VERSION 5.8 ;
BUSBITCHARS "[]" ;
DIVIDERCHAR "/" ;
UNITS
    DATABASE MICRONS 1000 ;
END UNITS

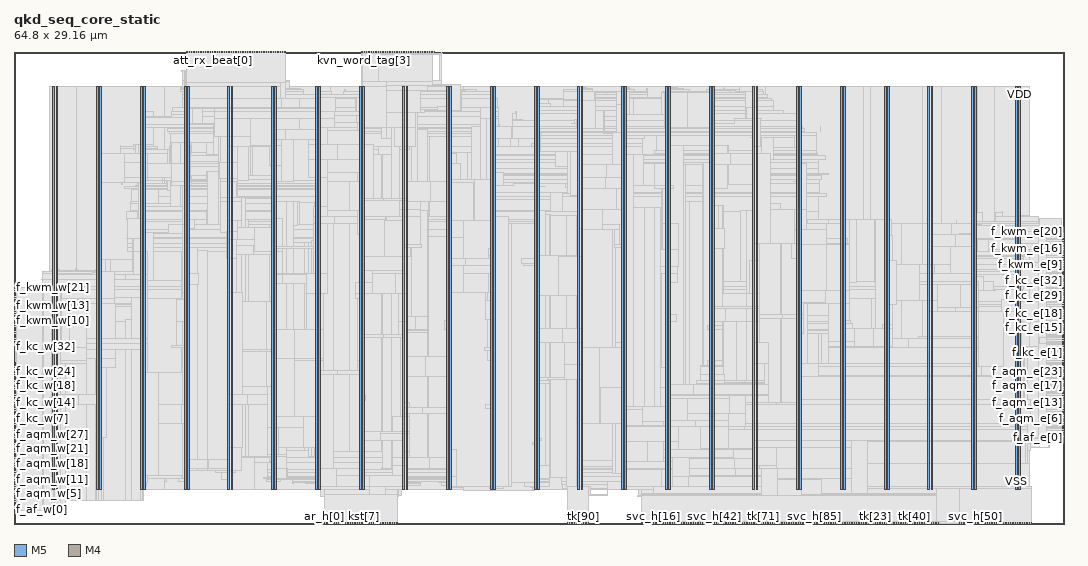
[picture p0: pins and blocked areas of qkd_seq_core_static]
MACRO qkd_seq_core_static
  FOREIGN qkd_seq_core_static 0 0 ;
  CLASS BLOCK ;
  SIZE 64.8 BY 29.16 ;
  PIN ar_h[0]
    DIRECTION INPUT ;
    USE SIGNAL ;
    PORT
      LAYER M5 ;
        RECT  19.152 0 19.176 0.084 ;
    END
  END ar_h[0]
  PIN ar_h[1]
    DIRECTION INPUT ;
    USE SIGNAL ;
    PORT
      LAYER M5 ;
        RECT  19.296 0 19.32 0.084 ;
    END
  END ar_h[1]
  PIN ar_h[2]
    DIRECTION INPUT ;
    USE SIGNAL ;
    PORT
      LAYER M5 ;
        RECT  19.44 0 19.464 0.084 ;
    END
  END ar_h[2]
  PIN ar_h[3]
    DIRECTION INPUT ;
    USE SIGNAL ;
    PORT
      LAYER M5 ;
        RECT  19.584 0 19.608 0.084 ;
    END
  END ar_h[3]
  PIN ar_h[4]
    DIRECTION INPUT ;
    USE SIGNAL ;
    PORT
      LAYER M5 ;
        RECT  19.728 0 19.752 0.084 ;
    END
  END ar_h[4]
  PIN ar_h[5]
    DIRECTION INPUT ;
    USE SIGNAL ;
    PORT
      LAYER M5 ;
        RECT  19.872 0 19.896 0.084 ;
    END
  END ar_h[5]
  PIN ar_h[6]
    DIRECTION INPUT ;
    USE SIGNAL ;
    PORT
      LAYER M5 ;
        RECT  20.016 0 20.04 0.084 ;
    END
  END ar_h[6]
  PIN ar_h[7]
    DIRECTION INPUT ;
    USE SIGNAL ;
    PORT
      LAYER M5 ;
        RECT  20.16 0 20.184 0.084 ;
    END
  END ar_h[7]
  PIN att_rx_beat[0]
    DIRECTION INPUT ;
    USE SIGNAL ;
    PORT
      LAYER M5 ;
        RECT  12.24 29.076 12.264 29.16 ;
    END
  END att_rx_beat[0]
  PIN att_rx_beat[1]
    DIRECTION INPUT ;
    USE SIGNAL ;
    PORT
      LAYER M5 ;
        RECT  12.384 29.076 12.408 29.16 ;
    END
  END att_rx_beat[1]
  PIN att_rx_beat[2]
    DIRECTION INPUT ;
    USE SIGNAL ;
    PORT
      LAYER M5 ;
        RECT  12.528 29.076 12.552 29.16 ;
    END
  END att_rx_beat[2]
  PIN att_rx_beat[3]
    DIRECTION INPUT ;
    USE SIGNAL ;
    PORT
      LAYER M5 ;
        RECT  12.672 29.076 12.696 29.16 ;
    END
  END att_rx_beat[3]
  PIN att_rx_beat[4]
    DIRECTION INPUT ;
    USE SIGNAL ;
    PORT
      LAYER M5 ;
        RECT  12.816 29.076 12.84 29.16 ;
    END
  END att_rx_beat[4]
  PIN att_rx_kind[0]
    DIRECTION INPUT ;
    USE SIGNAL ;
    PORT
      LAYER M5 ;
        RECT  12.96 29.076 12.984 29.16 ;
    END
  END att_rx_kind[0]
  PIN att_rx_kind[1]
    DIRECTION INPUT ;
    USE SIGNAL ;
    PORT
      LAYER M5 ;
        RECT  13.104 29.076 13.128 29.16 ;
    END
  END att_rx_kind[1]
  PIN att_rx_kind[2]
    DIRECTION INPUT ;
    USE SIGNAL ;
    PORT
      LAYER M5 ;
        RECT  13.248 29.076 13.272 29.16 ;
    END
  END att_rx_kind[2]
  PIN att_rx_kind[3]
    DIRECTION INPUT ;
    USE SIGNAL ;
    PORT
      LAYER M5 ;
        RECT  13.392 29.076 13.416 29.16 ;
    END
  END att_rx_kind[3]
  PIN att_rx_v
    DIRECTION INPUT ;
    USE SIGNAL ;
    PORT
      LAYER M5 ;
        RECT  13.536 29.076 13.56 29.16 ;
    END
  END att_rx_v
  PIN ck
    DIRECTION INPUT ;
    USE SIGNAL ;
    PORT
      LAYER M5 ;
        RECT  13.68 29.076 13.704 29.16 ;
    END
  END ck
  PIN cmd_d[0]
    DIRECTION INPUT ;
    USE SIGNAL ;
    PORT
      LAYER M5 ;
        RECT  13.824 29.076 13.848 29.16 ;
    END
  END cmd_d[0]
  PIN cmd_d[10]
    DIRECTION INPUT ;
    USE SIGNAL ;
    PORT
      LAYER M5 ;
        RECT  15.264 29.076 15.288 29.16 ;
    END
  END cmd_d[10]
  PIN cmd_d[11]
    DIRECTION INPUT ;
    USE SIGNAL ;
    PORT
      LAYER M5 ;
        RECT  15.408 29.076 15.432 29.16 ;
    END
  END cmd_d[11]
  PIN cmd_d[12]
    DIRECTION INPUT ;
    USE SIGNAL ;
    PORT
      LAYER M5 ;
        RECT  15.552 29.076 15.576 29.16 ;
    END
  END cmd_d[12]
  PIN cmd_d[13]
    DIRECTION INPUT ;
    USE SIGNAL ;
    PORT
      LAYER M5 ;
        RECT  15.696 29.076 15.72 29.16 ;
    END
  END cmd_d[13]
  PIN cmd_d[14]
    DIRECTION INPUT ;
    USE SIGNAL ;
    PORT
      LAYER M5 ;
        RECT  15.84 29.076 15.864 29.16 ;
    END
  END cmd_d[14]
  PIN cmd_d[15]
    DIRECTION INPUT ;
    USE SIGNAL ;
    PORT
      LAYER M5 ;
        RECT  15.984 29.076 16.008 29.16 ;
    END
  END cmd_d[15]
  PIN cmd_d[16]
    DIRECTION INPUT ;
    USE SIGNAL ;
    PORT
      LAYER M5 ;
        RECT  16.128 29.076 16.152 29.16 ;
    END
  END cmd_d[16]
  PIN cmd_d[17]
    DIRECTION INPUT ;
    USE SIGNAL ;
    PORT
      LAYER M5 ;
        RECT  16.272 29.076 16.296 29.16 ;
    END
  END cmd_d[17]
  PIN cmd_d[18]
    DIRECTION INPUT ;
    USE SIGNAL ;
    PORT
      LAYER M5 ;
        RECT  16.416 29.076 16.44 29.16 ;
    END
  END cmd_d[18]
  PIN cmd_d[1]
    DIRECTION INPUT ;
    USE SIGNAL ;
    PORT
      LAYER M5 ;
        RECT  13.968 29.076 13.992 29.16 ;
    END
  END cmd_d[1]
  PIN cmd_d[2]
    DIRECTION INPUT ;
    USE SIGNAL ;
    PORT
      LAYER M5 ;
        RECT  14.112 29.076 14.136 29.16 ;
    END
  END cmd_d[2]
  PIN cmd_d[3]
    DIRECTION INPUT ;
    USE SIGNAL ;
    PORT
      LAYER M5 ;
        RECT  14.256 29.076 14.28 29.16 ;
    END
  END cmd_d[3]
  PIN cmd_d[4]
    DIRECTION INPUT ;
    USE SIGNAL ;
    PORT
      LAYER M5 ;
        RECT  14.4 29.076 14.424 29.16 ;
    END
  END cmd_d[4]
  PIN cmd_d[5]
    DIRECTION INPUT ;
    USE SIGNAL ;
    PORT
      LAYER M5 ;
        RECT  14.544 29.076 14.568 29.16 ;
    END
  END cmd_d[5]
  PIN cmd_d[6]
    DIRECTION INPUT ;
    USE SIGNAL ;
    PORT
      LAYER M5 ;
        RECT  14.688 29.076 14.712 29.16 ;
    END
  END cmd_d[6]
  PIN cmd_d[7]
    DIRECTION INPUT ;
    USE SIGNAL ;
    PORT
      LAYER M5 ;
        RECT  14.832 29.076 14.856 29.16 ;
    END
  END cmd_d[7]
  PIN cmd_d[8]
    DIRECTION INPUT ;
    USE SIGNAL ;
    PORT
      LAYER M5 ;
        RECT  14.976 29.076 15 29.16 ;
    END
  END cmd_d[8]
  PIN cmd_d[9]
    DIRECTION INPUT ;
    USE SIGNAL ;
    PORT
      LAYER M5 ;
        RECT  15.12 29.076 15.144 29.16 ;
    END
  END cmd_d[9]
  PIN f_af_e[0]
    DIRECTION INPUT ;
    USE SIGNAL ;
    PORT
      LAYER M4 ;
        RECT  64.716 5.328 64.8 5.352 ;
    END
  END f_af_e[0]
  PIN f_af_e[1]
    DIRECTION INPUT ;
    USE SIGNAL ;
    PORT
      LAYER M4 ;
        RECT  64.716 5.472 64.8 5.496 ;
    END
  END f_af_e[1]
  PIN f_af_w[0]
    DIRECTION INPUT ;
    USE SIGNAL ;
    PORT
      LAYER M4 ;
        RECT  0 0.864 0.084 0.888 ;
    END
  END f_af_w[0]
  PIN f_af_w[1]
    DIRECTION INPUT ;
    USE SIGNAL ;
    PORT
      LAYER M4 ;
        RECT  0 1.008 0.084 1.032 ;
    END
  END f_af_w[1]
  PIN f_aqm_e[0]
    DIRECTION OUTPUT ;
    USE SIGNAL ;
    PORT
      LAYER M4 ;
        RECT  64.716 5.616 64.8 5.64 ;
    END
  END f_aqm_e[0]
  PIN f_aqm_e[10]
    DIRECTION OUTPUT ;
    USE SIGNAL ;
    PORT
      LAYER M4 ;
        RECT  64.716 7.056 64.8 7.08 ;
    END
  END f_aqm_e[10]
  PIN f_aqm_e[11]
    DIRECTION OUTPUT ;
    USE SIGNAL ;
    PORT
      LAYER M4 ;
        RECT  64.716 7.2 64.8 7.224 ;
    END
  END f_aqm_e[11]
  PIN f_aqm_e[12]
    DIRECTION OUTPUT ;
    USE SIGNAL ;
    PORT
      LAYER M4 ;
        RECT  64.716 7.344 64.8 7.368 ;
    END
  END f_aqm_e[12]
  PIN f_aqm_e[13]
    DIRECTION OUTPUT ;
    USE SIGNAL ;
    PORT
      LAYER M4 ;
        RECT  64.716 7.488 64.8 7.512 ;
    END
  END f_aqm_e[13]
  PIN f_aqm_e[14]
    DIRECTION OUTPUT ;
    USE SIGNAL ;
    PORT
      LAYER M4 ;
        RECT  64.716 7.632 64.8 7.656 ;
    END
  END f_aqm_e[14]
  PIN f_aqm_e[15]
    DIRECTION OUTPUT ;
    USE SIGNAL ;
    PORT
      LAYER M4 ;
        RECT  64.716 7.776 64.8 7.8 ;
    END
  END f_aqm_e[15]
  PIN f_aqm_e[16]
    DIRECTION OUTPUT ;
    USE SIGNAL ;
    PORT
      LAYER M4 ;
        RECT  64.716 7.92 64.8 7.944 ;
    END
  END f_aqm_e[16]
  PIN f_aqm_e[17]
    DIRECTION OUTPUT ;
    USE SIGNAL ;
    PORT
      LAYER M4 ;
        RECT  64.716 8.064 64.8 8.088 ;
    END
  END f_aqm_e[17]
  PIN f_aqm_e[18]
    DIRECTION OUTPUT ;
    USE SIGNAL ;
    PORT
      LAYER M4 ;
        RECT  64.716 8.208 64.8 8.232 ;
    END
  END f_aqm_e[18]
  PIN f_aqm_e[19]
    DIRECTION OUTPUT ;
    USE SIGNAL ;
    PORT
      LAYER M4 ;
        RECT  64.716 8.352 64.8 8.376 ;
    END
  END f_aqm_e[19]
  PIN f_aqm_e[1]
    DIRECTION OUTPUT ;
    USE SIGNAL ;
    PORT
      LAYER M4 ;
        RECT  64.716 5.76 64.8 5.784 ;
    END
  END f_aqm_e[1]
  PIN f_aqm_e[20]
    DIRECTION OUTPUT ;
    USE SIGNAL ;
    PORT
      LAYER M4 ;
        RECT  64.716 8.496 64.8 8.52 ;
    END
  END f_aqm_e[20]
  PIN f_aqm_e[21]
    DIRECTION OUTPUT ;
    USE SIGNAL ;
    PORT
      LAYER M4 ;
        RECT  64.716 8.64 64.8 8.664 ;
    END
  END f_aqm_e[21]
  PIN f_aqm_e[22]
    DIRECTION OUTPUT ;
    USE SIGNAL ;
    PORT
      LAYER M4 ;
        RECT  64.716 8.784 64.8 8.808 ;
    END
  END f_aqm_e[22]
  PIN f_aqm_e[23]
    DIRECTION OUTPUT ;
    USE SIGNAL ;
    PORT
      LAYER M4 ;
        RECT  64.716 8.928 64.8 8.952 ;
    END
  END f_aqm_e[23]
  PIN f_aqm_e[24]
    DIRECTION OUTPUT ;
    USE SIGNAL ;
    PORT
      LAYER M4 ;
        RECT  64.716 9.072 64.8 9.096 ;
    END
  END f_aqm_e[24]
  PIN f_aqm_e[25]
    DIRECTION OUTPUT ;
    USE SIGNAL ;
    PORT
      LAYER M4 ;
        RECT  64.716 9.216 64.8 9.24 ;
    END
  END f_aqm_e[25]
  PIN f_aqm_e[26]
    DIRECTION OUTPUT ;
    USE SIGNAL ;
    PORT
      LAYER M4 ;
        RECT  64.716 9.36 64.8 9.384 ;
    END
  END f_aqm_e[26]
  PIN f_aqm_e[27]
    DIRECTION OUTPUT ;
    USE SIGNAL ;
    PORT
      LAYER M4 ;
        RECT  64.716 9.504 64.8 9.528 ;
    END
  END f_aqm_e[27]
  PIN f_aqm_e[2]
    DIRECTION OUTPUT ;
    USE SIGNAL ;
    PORT
      LAYER M4 ;
        RECT  64.716 5.904 64.8 5.928 ;
    END
  END f_aqm_e[2]
  PIN f_aqm_e[3]
    DIRECTION OUTPUT ;
    USE SIGNAL ;
    PORT
      LAYER M4 ;
        RECT  64.716 6.048 64.8 6.072 ;
    END
  END f_aqm_e[3]
  PIN f_aqm_e[4]
    DIRECTION OUTPUT ;
    USE SIGNAL ;
    PORT
      LAYER M4 ;
        RECT  64.716 6.192 64.8 6.216 ;
    END
  END f_aqm_e[4]
  PIN f_aqm_e[5]
    DIRECTION OUTPUT ;
    USE SIGNAL ;
    PORT
      LAYER M4 ;
        RECT  64.716 6.336 64.8 6.36 ;
    END
  END f_aqm_e[5]
  PIN f_aqm_e[6]
    DIRECTION OUTPUT ;
    USE SIGNAL ;
    PORT
      LAYER M4 ;
        RECT  64.716 6.48 64.8 6.504 ;
    END
  END f_aqm_e[6]
  PIN f_aqm_e[7]
    DIRECTION OUTPUT ;
    USE SIGNAL ;
    PORT
      LAYER M4 ;
        RECT  64.716 6.624 64.8 6.648 ;
    END
  END f_aqm_e[7]
  PIN f_aqm_e[8]
    DIRECTION OUTPUT ;
    USE SIGNAL ;
    PORT
      LAYER M4 ;
        RECT  64.716 6.768 64.8 6.792 ;
    END
  END f_aqm_e[8]
  PIN f_aqm_e[9]
    DIRECTION OUTPUT ;
    USE SIGNAL ;
    PORT
      LAYER M4 ;
        RECT  64.716 6.912 64.8 6.936 ;
    END
  END f_aqm_e[9]
  PIN f_aqm_w[0]
    DIRECTION OUTPUT ;
    USE SIGNAL ;
    PORT
      LAYER M4 ;
        RECT  0 1.152 0.084 1.176 ;
    END
  END f_aqm_w[0]
  PIN f_aqm_w[10]
    DIRECTION OUTPUT ;
    USE SIGNAL ;
    PORT
      LAYER M4 ;
        RECT  0 2.592 0.084 2.616 ;
    END
  END f_aqm_w[10]
  PIN f_aqm_w[11]
    DIRECTION OUTPUT ;
    USE SIGNAL ;
    PORT
      LAYER M4 ;
        RECT  0 2.736 0.084 2.76 ;
    END
  END f_aqm_w[11]
  PIN f_aqm_w[12]
    DIRECTION OUTPUT ;
    USE SIGNAL ;
    PORT
      LAYER M4 ;
        RECT  0 2.88 0.084 2.904 ;
    END
  END f_aqm_w[12]
  PIN f_aqm_w[13]
    DIRECTION OUTPUT ;
    USE SIGNAL ;
    PORT
      LAYER M4 ;
        RECT  0 3.024 0.084 3.048 ;
    END
  END f_aqm_w[13]
  PIN f_aqm_w[14]
    DIRECTION OUTPUT ;
    USE SIGNAL ;
    PORT
      LAYER M4 ;
        RECT  0 3.168 0.084 3.192 ;
    END
  END f_aqm_w[14]
  PIN f_aqm_w[15]
    DIRECTION OUTPUT ;
    USE SIGNAL ;
    PORT
      LAYER M4 ;
        RECT  0 3.312 0.084 3.336 ;
    END
  END f_aqm_w[15]
  PIN f_aqm_w[16]
    DIRECTION OUTPUT ;
    USE SIGNAL ;
    PORT
      LAYER M4 ;
        RECT  0 3.456 0.084 3.48 ;
    END
  END f_aqm_w[16]
  PIN f_aqm_w[17]
    DIRECTION OUTPUT ;
    USE SIGNAL ;
    PORT
      LAYER M4 ;
        RECT  0 3.6 0.084 3.624 ;
    END
  END f_aqm_w[17]
  PIN f_aqm_w[18]
    DIRECTION OUTPUT ;
    USE SIGNAL ;
    PORT
      LAYER M4 ;
        RECT  0 3.744 0.084 3.768 ;
    END
  END f_aqm_w[18]
  PIN f_aqm_w[19]
    DIRECTION OUTPUT ;
    USE SIGNAL ;
    PORT
      LAYER M4 ;
        RECT  0 3.888 0.084 3.912 ;
    END
  END f_aqm_w[19]
  PIN f_aqm_w[1]
    DIRECTION OUTPUT ;
    USE SIGNAL ;
    PORT
      LAYER M4 ;
        RECT  0 1.296 0.084 1.32 ;
    END
  END f_aqm_w[1]
  PIN f_aqm_w[20]
    DIRECTION OUTPUT ;
    USE SIGNAL ;
    PORT
      LAYER M4 ;
        RECT  0 4.032 0.084 4.056 ;
    END
  END f_aqm_w[20]
  PIN f_aqm_w[21]
    DIRECTION OUTPUT ;
    USE SIGNAL ;
    PORT
      LAYER M4 ;
        RECT  0 4.176 0.084 4.2 ;
    END
  END f_aqm_w[21]
  PIN f_aqm_w[22]
    DIRECTION OUTPUT ;
    USE SIGNAL ;
    PORT
      LAYER M4 ;
        RECT  0 4.32 0.084 4.344 ;
    END
  END f_aqm_w[22]
  PIN f_aqm_w[23]
    DIRECTION OUTPUT ;
    USE SIGNAL ;
    PORT
      LAYER M4 ;
        RECT  0 4.464 0.084 4.488 ;
    END
  END f_aqm_w[23]
  PIN f_aqm_w[24]
    DIRECTION OUTPUT ;
    USE SIGNAL ;
    PORT
      LAYER M4 ;
        RECT  0 4.608 0.084 4.632 ;
    END
  END f_aqm_w[24]
  PIN f_aqm_w[25]
    DIRECTION OUTPUT ;
    USE SIGNAL ;
    PORT
      LAYER M4 ;
        RECT  0 4.752 0.084 4.776 ;
    END
  END f_aqm_w[25]
  PIN f_aqm_w[26]
    DIRECTION OUTPUT ;
    USE SIGNAL ;
    PORT
      LAYER M4 ;
        RECT  0 4.896 0.084 4.92 ;
    END
  END f_aqm_w[26]
  PIN f_aqm_w[27]
    DIRECTION OUTPUT ;
    USE SIGNAL ;
    PORT
      LAYER M4 ;
        RECT  0 5.04 0.084 5.064 ;
    END
  END f_aqm_w[27]
  PIN f_aqm_w[2]
    DIRECTION OUTPUT ;
    USE SIGNAL ;
    PORT
      LAYER M4 ;
        RECT  0 1.44 0.084 1.464 ;
    END
  END f_aqm_w[2]
  PIN f_aqm_w[3]
    DIRECTION OUTPUT ;
    USE SIGNAL ;
    PORT
      LAYER M4 ;
        RECT  0 1.584 0.084 1.608 ;
    END
  END f_aqm_w[3]
  PIN f_aqm_w[4]
    DIRECTION OUTPUT ;
    USE SIGNAL ;
    PORT
      LAYER M4 ;
        RECT  0 1.728 0.084 1.752 ;
    END
  END f_aqm_w[4]
  PIN f_aqm_w[5]
    DIRECTION OUTPUT ;
    USE SIGNAL ;
    PORT
      LAYER M4 ;
        RECT  0 1.872 0.084 1.896 ;
    END
  END f_aqm_w[5]
  PIN f_aqm_w[6]
    DIRECTION OUTPUT ;
    USE SIGNAL ;
    PORT
      LAYER M4 ;
        RECT  0 2.016 0.084 2.04 ;
    END
  END f_aqm_w[6]
  PIN f_aqm_w[7]
    DIRECTION OUTPUT ;
    USE SIGNAL ;
    PORT
      LAYER M4 ;
        RECT  0 2.16 0.084 2.184 ;
    END
  END f_aqm_w[7]
  PIN f_aqm_w[8]
    DIRECTION OUTPUT ;
    USE SIGNAL ;
    PORT
      LAYER M4 ;
        RECT  0 2.304 0.084 2.328 ;
    END
  END f_aqm_w[8]
  PIN f_aqm_w[9]
    DIRECTION OUTPUT ;
    USE SIGNAL ;
    PORT
      LAYER M4 ;
        RECT  0 2.448 0.084 2.472 ;
    END
  END f_aqm_w[9]
  PIN f_cr_e[0]
    DIRECTION INPUT ;
    USE SIGNAL ;
    PORT
      LAYER M4 ;
        RECT  64.716 9.648 64.8 9.672 ;
    END
  END f_cr_e[0]
  PIN f_cr_e[1]
    DIRECTION INPUT ;
    USE SIGNAL ;
    PORT
      LAYER M4 ;
        RECT  64.716 9.792 64.8 9.816 ;
    END
  END f_cr_e[1]
  PIN f_cr_w[0]
    DIRECTION INPUT ;
    USE SIGNAL ;
    PORT
      LAYER M4 ;
        RECT  0 5.184 0.084 5.208 ;
    END
  END f_cr_w[0]
  PIN f_cr_w[1]
    DIRECTION INPUT ;
    USE SIGNAL ;
    PORT
      LAYER M4 ;
        RECT  0 5.328 0.084 5.352 ;
    END
  END f_cr_w[1]
  PIN f_kc_e[0]
    DIRECTION OUTPUT ;
    USE SIGNAL ;
    PORT
      LAYER M4 ;
        RECT  64.716 9.936 64.8 9.96 ;
    END
  END f_kc_e[0]
  PIN f_kc_e[10]
    DIRECTION OUTPUT ;
    USE SIGNAL ;
    PORT
      LAYER M4 ;
        RECT  64.716 11.376 64.8 11.4 ;
    END
  END f_kc_e[10]
  PIN f_kc_e[11]
    DIRECTION OUTPUT ;
    USE SIGNAL ;
    PORT
      LAYER M4 ;
        RECT  64.716 11.52 64.8 11.544 ;
    END
  END f_kc_e[11]
  PIN f_kc_e[12]
    DIRECTION OUTPUT ;
    USE SIGNAL ;
    PORT
      LAYER M4 ;
        RECT  64.716 11.664 64.8 11.688 ;
    END
  END f_kc_e[12]
  PIN f_kc_e[13]
    DIRECTION OUTPUT ;
    USE SIGNAL ;
    PORT
      LAYER M4 ;
        RECT  64.716 11.808 64.8 11.832 ;
    END
  END f_kc_e[13]
  PIN f_kc_e[14]
    DIRECTION OUTPUT ;
    USE SIGNAL ;
    PORT
      LAYER M4 ;
        RECT  64.716 11.952 64.8 11.976 ;
    END
  END f_kc_e[14]
  PIN f_kc_e[15]
    DIRECTION OUTPUT ;
    USE SIGNAL ;
    PORT
      LAYER M4 ;
        RECT  64.716 12.096 64.8 12.12 ;
    END
  END f_kc_e[15]
  PIN f_kc_e[16]
    DIRECTION OUTPUT ;
    USE SIGNAL ;
    PORT
      LAYER M4 ;
        RECT  64.716 12.24 64.8 12.264 ;
    END
  END f_kc_e[16]
  PIN f_kc_e[17]
    DIRECTION OUTPUT ;
    USE SIGNAL ;
    PORT
      LAYER M4 ;
        RECT  64.716 12.384 64.8 12.408 ;
    END
  END f_kc_e[17]
  PIN f_kc_e[18]
    DIRECTION OUTPUT ;
    USE SIGNAL ;
    PORT
      LAYER M4 ;
        RECT  64.716 12.528 64.8 12.552 ;
    END
  END f_kc_e[18]
  PIN f_kc_e[19]
    DIRECTION OUTPUT ;
    USE SIGNAL ;
    PORT
      LAYER M4 ;
        RECT  64.716 12.672 64.8 12.696 ;
    END
  END f_kc_e[19]
  PIN f_kc_e[1]
    DIRECTION OUTPUT ;
    USE SIGNAL ;
    PORT
      LAYER M4 ;
        RECT  64.716 10.08 64.8 10.104 ;
    END
  END f_kc_e[1]
  PIN f_kc_e[20]
    DIRECTION OUTPUT ;
    USE SIGNAL ;
    PORT
      LAYER M4 ;
        RECT  64.716 12.816 64.8 12.84 ;
    END
  END f_kc_e[20]
  PIN f_kc_e[21]
    DIRECTION OUTPUT ;
    USE SIGNAL ;
    PORT
      LAYER M4 ;
        RECT  64.716 12.96 64.8 12.984 ;
    END
  END f_kc_e[21]
  PIN f_kc_e[22]
    DIRECTION OUTPUT ;
    USE SIGNAL ;
    PORT
      LAYER M4 ;
        RECT  64.716 13.104 64.8 13.128 ;
    END
  END f_kc_e[22]
  PIN f_kc_e[23]
    DIRECTION OUTPUT ;
    USE SIGNAL ;
    PORT
      LAYER M4 ;
        RECT  64.716 13.248 64.8 13.272 ;
    END
  END f_kc_e[23]
  PIN f_kc_e[24]
    DIRECTION OUTPUT ;
    USE SIGNAL ;
    PORT
      LAYER M4 ;
        RECT  64.716 13.392 64.8 13.416 ;
    END
  END f_kc_e[24]
  PIN f_kc_e[25]
    DIRECTION OUTPUT ;
    USE SIGNAL ;
    PORT
      LAYER M4 ;
        RECT  64.716 13.536 64.8 13.56 ;
    END
  END f_kc_e[25]
  PIN f_kc_e[26]
    DIRECTION OUTPUT ;
    USE SIGNAL ;
    PORT
      LAYER M4 ;
        RECT  64.716 13.68 64.8 13.704 ;
    END
  END f_kc_e[26]
  PIN f_kc_e[27]
    DIRECTION OUTPUT ;
    USE SIGNAL ;
    PORT
      LAYER M4 ;
        RECT  64.716 13.824 64.8 13.848 ;
    END
  END f_kc_e[27]
  PIN f_kc_e[28]
    DIRECTION OUTPUT ;
    USE SIGNAL ;
    PORT
      LAYER M4 ;
        RECT  64.716 13.968 64.8 13.992 ;
    END
  END f_kc_e[28]
  PIN f_kc_e[29]
    DIRECTION OUTPUT ;
    USE SIGNAL ;
    PORT
      LAYER M4 ;
        RECT  64.716 14.112 64.8 14.136 ;
    END
  END f_kc_e[29]
  PIN f_kc_e[2]
    DIRECTION OUTPUT ;
    USE SIGNAL ;
    PORT
      LAYER M4 ;
        RECT  64.716 10.224 64.8 10.248 ;
    END
  END f_kc_e[2]
  PIN f_kc_e[30]
    DIRECTION OUTPUT ;
    USE SIGNAL ;
    PORT
      LAYER M4 ;
        RECT  64.716 14.256 64.8 14.28 ;
    END
  END f_kc_e[30]
  PIN f_kc_e[31]
    DIRECTION OUTPUT ;
    USE SIGNAL ;
    PORT
      LAYER M4 ;
        RECT  64.716 14.4 64.8 14.424 ;
    END
  END f_kc_e[31]
  PIN f_kc_e[32]
    DIRECTION OUTPUT ;
    USE SIGNAL ;
    PORT
      LAYER M4 ;
        RECT  64.716 14.544 64.8 14.568 ;
    END
  END f_kc_e[32]
  PIN f_kc_e[3]
    DIRECTION OUTPUT ;
    USE SIGNAL ;
    PORT
      LAYER M4 ;
        RECT  64.716 10.368 64.8 10.392 ;
    END
  END f_kc_e[3]
  PIN f_kc_e[4]
    DIRECTION OUTPUT ;
    USE SIGNAL ;
    PORT
      LAYER M4 ;
        RECT  64.716 10.512 64.8 10.536 ;
    END
  END f_kc_e[4]
  PIN f_kc_e[5]
    DIRECTION OUTPUT ;
    USE SIGNAL ;
    PORT
      LAYER M4 ;
        RECT  64.716 10.656 64.8 10.68 ;
    END
  END f_kc_e[5]
  PIN f_kc_e[6]
    DIRECTION OUTPUT ;
    USE SIGNAL ;
    PORT
      LAYER M4 ;
        RECT  64.716 10.8 64.8 10.824 ;
    END
  END f_kc_e[6]
  PIN f_kc_e[7]
    DIRECTION OUTPUT ;
    USE SIGNAL ;
    PORT
      LAYER M4 ;
        RECT  64.716 10.944 64.8 10.968 ;
    END
  END f_kc_e[7]
  PIN f_kc_e[8]
    DIRECTION OUTPUT ;
    USE SIGNAL ;
    PORT
      LAYER M4 ;
        RECT  64.716 11.088 64.8 11.112 ;
    END
  END f_kc_e[8]
  PIN f_kc_e[9]
    DIRECTION OUTPUT ;
    USE SIGNAL ;
    PORT
      LAYER M4 ;
        RECT  64.716 11.232 64.8 11.256 ;
    END
  END f_kc_e[9]
  PIN f_kc_w[0]
    DIRECTION OUTPUT ;
    USE SIGNAL ;
    PORT
      LAYER M4 ;
        RECT  0 5.472 0.084 5.496 ;
    END
  END f_kc_w[0]
  PIN f_kc_w[10]
    DIRECTION OUTPUT ;
    USE SIGNAL ;
    PORT
      LAYER M4 ;
        RECT  0 6.912 0.084 6.936 ;
    END
  END f_kc_w[10]
  PIN f_kc_w[11]
    DIRECTION OUTPUT ;
    USE SIGNAL ;
    PORT
      LAYER M4 ;
        RECT  0 7.056 0.084 7.08 ;
    END
  END f_kc_w[11]
  PIN f_kc_w[12]
    DIRECTION OUTPUT ;
    USE SIGNAL ;
    PORT
      LAYER M4 ;
        RECT  0 7.2 0.084 7.224 ;
    END
  END f_kc_w[12]
  PIN f_kc_w[13]
    DIRECTION OUTPUT ;
    USE SIGNAL ;
    PORT
      LAYER M4 ;
        RECT  0 7.344 0.084 7.368 ;
    END
  END f_kc_w[13]
  PIN f_kc_w[14]
    DIRECTION OUTPUT ;
    USE SIGNAL ;
    PORT
      LAYER M4 ;
        RECT  0 7.488 0.084 7.512 ;
    END
  END f_kc_w[14]
  PIN f_kc_w[15]
    DIRECTION OUTPUT ;
    USE SIGNAL ;
    PORT
      LAYER M4 ;
        RECT  0 7.632 0.084 7.656 ;
    END
  END f_kc_w[15]
  PIN f_kc_w[16]
    DIRECTION OUTPUT ;
    USE SIGNAL ;
    PORT
      LAYER M4 ;
        RECT  0 7.776 0.084 7.8 ;
    END
  END f_kc_w[16]
  PIN f_kc_w[17]
    DIRECTION OUTPUT ;
    USE SIGNAL ;
    PORT
      LAYER M4 ;
        RECT  0 7.92 0.084 7.944 ;
    END
  END f_kc_w[17]
  PIN f_kc_w[18]
    DIRECTION OUTPUT ;
    USE SIGNAL ;
    PORT
      LAYER M4 ;
        RECT  0 8.064 0.084 8.088 ;
    END
  END f_kc_w[18]
  PIN f_kc_w[19]
    DIRECTION OUTPUT ;
    USE SIGNAL ;
    PORT
      LAYER M4 ;
        RECT  0 8.208 0.084 8.232 ;
    END
  END f_kc_w[19]
  PIN f_kc_w[1]
    DIRECTION OUTPUT ;
    USE SIGNAL ;
    PORT
      LAYER M4 ;
        RECT  0 5.616 0.084 5.64 ;
    END
  END f_kc_w[1]
  PIN f_kc_w[20]
    DIRECTION OUTPUT ;
    USE SIGNAL ;
    PORT
      LAYER M4 ;
        RECT  0 8.352 0.084 8.376 ;
    END
  END f_kc_w[20]
  PIN f_kc_w[21]
    DIRECTION OUTPUT ;
    USE SIGNAL ;
    PORT
      LAYER M4 ;
        RECT  0 8.496 0.084 8.52 ;
    END
  END f_kc_w[21]
  PIN f_kc_w[22]
    DIRECTION OUTPUT ;
    USE SIGNAL ;
    PORT
      LAYER M4 ;
        RECT  0 8.64 0.084 8.664 ;
    END
  END f_kc_w[22]
  PIN f_kc_w[23]
    DIRECTION OUTPUT ;
    USE SIGNAL ;
    PORT
      LAYER M4 ;
        RECT  0 8.784 0.084 8.808 ;
    END
  END f_kc_w[23]
  PIN f_kc_w[24]
    DIRECTION OUTPUT ;
    USE SIGNAL ;
    PORT
      LAYER M4 ;
        RECT  0 8.928 0.084 8.952 ;
    END
  END f_kc_w[24]
  PIN f_kc_w[25]
    DIRECTION OUTPUT ;
    USE SIGNAL ;
    PORT
      LAYER M4 ;
        RECT  0 9.072 0.084 9.096 ;
    END
  END f_kc_w[25]
  PIN f_kc_w[26]
    DIRECTION OUTPUT ;
    USE SIGNAL ;
    PORT
      LAYER M4 ;
        RECT  0 9.216 0.084 9.24 ;
    END
  END f_kc_w[26]
  PIN f_kc_w[27]
    DIRECTION OUTPUT ;
    USE SIGNAL ;
    PORT
      LAYER M4 ;
        RECT  0 9.36 0.084 9.384 ;
    END
  END f_kc_w[27]
  PIN f_kc_w[28]
    DIRECTION OUTPUT ;
    USE SIGNAL ;
    PORT
      LAYER M4 ;
        RECT  0 9.504 0.084 9.528 ;
    END
  END f_kc_w[28]
  PIN f_kc_w[29]
    DIRECTION OUTPUT ;
    USE SIGNAL ;
    PORT
      LAYER M4 ;
        RECT  0 9.648 0.084 9.672 ;
    END
  END f_kc_w[29]
  PIN f_kc_w[2]
    DIRECTION OUTPUT ;
    USE SIGNAL ;
    PORT
      LAYER M4 ;
        RECT  0 5.76 0.084 5.784 ;
    END
  END f_kc_w[2]
  PIN f_kc_w[30]
    DIRECTION OUTPUT ;
    USE SIGNAL ;
    PORT
      LAYER M4 ;
        RECT  0 9.792 0.084 9.816 ;
    END
  END f_kc_w[30]
  PIN f_kc_w[31]
    DIRECTION OUTPUT ;
    USE SIGNAL ;
    PORT
      LAYER M4 ;
        RECT  0 9.936 0.084 9.96 ;
    END
  END f_kc_w[31]
  PIN f_kc_w[32]
    DIRECTION OUTPUT ;
    USE SIGNAL ;
    PORT
      LAYER M4 ;
        RECT  0 10.944 0.084 10.968 ;
    END
  END f_kc_w[32]
  PIN f_kc_w[3]
    DIRECTION OUTPUT ;
    USE SIGNAL ;
    PORT
      LAYER M4 ;
        RECT  0 5.904 0.084 5.928 ;
    END
  END f_kc_w[3]
  PIN f_kc_w[4]
    DIRECTION OUTPUT ;
    USE SIGNAL ;
    PORT
      LAYER M4 ;
        RECT  0 6.048 0.084 6.072 ;
    END
  END f_kc_w[4]
  PIN f_kc_w[5]
    DIRECTION OUTPUT ;
    USE SIGNAL ;
    PORT
      LAYER M4 ;
        RECT  0 6.192 0.084 6.216 ;
    END
  END f_kc_w[5]
  PIN f_kc_w[6]
    DIRECTION OUTPUT ;
    USE SIGNAL ;
    PORT
      LAYER M4 ;
        RECT  0 6.336 0.084 6.36 ;
    END
  END f_kc_w[6]
  PIN f_kc_w[7]
    DIRECTION OUTPUT ;
    USE SIGNAL ;
    PORT
      LAYER M4 ;
        RECT  0 6.48 0.084 6.504 ;
    END
  END f_kc_w[7]
  PIN f_kc_w[8]
    DIRECTION OUTPUT ;
    USE SIGNAL ;
    PORT
      LAYER M4 ;
        RECT  0 6.624 0.084 6.648 ;
    END
  END f_kc_w[8]
  PIN f_kc_w[9]
    DIRECTION OUTPUT ;
    USE SIGNAL ;
    PORT
      LAYER M4 ;
        RECT  0 6.768 0.084 6.792 ;
    END
  END f_kc_w[9]
  PIN f_kwm_e[0]
    DIRECTION OUTPUT ;
    USE SIGNAL ;
    PORT
      LAYER M4 ;
        RECT  64.716 14.688 64.8 14.712 ;
    END
  END f_kwm_e[0]
  PIN f_kwm_e[10]
    DIRECTION OUTPUT ;
    USE SIGNAL ;
    PORT
      LAYER M4 ;
        RECT  64.716 16.128 64.8 16.152 ;
    END
  END f_kwm_e[10]
  PIN f_kwm_e[11]
    DIRECTION OUTPUT ;
    USE SIGNAL ;
    PORT
      LAYER M4 ;
        RECT  64.716 16.272 64.8 16.296 ;
    END
  END f_kwm_e[11]
  PIN f_kwm_e[12]
    DIRECTION OUTPUT ;
    USE SIGNAL ;
    PORT
      LAYER M4 ;
        RECT  64.716 16.416 64.8 16.44 ;
    END
  END f_kwm_e[12]
  PIN f_kwm_e[13]
    DIRECTION OUTPUT ;
    USE SIGNAL ;
    PORT
      LAYER M4 ;
        RECT  64.716 16.56 64.8 16.584 ;
    END
  END f_kwm_e[13]
  PIN f_kwm_e[14]
    DIRECTION OUTPUT ;
    USE SIGNAL ;
    PORT
      LAYER M4 ;
        RECT  64.716 16.704 64.8 16.728 ;
    END
  END f_kwm_e[14]
  PIN f_kwm_e[15]
    DIRECTION OUTPUT ;
    USE SIGNAL ;
    PORT
      LAYER M4 ;
        RECT  64.716 16.848 64.8 16.872 ;
    END
  END f_kwm_e[15]
  PIN f_kwm_e[16]
    DIRECTION OUTPUT ;
    USE SIGNAL ;
    PORT
      LAYER M4 ;
        RECT  64.716 16.992 64.8 17.016 ;
    END
  END f_kwm_e[16]
  PIN f_kwm_e[17]
    DIRECTION OUTPUT ;
    USE SIGNAL ;
    PORT
      LAYER M4 ;
        RECT  64.716 17.136 64.8 17.16 ;
    END
  END f_kwm_e[17]
  PIN f_kwm_e[18]
    DIRECTION OUTPUT ;
    USE SIGNAL ;
    PORT
      LAYER M4 ;
        RECT  64.716 17.28 64.8 17.304 ;
    END
  END f_kwm_e[18]
  PIN f_kwm_e[19]
    DIRECTION OUTPUT ;
    USE SIGNAL ;
    PORT
      LAYER M4 ;
        RECT  64.716 17.424 64.8 17.448 ;
    END
  END f_kwm_e[19]
  PIN f_kwm_e[1]
    DIRECTION OUTPUT ;
    USE SIGNAL ;
    PORT
      LAYER M4 ;
        RECT  64.716 14.832 64.8 14.856 ;
    END
  END f_kwm_e[1]
  PIN f_kwm_e[20]
    DIRECTION OUTPUT ;
    USE SIGNAL ;
    PORT
      LAYER M4 ;
        RECT  64.716 17.568 64.8 17.592 ;
    END
  END f_kwm_e[20]
  PIN f_kwm_e[21]
    DIRECTION OUTPUT ;
    USE SIGNAL ;
    PORT
      LAYER M4 ;
        RECT  64.716 17.712 64.8 17.736 ;
    END
  END f_kwm_e[21]
  PIN f_kwm_e[22]
    DIRECTION OUTPUT ;
    USE SIGNAL ;
    PORT
      LAYER M4 ;
        RECT  64.716 17.856 64.8 17.88 ;
    END
  END f_kwm_e[22]
  PIN f_kwm_e[2]
    DIRECTION OUTPUT ;
    USE SIGNAL ;
    PORT
      LAYER M4 ;
        RECT  64.716 14.976 64.8 15 ;
    END
  END f_kwm_e[2]
  PIN f_kwm_e[3]
    DIRECTION OUTPUT ;
    USE SIGNAL ;
    PORT
      LAYER M4 ;
        RECT  64.716 15.12 64.8 15.144 ;
    END
  END f_kwm_e[3]
  PIN f_kwm_e[4]
    DIRECTION OUTPUT ;
    USE SIGNAL ;
    PORT
      LAYER M4 ;
        RECT  64.716 15.264 64.8 15.288 ;
    END
  END f_kwm_e[4]
  PIN f_kwm_e[5]
    DIRECTION OUTPUT ;
    USE SIGNAL ;
    PORT
      LAYER M4 ;
        RECT  64.716 15.408 64.8 15.432 ;
    END
  END f_kwm_e[5]
  PIN f_kwm_e[6]
    DIRECTION OUTPUT ;
    USE SIGNAL ;
    PORT
      LAYER M4 ;
        RECT  64.716 15.552 64.8 15.576 ;
    END
  END f_kwm_e[6]
  PIN f_kwm_e[7]
    DIRECTION OUTPUT ;
    USE SIGNAL ;
    PORT
      LAYER M4 ;
        RECT  64.716 15.696 64.8 15.72 ;
    END
  END f_kwm_e[7]
  PIN f_kwm_e[8]
    DIRECTION OUTPUT ;
    USE SIGNAL ;
    PORT
      LAYER M4 ;
        RECT  64.716 15.84 64.8 15.864 ;
    END
  END f_kwm_e[8]
  PIN f_kwm_e[9]
    DIRECTION OUTPUT ;
    USE SIGNAL ;
    PORT
      LAYER M4 ;
        RECT  64.716 15.984 64.8 16.008 ;
    END
  END f_kwm_e[9]
  PIN f_kwm_w[0]
    DIRECTION OUTPUT ;
    USE SIGNAL ;
    PORT
      LAYER M4 ;
        RECT  0 11.088 0.084 11.112 ;
    END
  END f_kwm_w[0]
  PIN f_kwm_w[10]
    DIRECTION OUTPUT ;
    USE SIGNAL ;
    PORT
      LAYER M4 ;
        RECT  0 12.528 0.084 12.552 ;
    END
  END f_kwm_w[10]
  PIN f_kwm_w[11]
    DIRECTION OUTPUT ;
    USE SIGNAL ;
    PORT
      LAYER M4 ;
        RECT  0 12.672 0.084 12.696 ;
    END
  END f_kwm_w[11]
  PIN f_kwm_w[12]
    DIRECTION OUTPUT ;
    USE SIGNAL ;
    PORT
      LAYER M4 ;
        RECT  0 12.816 0.084 12.84 ;
    END
  END f_kwm_w[12]
  PIN f_kwm_w[13]
    DIRECTION OUTPUT ;
    USE SIGNAL ;
    PORT
      LAYER M4 ;
        RECT  0 12.96 0.084 12.984 ;
    END
  END f_kwm_w[13]
  PIN f_kwm_w[14]
    DIRECTION OUTPUT ;
    USE SIGNAL ;
    PORT
      LAYER M4 ;
        RECT  0 13.104 0.084 13.128 ;
    END
  END f_kwm_w[14]
  PIN f_kwm_w[15]
    DIRECTION OUTPUT ;
    USE SIGNAL ;
    PORT
      LAYER M4 ;
        RECT  0 13.248 0.084 13.272 ;
    END
  END f_kwm_w[15]
  PIN f_kwm_w[16]
    DIRECTION OUTPUT ;
    USE SIGNAL ;
    PORT
      LAYER M4 ;
        RECT  0 13.392 0.084 13.416 ;
    END
  END f_kwm_w[16]
  PIN f_kwm_w[17]
    DIRECTION OUTPUT ;
    USE SIGNAL ;
    PORT
      LAYER M4 ;
        RECT  0 13.536 0.084 13.56 ;
    END
  END f_kwm_w[17]
  PIN f_kwm_w[18]
    DIRECTION OUTPUT ;
    USE SIGNAL ;
    PORT
      LAYER M4 ;
        RECT  0 13.68 0.084 13.704 ;
    END
  END f_kwm_w[18]
  PIN f_kwm_w[19]
    DIRECTION OUTPUT ;
    USE SIGNAL ;
    PORT
      LAYER M4 ;
        RECT  0 13.824 0.084 13.848 ;
    END
  END f_kwm_w[19]
  PIN f_kwm_w[1]
    DIRECTION OUTPUT ;
    USE SIGNAL ;
    PORT
      LAYER M4 ;
        RECT  0 11.232 0.084 11.256 ;
    END
  END f_kwm_w[1]
  PIN f_kwm_w[20]
    DIRECTION OUTPUT ;
    USE SIGNAL ;
    PORT
      LAYER M4 ;
        RECT  0 13.968 0.084 13.992 ;
    END
  END f_kwm_w[20]
  PIN f_kwm_w[21]
    DIRECTION OUTPUT ;
    USE SIGNAL ;
    PORT
      LAYER M4 ;
        RECT  0 14.112 0.084 14.136 ;
    END
  END f_kwm_w[21]
  PIN f_kwm_w[22]
    DIRECTION OUTPUT ;
    USE SIGNAL ;
    PORT
      LAYER M4 ;
        RECT  0 14.256 0.084 14.28 ;
    END
  END f_kwm_w[22]
  PIN f_kwm_w[2]
    DIRECTION OUTPUT ;
    USE SIGNAL ;
    PORT
      LAYER M4 ;
        RECT  0 11.376 0.084 11.4 ;
    END
  END f_kwm_w[2]
  PIN f_kwm_w[3]
    DIRECTION OUTPUT ;
    USE SIGNAL ;
    PORT
      LAYER M4 ;
        RECT  0 11.52 0.084 11.544 ;
    END
  END f_kwm_w[3]
  PIN f_kwm_w[4]
    DIRECTION OUTPUT ;
    USE SIGNAL ;
    PORT
      LAYER M4 ;
        RECT  0 11.664 0.084 11.688 ;
    END
  END f_kwm_w[4]
  PIN f_kwm_w[5]
    DIRECTION OUTPUT ;
    USE SIGNAL ;
    PORT
      LAYER M4 ;
        RECT  0 11.808 0.084 11.832 ;
    END
  END f_kwm_w[5]
  PIN f_kwm_w[6]
    DIRECTION OUTPUT ;
    USE SIGNAL ;
    PORT
      LAYER M4 ;
        RECT  0 11.952 0.084 11.976 ;
    END
  END f_kwm_w[6]
  PIN f_kwm_w[7]
    DIRECTION OUTPUT ;
    USE SIGNAL ;
    PORT
      LAYER M4 ;
        RECT  0 12.096 0.084 12.12 ;
    END
  END f_kwm_w[7]
  PIN f_kwm_w[8]
    DIRECTION OUTPUT ;
    USE SIGNAL ;
    PORT
      LAYER M4 ;
        RECT  0 12.24 0.084 12.264 ;
    END
  END f_kwm_w[8]
  PIN f_kwm_w[9]
    DIRECTION OUTPUT ;
    USE SIGNAL ;
    PORT
      LAYER M4 ;
        RECT  0 12.384 0.084 12.408 ;
    END
  END f_kwm_w[9]
  PIN f_mf_e[0]
    DIRECTION INPUT ;
    USE SIGNAL ;
    PORT
      LAYER M4 ;
        RECT  64.716 18 64.8 18.024 ;
    END
  END f_mf_e[0]
  PIN f_mf_e[1]
    DIRECTION INPUT ;
    USE SIGNAL ;
    PORT
      LAYER M4 ;
        RECT  64.716 18.144 64.8 18.168 ;
    END
  END f_mf_e[1]
  PIN f_mf_w[0]
    DIRECTION INPUT ;
    USE SIGNAL ;
    PORT
      LAYER M4 ;
        RECT  0 14.4 0.084 14.424 ;
    END
  END f_mf_w[0]
  PIN f_mf_w[1]
    DIRECTION INPUT ;
    USE SIGNAL ;
    PORT
      LAYER M4 ;
        RECT  0 14.544 0.084 14.568 ;
    END
  END f_mf_w[1]
  PIN hf
    DIRECTION INPUT ;
    USE SIGNAL ;
    PORT
      LAYER M5 ;
        RECT  20.304 0 20.328 0.084 ;
    END
  END hf
  PIN hs
    DIRECTION OUTPUT ;
    USE SIGNAL ;
    PORT
      LAYER M5 ;
        RECT  20.448 0 20.472 0.084 ;
    END
  END hs
  PIN kst[0]
    DIRECTION OUTPUT ;
    USE SIGNAL ;
    PORT
      LAYER M5 ;
        RECT  20.592 0 20.616 0.084 ;
    END
  END kst[0]
  PIN kst[1]
    DIRECTION OUTPUT ;
    USE SIGNAL ;
    PORT
      LAYER M5 ;
        RECT  20.736 0 20.76 0.084 ;
    END
  END kst[1]
  PIN kst[2]
    DIRECTION OUTPUT ;
    USE SIGNAL ;
    PORT
      LAYER M5 ;
        RECT  20.88 0 20.904 0.084 ;
    END
  END kst[2]
  PIN kst[3]
    DIRECTION OUTPUT ;
    USE SIGNAL ;
    PORT
      LAYER M5 ;
        RECT  21.024 0 21.048 0.084 ;
    END
  END kst[3]
  PIN kst[4]
    DIRECTION OUTPUT ;
    USE SIGNAL ;
    PORT
      LAYER M5 ;
        RECT  21.168 0 21.192 0.084 ;
    END
  END kst[4]
  PIN kst[5]
    DIRECTION OUTPUT ;
    USE SIGNAL ;
    PORT
      LAYER M5 ;
        RECT  21.312 0 21.336 0.084 ;
    END
  END kst[5]
  PIN kst[6]
    DIRECTION OUTPUT ;
    USE SIGNAL ;
    PORT
      LAYER M5 ;
        RECT  21.456 0 21.48 0.084 ;
    END
  END kst[6]
  PIN kst[7]
    DIRECTION OUTPUT ;
    USE SIGNAL ;
    PORT
      LAYER M5 ;
        RECT  21.6 0 21.624 0.084 ;
    END
  END kst[7]
  PIN kst[8]
    DIRECTION OUTPUT ;
    USE SIGNAL ;
    PORT
      LAYER M5 ;
        RECT  21.744 0 21.768 0.084 ;
    END
  END kst[8]
  PIN kst[9]
    DIRECTION OUTPUT ;
    USE SIGNAL ;
    PORT
      LAYER M5 ;
        RECT  21.888 0 21.912 0.084 ;
    END
  END kst[9]
  PIN kvn_word_tag[0]
    DIRECTION INPUT ;
    USE SIGNAL ;
    PORT
      LAYER M5 ;
        RECT  16.56 29.076 16.584 29.16 ;
    END
  END kvn_word_tag[0]
  PIN kvn_word_tag[10]
    DIRECTION INPUT ;
    USE SIGNAL ;
    PORT
      LAYER M5 ;
        RECT  22.608 29.076 22.632 29.16 ;
    END
  END kvn_word_tag[10]
  PIN kvn_word_tag[1]
    DIRECTION INPUT ;
    USE SIGNAL ;
    PORT
      LAYER M5 ;
        RECT  16.704 29.076 16.728 29.16 ;
    END
  END kvn_word_tag[1]
  PIN kvn_word_tag[2]
    DIRECTION INPUT ;
    USE SIGNAL ;
    PORT
      LAYER M5 ;
        RECT  21.456 29.076 21.48 29.16 ;
    END
  END kvn_word_tag[2]
  PIN kvn_word_tag[3]
    DIRECTION INPUT ;
    USE SIGNAL ;
    PORT
      LAYER M5 ;
        RECT  21.6 29.076 21.624 29.16 ;
    END
  END kvn_word_tag[3]
  PIN kvn_word_tag[4]
    DIRECTION INPUT ;
    USE SIGNAL ;
    PORT
      LAYER M5 ;
        RECT  21.744 29.076 21.768 29.16 ;
    END
  END kvn_word_tag[4]
  PIN kvn_word_tag[5]
    DIRECTION INPUT ;
    USE SIGNAL ;
    PORT
      LAYER M5 ;
        RECT  21.888 29.076 21.912 29.16 ;
    END
  END kvn_word_tag[5]
  PIN kvn_word_tag[6]
    DIRECTION INPUT ;
    USE SIGNAL ;
    PORT
      LAYER M5 ;
        RECT  22.032 29.076 22.056 29.16 ;
    END
  END kvn_word_tag[6]
  PIN kvn_word_tag[7]
    DIRECTION INPUT ;
    USE SIGNAL ;
    PORT
      LAYER M5 ;
        RECT  22.176 29.076 22.2 29.16 ;
    END
  END kvn_word_tag[7]
  PIN kvn_word_tag[8]
    DIRECTION INPUT ;
    USE SIGNAL ;
    PORT
      LAYER M5 ;
        RECT  22.32 29.076 22.344 29.16 ;
    END
  END kvn_word_tag[8]
  PIN kvn_word_tag[9]
    DIRECTION INPUT ;
    USE SIGNAL ;
    PORT
      LAYER M5 ;
        RECT  22.464 29.076 22.488 29.16 ;
    END
  END kvn_word_tag[9]
  PIN kvn_word_valid
    DIRECTION INPUT ;
    USE SIGNAL ;
    PORT
      LAYER M5 ;
        RECT  22.752 29.076 22.776 29.16 ;
    END
  END kvn_word_valid
  PIN lp_ctx_t[0]
    DIRECTION INPUT ;
    USE SIGNAL ;
    PORT
      LAYER M5 ;
        RECT  22.896 29.076 22.92 29.16 ;
    END
  END lp_ctx_t[0]
  PIN lp_ctx_t[10]
    DIRECTION INPUT ;
    USE SIGNAL ;
    PORT
      LAYER M5 ;
        RECT  24.336 29.076 24.36 29.16 ;
    END
  END lp_ctx_t[10]
  PIN lp_ctx_t[11]
    DIRECTION INPUT ;
    USE SIGNAL ;
    PORT
      LAYER M5 ;
        RECT  24.48 29.076 24.504 29.16 ;
    END
  END lp_ctx_t[11]
  PIN lp_ctx_t[12]
    DIRECTION INPUT ;
    USE SIGNAL ;
    PORT
      LAYER M5 ;
        RECT  24.624 29.076 24.648 29.16 ;
    END
  END lp_ctx_t[12]
  PIN lp_ctx_t[13]
    DIRECTION INPUT ;
    USE SIGNAL ;
    PORT
      LAYER M5 ;
        RECT  24.768 29.076 24.792 29.16 ;
    END
  END lp_ctx_t[13]
  PIN lp_ctx_t[1]
    DIRECTION INPUT ;
    USE SIGNAL ;
    PORT
      LAYER M5 ;
        RECT  23.04 29.076 23.064 29.16 ;
    END
  END lp_ctx_t[1]
  PIN lp_ctx_t[2]
    DIRECTION INPUT ;
    USE SIGNAL ;
    PORT
      LAYER M5 ;
        RECT  23.184 29.076 23.208 29.16 ;
    END
  END lp_ctx_t[2]
  PIN lp_ctx_t[3]
    DIRECTION INPUT ;
    USE SIGNAL ;
    PORT
      LAYER M5 ;
        RECT  23.328 29.076 23.352 29.16 ;
    END
  END lp_ctx_t[3]
  PIN lp_ctx_t[4]
    DIRECTION INPUT ;
    USE SIGNAL ;
    PORT
      LAYER M5 ;
        RECT  23.472 29.076 23.496 29.16 ;
    END
  END lp_ctx_t[4]
  PIN lp_ctx_t[5]
    DIRECTION INPUT ;
    USE SIGNAL ;
    PORT
      LAYER M5 ;
        RECT  23.616 29.076 23.64 29.16 ;
    END
  END lp_ctx_t[5]
  PIN lp_ctx_t[6]
    DIRECTION INPUT ;
    USE SIGNAL ;
    PORT
      LAYER M5 ;
        RECT  23.76 29.076 23.784 29.16 ;
    END
  END lp_ctx_t[6]
  PIN lp_ctx_t[7]
    DIRECTION INPUT ;
    USE SIGNAL ;
    PORT
      LAYER M5 ;
        RECT  23.904 29.076 23.928 29.16 ;
    END
  END lp_ctx_t[7]
  PIN lp_ctx_t[8]
    DIRECTION INPUT ;
    USE SIGNAL ;
    PORT
      LAYER M5 ;
        RECT  24.048 29.076 24.072 29.16 ;
    END
  END lp_ctx_t[8]
  PIN lp_ctx_t[9]
    DIRECTION INPUT ;
    USE SIGNAL ;
    PORT
      LAYER M5 ;
        RECT  24.192 29.076 24.216 29.16 ;
    END
  END lp_ctx_t[9]
  PIN lp_layer[0]
    DIRECTION INPUT ;
    USE SIGNAL ;
    PORT
      LAYER M5 ;
        RECT  24.912 29.076 24.936 29.16 ;
    END
  END lp_layer[0]
  PIN lp_layer[1]
    DIRECTION INPUT ;
    USE SIGNAL ;
    PORT
      LAYER M5 ;
        RECT  25.056 29.076 25.08 29.16 ;
    END
  END lp_layer[1]
  PIN lp_layer[2]
    DIRECTION INPUT ;
    USE SIGNAL ;
    PORT
      LAYER M5 ;
        RECT  25.2 29.076 25.224 29.16 ;
    END
  END lp_layer[2]
  PIN lp_layer[3]
    DIRECTION INPUT ;
    USE SIGNAL ;
    PORT
      LAYER M5 ;
        RECT  25.344 29.076 25.368 29.16 ;
    END
  END lp_layer[3]
  PIN lp_layer[4]
    DIRECTION INPUT ;
    USE SIGNAL ;
    PORT
      LAYER M5 ;
        RECT  25.488 29.076 25.512 29.16 ;
    END
  END lp_layer[4]
  PIN lp_layer[5]
    DIRECTION INPUT ;
    USE SIGNAL ;
    PORT
      LAYER M5 ;
        RECT  25.632 29.076 25.656 29.16 ;
    END
  END lp_layer[5]
  PIN lp_run
    DIRECTION INPUT ;
    USE SIGNAL ;
    PORT
      LAYER M5 ;
        RECT  25.776 29.076 25.8 29.16 ;
    END
  END lp_run
  PIN rst_n
    DIRECTION INPUT ;
    USE SIGNAL ;
    PORT
      LAYER M5 ;
        RECT  22.032 0 22.056 0.084 ;
    END
  END rst_n
  PIN s_kidx[0]
    DIRECTION OUTPUT ;
    USE SIGNAL ;
    PORT
      LAYER M5 ;
        RECT  25.92 29.076 25.944 29.16 ;
    END
  END s_kidx[0]
  PIN s_kidx[1]
    DIRECTION OUTPUT ;
    USE SIGNAL ;
    PORT
      LAYER M5 ;
        RECT  10.656 29.076 10.68 29.16 ;
    END
  END s_kidx[1]
  PIN s_kidx[2]
    DIRECTION OUTPUT ;
    USE SIGNAL ;
    PORT
      LAYER M5 ;
        RECT  10.8 29.076 10.824 29.16 ;
    END
  END s_kidx[2]
  PIN s_kpop
    DIRECTION OUTPUT ;
    USE SIGNAL ;
    PORT
      LAYER M5 ;
        RECT  10.944 29.076 10.968 29.16 ;
    END
  END s_kpop
  PIN s_kwgo
    DIRECTION OUTPUT ;
    USE SIGNAL ;
    PORT
      LAYER M5 ;
        RECT  11.088 29.076 11.112 29.16 ;
    END
  END s_kwgo
  PIN s_kwn[0]
    DIRECTION OUTPUT ;
    USE SIGNAL ;
    PORT
      LAYER M5 ;
        RECT  11.232 29.076 11.256 29.16 ;
    END
  END s_kwn[0]
  PIN s_kwn[1]
    DIRECTION OUTPUT ;
    USE SIGNAL ;
    PORT
      LAYER M5 ;
        RECT  11.376 29.076 11.4 29.16 ;
    END
  END s_kwn[1]
  PIN s_qpop
    DIRECTION OUTPUT ;
    USE SIGNAL ;
    PORT
      LAYER M5 ;
        RECT  11.52 29.076 11.544 29.16 ;
    END
  END s_qpop
  PIN svc_h[0]
    DIRECTION INPUT ;
    USE SIGNAL ;
    PORT
      LAYER M5 ;
        RECT  22.176 0 22.2 0.084 ;
    END
  END svc_h[0]
  PIN svc_h[10]
    DIRECTION INPUT ;
    USE SIGNAL ;
    PORT
      LAYER M5 ;
        RECT  23.616 0 23.64 0.084 ;
    END
  END svc_h[10]
  PIN svc_h[11]
    DIRECTION INPUT ;
    USE SIGNAL ;
    PORT
      LAYER M5 ;
        RECT  38.736 0 38.76 0.084 ;
    END
  END svc_h[11]
  PIN svc_h[12]
    DIRECTION INPUT ;
    USE SIGNAL ;
    PORT
      LAYER M5 ;
        RECT  38.88 0 38.904 0.084 ;
    END
  END svc_h[12]
  PIN svc_h[13]
    DIRECTION INPUT ;
    USE SIGNAL ;
    PORT
      LAYER M5 ;
        RECT  39.024 0 39.048 0.084 ;
    END
  END svc_h[13]
  PIN svc_h[14]
    DIRECTION INPUT ;
    USE SIGNAL ;
    PORT
      LAYER M5 ;
        RECT  39.168 0 39.192 0.084 ;
    END
  END svc_h[14]
  PIN svc_h[15]
    DIRECTION INPUT ;
    USE SIGNAL ;
    PORT
      LAYER M5 ;
        RECT  39.312 0 39.336 0.084 ;
    END
  END svc_h[15]
  PIN svc_h[16]
    DIRECTION INPUT ;
    USE SIGNAL ;
    PORT
      LAYER M5 ;
        RECT  39.456 0 39.48 0.084 ;
    END
  END svc_h[16]
  PIN svc_h[17]
    DIRECTION INPUT ;
    USE SIGNAL ;
    PORT
      LAYER M5 ;
        RECT  39.6 0 39.624 0.084 ;
    END
  END svc_h[17]
  PIN svc_h[18]
    DIRECTION INPUT ;
    USE SIGNAL ;
    PORT
      LAYER M5 ;
        RECT  39.744 0 39.768 0.084 ;
    END
  END svc_h[18]
  PIN svc_h[19]
    DIRECTION INPUT ;
    USE SIGNAL ;
    PORT
      LAYER M5 ;
        RECT  39.888 0 39.912 0.084 ;
    END
  END svc_h[19]
  PIN svc_h[1]
    DIRECTION INPUT ;
    USE SIGNAL ;
    PORT
      LAYER M5 ;
        RECT  22.32 0 22.344 0.084 ;
    END
  END svc_h[1]
  PIN svc_h[20]
    DIRECTION INPUT ;
    USE SIGNAL ;
    PORT
      LAYER M5 ;
        RECT  40.032 0 40.056 0.084 ;
    END
  END svc_h[20]
  PIN svc_h[21]
    DIRECTION INPUT ;
    USE SIGNAL ;
    PORT
      LAYER M5 ;
        RECT  40.176 0 40.2 0.084 ;
    END
  END svc_h[21]
  PIN svc_h[22]
    DIRECTION INPUT ;
    USE SIGNAL ;
    PORT
      LAYER M5 ;
        RECT  40.32 0 40.344 0.084 ;
    END
  END svc_h[22]
  PIN svc_h[23]
    DIRECTION INPUT ;
    USE SIGNAL ;
    PORT
      LAYER M5 ;
        RECT  40.464 0 40.488 0.084 ;
    END
  END svc_h[23]
  PIN svc_h[24]
    DIRECTION INPUT ;
    USE SIGNAL ;
    PORT
      LAYER M5 ;
        RECT  40.608 0 40.632 0.084 ;
    END
  END svc_h[24]
  PIN svc_h[25]
    DIRECTION INPUT ;
    USE SIGNAL ;
    PORT
      LAYER M5 ;
        RECT  40.752 0 40.776 0.084 ;
    END
  END svc_h[25]
  PIN svc_h[26]
    DIRECTION INPUT ;
    USE SIGNAL ;
    PORT
      LAYER M5 ;
        RECT  40.896 0 40.92 0.084 ;
    END
  END svc_h[26]
  PIN svc_h[27]
    DIRECTION INPUT ;
    USE SIGNAL ;
    PORT
      LAYER M5 ;
        RECT  41.04 0 41.064 0.084 ;
    END
  END svc_h[27]
  PIN svc_h[28]
    DIRECTION INPUT ;
    USE SIGNAL ;
    PORT
      LAYER M5 ;
        RECT  41.184 0 41.208 0.084 ;
    END
  END svc_h[28]
  PIN svc_h[29]
    DIRECTION INPUT ;
    USE SIGNAL ;
    PORT
      LAYER M5 ;
        RECT  41.328 0 41.352 0.084 ;
    END
  END svc_h[29]
  PIN svc_h[2]
    DIRECTION INPUT ;
    USE SIGNAL ;
    PORT
      LAYER M5 ;
        RECT  22.464 0 22.488 0.084 ;
    END
  END svc_h[2]
  PIN svc_h[30]
    DIRECTION INPUT ;
    USE SIGNAL ;
    PORT
      LAYER M5 ;
        RECT  41.472 0 41.496 0.084 ;
    END
  END svc_h[30]
  PIN svc_h[31]
    DIRECTION INPUT ;
    USE SIGNAL ;
    PORT
      LAYER M5 ;
        RECT  41.616 0 41.64 0.084 ;
    END
  END svc_h[31]
  PIN svc_h[32]
    DIRECTION INPUT ;
    USE SIGNAL ;
    PORT
      LAYER M5 ;
        RECT  41.76 0 41.784 0.084 ;
    END
  END svc_h[32]
  PIN svc_h[33]
    DIRECTION INPUT ;
    USE SIGNAL ;
    PORT
      LAYER M5 ;
        RECT  41.904 0 41.928 0.084 ;
    END
  END svc_h[33]
  PIN svc_h[34]
    DIRECTION INPUT ;
    USE SIGNAL ;
    PORT
      LAYER M5 ;
        RECT  42.048 0 42.072 0.084 ;
    END
  END svc_h[34]
  PIN svc_h[35]
    DIRECTION INPUT ;
    USE SIGNAL ;
    PORT
      LAYER M5 ;
        RECT  42.192 0 42.216 0.084 ;
    END
  END svc_h[35]
  PIN svc_h[36]
    DIRECTION INPUT ;
    USE SIGNAL ;
    PORT
      LAYER M5 ;
        RECT  42.336 0 42.36 0.084 ;
    END
  END svc_h[36]
  PIN svc_h[37]
    DIRECTION INPUT ;
    USE SIGNAL ;
    PORT
      LAYER M5 ;
        RECT  42.48 0 42.504 0.084 ;
    END
  END svc_h[37]
  PIN svc_h[38]
    DIRECTION INPUT ;
    USE SIGNAL ;
    PORT
      LAYER M5 ;
        RECT  42.624 0 42.648 0.084 ;
    END
  END svc_h[38]
  PIN svc_h[39]
    DIRECTION INPUT ;
    USE SIGNAL ;
    PORT
      LAYER M5 ;
        RECT  42.768 0 42.792 0.084 ;
    END
  END svc_h[39]
  PIN svc_h[3]
    DIRECTION INPUT ;
    USE SIGNAL ;
    PORT
      LAYER M5 ;
        RECT  22.608 0 22.632 0.084 ;
    END
  END svc_h[3]
  PIN svc_h[40]
    DIRECTION INPUT ;
    USE SIGNAL ;
    PORT
      LAYER M5 ;
        RECT  42.912 0 42.936 0.084 ;
    END
  END svc_h[40]
  PIN svc_h[41]
    DIRECTION INPUT ;
    USE SIGNAL ;
    PORT
      LAYER M5 ;
        RECT  43.056 0 43.08 0.084 ;
    END
  END svc_h[41]
  PIN svc_h[42]
    DIRECTION INPUT ;
    USE SIGNAL ;
    PORT
      LAYER M5 ;
        RECT  43.2 0 43.224 0.084 ;
    END
  END svc_h[42]
  PIN svc_h[43]
    DIRECTION INPUT ;
    USE SIGNAL ;
    PORT
      LAYER M5 ;
        RECT  58.32 0 58.344 0.084 ;
    END
  END svc_h[43]
  PIN svc_h[44]
    DIRECTION INPUT ;
    USE SIGNAL ;
    PORT
      LAYER M5 ;
        RECT  58.464 0 58.488 0.084 ;
    END
  END svc_h[44]
  PIN svc_h[45]
    DIRECTION INPUT ;
    USE SIGNAL ;
    PORT
      LAYER M5 ;
        RECT  58.608 0 58.632 0.084 ;
    END
  END svc_h[45]
  PIN svc_h[46]
    DIRECTION INPUT ;
    USE SIGNAL ;
    PORT
      LAYER M5 ;
        RECT  58.752 0 58.776 0.084 ;
    END
  END svc_h[46]
  PIN svc_h[47]
    DIRECTION INPUT ;
    USE SIGNAL ;
    PORT
      LAYER M5 ;
        RECT  58.896 0 58.92 0.084 ;
    END
  END svc_h[47]
  PIN svc_h[48]
    DIRECTION INPUT ;
    USE SIGNAL ;
    PORT
      LAYER M5 ;
        RECT  59.04 0 59.064 0.084 ;
    END
  END svc_h[48]
  PIN svc_h[49]
    DIRECTION INPUT ;
    USE SIGNAL ;
    PORT
      LAYER M5 ;
        RECT  59.184 0 59.208 0.084 ;
    END
  END svc_h[49]
  PIN svc_h[4]
    DIRECTION INPUT ;
    USE SIGNAL ;
    PORT
      LAYER M5 ;
        RECT  22.752 0 22.776 0.084 ;
    END
  END svc_h[4]
  PIN svc_h[50]
    DIRECTION INPUT ;
    USE SIGNAL ;
    PORT
      LAYER M5 ;
        RECT  59.328 0 59.352 0.084 ;
    END
  END svc_h[50]
  PIN svc_h[51]
    DIRECTION INPUT ;
    USE SIGNAL ;
    PORT
      LAYER M5 ;
        RECT  59.472 0 59.496 0.084 ;
    END
  END svc_h[51]
  PIN svc_h[52]
    DIRECTION INPUT ;
    USE SIGNAL ;
    PORT
      LAYER M5 ;
        RECT  59.616 0 59.64 0.084 ;
    END
  END svc_h[52]
  PIN svc_h[53]
    DIRECTION INPUT ;
    USE SIGNAL ;
    PORT
      LAYER M5 ;
        RECT  59.76 0 59.784 0.084 ;
    END
  END svc_h[53]
  PIN svc_h[54]
    DIRECTION INPUT ;
    USE SIGNAL ;
    PORT
      LAYER M5 ;
        RECT  59.904 0 59.928 0.084 ;
    END
  END svc_h[54]
  PIN svc_h[55]
    DIRECTION INPUT ;
    USE SIGNAL ;
    PORT
      LAYER M5 ;
        RECT  60.048 0 60.072 0.084 ;
    END
  END svc_h[55]
  PIN svc_h[56]
    DIRECTION INPUT ;
    USE SIGNAL ;
    PORT
      LAYER M5 ;
        RECT  60.192 0 60.216 0.084 ;
    END
  END svc_h[56]
  PIN svc_h[57]
    DIRECTION INPUT ;
    USE SIGNAL ;
    PORT
      LAYER M5 ;
        RECT  60.336 0 60.36 0.084 ;
    END
  END svc_h[57]
  PIN svc_h[58]
    DIRECTION INPUT ;
    USE SIGNAL ;
    PORT
      LAYER M5 ;
        RECT  60.48 0 60.504 0.084 ;
    END
  END svc_h[58]
  PIN svc_h[59]
    DIRECTION INPUT ;
    USE SIGNAL ;
    PORT
      LAYER M5 ;
        RECT  60.624 0 60.648 0.084 ;
    END
  END svc_h[59]
  PIN svc_h[5]
    DIRECTION INPUT ;
    USE SIGNAL ;
    PORT
      LAYER M5 ;
        RECT  22.896 0 22.92 0.084 ;
    END
  END svc_h[5]
  PIN svc_h[60]
    DIRECTION INPUT ;
    USE SIGNAL ;
    PORT
      LAYER M5 ;
        RECT  60.768 0 60.792 0.084 ;
    END
  END svc_h[60]
  PIN svc_h[61]
    DIRECTION INPUT ;
    USE SIGNAL ;
    PORT
      LAYER M5 ;
        RECT  60.912 0 60.936 0.084 ;
    END
  END svc_h[61]
  PIN svc_h[62]
    DIRECTION INPUT ;
    USE SIGNAL ;
    PORT
      LAYER M5 ;
        RECT  61.056 0 61.08 0.084 ;
    END
  END svc_h[62]
  PIN svc_h[63]
    DIRECTION INPUT ;
    USE SIGNAL ;
    PORT
      LAYER M5 ;
        RECT  61.2 0 61.224 0.084 ;
    END
  END svc_h[63]
  PIN svc_h[64]
    DIRECTION INPUT ;
    USE SIGNAL ;
    PORT
      LAYER M5 ;
        RECT  61.344 0 61.368 0.084 ;
    END
  END svc_h[64]
  PIN svc_h[65]
    DIRECTION INPUT ;
    USE SIGNAL ;
    PORT
      LAYER M5 ;
        RECT  61.488 0 61.512 0.084 ;
    END
  END svc_h[65]
  PIN svc_h[66]
    DIRECTION INPUT ;
    USE SIGNAL ;
    PORT
      LAYER M5 ;
        RECT  61.632 0 61.656 0.084 ;
    END
  END svc_h[66]
  PIN svc_h[67]
    DIRECTION INPUT ;
    USE SIGNAL ;
    PORT
      LAYER M5 ;
        RECT  61.776 0 61.8 0.084 ;
    END
  END svc_h[67]
  PIN svc_h[68]
    DIRECTION INPUT ;
    USE SIGNAL ;
    PORT
      LAYER M5 ;
        RECT  61.92 0 61.944 0.084 ;
    END
  END svc_h[68]
  PIN svc_h[69]
    DIRECTION INPUT ;
    USE SIGNAL ;
    PORT
      LAYER M5 ;
        RECT  62.064 0 62.088 0.084 ;
    END
  END svc_h[69]
  PIN svc_h[6]
    DIRECTION INPUT ;
    USE SIGNAL ;
    PORT
      LAYER M5 ;
        RECT  23.04 0 23.064 0.084 ;
    END
  END svc_h[6]
  PIN svc_h[70]
    DIRECTION INPUT ;
    USE SIGNAL ;
    PORT
      LAYER M5 ;
        RECT  62.208 0 62.232 0.084 ;
    END
  END svc_h[70]
  PIN svc_h[71]
    DIRECTION INPUT ;
    USE SIGNAL ;
    PORT
      LAYER M5 ;
        RECT  62.352 0 62.376 0.084 ;
    END
  END svc_h[71]
  PIN svc_h[72]
    DIRECTION INPUT ;
    USE SIGNAL ;
    PORT
      LAYER M5 ;
        RECT  62.496 0 62.52 0.084 ;
    END
  END svc_h[72]
  PIN svc_h[73]
    DIRECTION INPUT ;
    USE SIGNAL ;
    PORT
      LAYER M5 ;
        RECT  62.64 0 62.664 0.084 ;
    END
  END svc_h[73]
  PIN svc_h[74]
    DIRECTION INPUT ;
    USE SIGNAL ;
    PORT
      LAYER M5 ;
        RECT  62.784 0 62.808 0.084 ;
    END
  END svc_h[74]
  PIN svc_h[75]
    DIRECTION INPUT ;
    USE SIGNAL ;
    PORT
      LAYER M5 ;
        RECT  47.952 0 47.976 0.084 ;
    END
  END svc_h[75]
  PIN svc_h[76]
    DIRECTION INPUT ;
    USE SIGNAL ;
    PORT
      LAYER M5 ;
        RECT  48.096 0 48.12 0.084 ;
    END
  END svc_h[76]
  PIN svc_h[77]
    DIRECTION INPUT ;
    USE SIGNAL ;
    PORT
      LAYER M5 ;
        RECT  48.24 0 48.264 0.084 ;
    END
  END svc_h[77]
  PIN svc_h[78]
    DIRECTION INPUT ;
    USE SIGNAL ;
    PORT
      LAYER M5 ;
        RECT  48.384 0 48.408 0.084 ;
    END
  END svc_h[78]
  PIN svc_h[79]
    DIRECTION INPUT ;
    USE SIGNAL ;
    PORT
      LAYER M5 ;
        RECT  48.528 0 48.552 0.084 ;
    END
  END svc_h[79]
  PIN svc_h[7]
    DIRECTION INPUT ;
    USE SIGNAL ;
    PORT
      LAYER M5 ;
        RECT  23.184 0 23.208 0.084 ;
    END
  END svc_h[7]
  PIN svc_h[80]
    DIRECTION INPUT ;
    USE SIGNAL ;
    PORT
      LAYER M5 ;
        RECT  48.672 0 48.696 0.084 ;
    END
  END svc_h[80]
  PIN svc_h[81]
    DIRECTION INPUT ;
    USE SIGNAL ;
    PORT
      LAYER M5 ;
        RECT  48.816 0 48.84 0.084 ;
    END
  END svc_h[81]
  PIN svc_h[82]
    DIRECTION INPUT ;
    USE SIGNAL ;
    PORT
      LAYER M5 ;
        RECT  48.96 0 48.984 0.084 ;
    END
  END svc_h[82]
  PIN svc_h[83]
    DIRECTION INPUT ;
    USE SIGNAL ;
    PORT
      LAYER M5 ;
        RECT  49.104 0 49.128 0.084 ;
    END
  END svc_h[83]
  PIN svc_h[84]
    DIRECTION INPUT ;
    USE SIGNAL ;
    PORT
      LAYER M5 ;
        RECT  49.248 0 49.272 0.084 ;
    END
  END svc_h[84]
  PIN svc_h[85]
    DIRECTION INPUT ;
    USE SIGNAL ;
    PORT
      LAYER M5 ;
        RECT  49.392 0 49.416 0.084 ;
    END
  END svc_h[85]
  PIN svc_h[86]
    DIRECTION INPUT ;
    USE SIGNAL ;
    PORT
      LAYER M5 ;
        RECT  49.536 0 49.56 0.084 ;
    END
  END svc_h[86]
  PIN svc_h[87]
    DIRECTION INPUT ;
    USE SIGNAL ;
    PORT
      LAYER M5 ;
        RECT  49.68 0 49.704 0.084 ;
    END
  END svc_h[87]
  PIN svc_h[8]
    DIRECTION INPUT ;
    USE SIGNAL ;
    PORT
      LAYER M5 ;
        RECT  23.328 0 23.352 0.084 ;
    END
  END svc_h[8]
  PIN svc_h[9]
    DIRECTION INPUT ;
    USE SIGNAL ;
    PORT
      LAYER M5 ;
        RECT  23.472 0 23.496 0.084 ;
    END
  END svc_h[9]
  PIN tk[0]
    DIRECTION OUTPUT ;
    USE SIGNAL ;
    PORT
      LAYER M5 ;
        RECT  49.824 0 49.848 0.084 ;
    END
  END tk[0]
  PIN tk[10]
    DIRECTION OUTPUT ;
    USE SIGNAL ;
    PORT
      LAYER M5 ;
        RECT  51.264 0 51.288 0.084 ;
    END
  END tk[10]
  PIN tk[11]
    DIRECTION OUTPUT ;
    USE SIGNAL ;
    PORT
      LAYER M5 ;
        RECT  51.408 0 51.432 0.084 ;
    END
  END tk[11]
  PIN tk[12]
    DIRECTION OUTPUT ;
    USE SIGNAL ;
    PORT
      LAYER M5 ;
        RECT  51.552 0 51.576 0.084 ;
    END
  END tk[12]
  PIN tk[13]
    DIRECTION OUTPUT ;
    USE SIGNAL ;
    PORT
      LAYER M5 ;
        RECT  51.696 0 51.72 0.084 ;
    END
  END tk[13]
  PIN tk[14]
    DIRECTION OUTPUT ;
    USE SIGNAL ;
    PORT
      LAYER M5 ;
        RECT  51.84 0 51.864 0.084 ;
    END
  END tk[14]
  PIN tk[15]
    DIRECTION OUTPUT ;
    USE SIGNAL ;
    PORT
      LAYER M5 ;
        RECT  51.984 0 52.008 0.084 ;
    END
  END tk[15]
  PIN tk[16]
    DIRECTION OUTPUT ;
    USE SIGNAL ;
    PORT
      LAYER M5 ;
        RECT  52.128 0 52.152 0.084 ;
    END
  END tk[16]
  PIN tk[17]
    DIRECTION OUTPUT ;
    USE SIGNAL ;
    PORT
      LAYER M5 ;
        RECT  52.272 0 52.296 0.084 ;
    END
  END tk[17]
  PIN tk[18]
    DIRECTION OUTPUT ;
    USE SIGNAL ;
    PORT
      LAYER M5 ;
        RECT  52.416 0 52.44 0.084 ;
    END
  END tk[18]
  PIN tk[19]
    DIRECTION OUTPUT ;
    USE SIGNAL ;
    PORT
      LAYER M5 ;
        RECT  52.56 0 52.584 0.084 ;
    END
  END tk[19]
  PIN tk[1]
    DIRECTION OUTPUT ;
    USE SIGNAL ;
    PORT
      LAYER M5 ;
        RECT  49.968 0 49.992 0.084 ;
    END
  END tk[1]
  PIN tk[20]
    DIRECTION OUTPUT ;
    USE SIGNAL ;
    PORT
      LAYER M5 ;
        RECT  52.704 0 52.728 0.084 ;
    END
  END tk[20]
  PIN tk[21]
    DIRECTION OUTPUT ;
    USE SIGNAL ;
    PORT
      LAYER M5 ;
        RECT  52.848 0 52.872 0.084 ;
    END
  END tk[21]
  PIN tk[22]
    DIRECTION OUTPUT ;
    USE SIGNAL ;
    PORT
      LAYER M5 ;
        RECT  52.992 0 53.016 0.084 ;
    END
  END tk[22]
  PIN tk[23]
    DIRECTION OUTPUT ;
    USE SIGNAL ;
    PORT
      LAYER M5 ;
        RECT  53.136 0 53.16 0.084 ;
    END
  END tk[23]
  PIN tk[24]
    DIRECTION OUTPUT ;
    USE SIGNAL ;
    PORT
      LAYER M5 ;
        RECT  53.28 0 53.304 0.084 ;
    END
  END tk[24]
  PIN tk[25]
    DIRECTION OUTPUT ;
    USE SIGNAL ;
    PORT
      LAYER M5 ;
        RECT  53.424 0 53.448 0.084 ;
    END
  END tk[25]
  PIN tk[26]
    DIRECTION OUTPUT ;
    USE SIGNAL ;
    PORT
      LAYER M5 ;
        RECT  53.568 0 53.592 0.084 ;
    END
  END tk[26]
  PIN tk[27]
    DIRECTION OUTPUT ;
    USE SIGNAL ;
    PORT
      LAYER M5 ;
        RECT  53.712 0 53.736 0.084 ;
    END
  END tk[27]
  PIN tk[28]
    DIRECTION OUTPUT ;
    USE SIGNAL ;
    PORT
      LAYER M5 ;
        RECT  53.856 0 53.88 0.084 ;
    END
  END tk[28]
  PIN tk[29]
    DIRECTION OUTPUT ;
    USE SIGNAL ;
    PORT
      LAYER M5 ;
        RECT  54 0 54.024 0.084 ;
    END
  END tk[29]
  PIN tk[2]
    DIRECTION OUTPUT ;
    USE SIGNAL ;
    PORT
      LAYER M5 ;
        RECT  50.112 0 50.136 0.084 ;
    END
  END tk[2]
  PIN tk[30]
    DIRECTION OUTPUT ;
    USE SIGNAL ;
    PORT
      LAYER M5 ;
        RECT  54.144 0 54.168 0.084 ;
    END
  END tk[30]
  PIN tk[31]
    DIRECTION OUTPUT ;
    USE SIGNAL ;
    PORT
      LAYER M5 ;
        RECT  54.288 0 54.312 0.084 ;
    END
  END tk[31]
  PIN tk[32]
    DIRECTION OUTPUT ;
    USE SIGNAL ;
    PORT
      LAYER M5 ;
        RECT  54.432 0 54.456 0.084 ;
    END
  END tk[32]
  PIN tk[33]
    DIRECTION OUTPUT ;
    USE SIGNAL ;
    PORT
      LAYER M5 ;
        RECT  54.576 0 54.6 0.084 ;
    END
  END tk[33]
  PIN tk[34]
    DIRECTION OUTPUT ;
    USE SIGNAL ;
    PORT
      LAYER M5 ;
        RECT  54.72 0 54.744 0.084 ;
    END
  END tk[34]
  PIN tk[35]
    DIRECTION OUTPUT ;
    USE SIGNAL ;
    PORT
      LAYER M5 ;
        RECT  54.864 0 54.888 0.084 ;
    END
  END tk[35]
  PIN tk[36]
    DIRECTION OUTPUT ;
    USE SIGNAL ;
    PORT
      LAYER M5 ;
        RECT  55.008 0 55.032 0.084 ;
    END
  END tk[36]
  PIN tk[37]
    DIRECTION OUTPUT ;
    USE SIGNAL ;
    PORT
      LAYER M5 ;
        RECT  55.152 0 55.176 0.084 ;
    END
  END tk[37]
  PIN tk[38]
    DIRECTION OUTPUT ;
    USE SIGNAL ;
    PORT
      LAYER M5 ;
        RECT  55.296 0 55.32 0.084 ;
    END
  END tk[38]
  PIN tk[39]
    DIRECTION OUTPUT ;
    USE SIGNAL ;
    PORT
      LAYER M5 ;
        RECT  55.44 0 55.464 0.084 ;
    END
  END tk[39]
  PIN tk[3]
    DIRECTION OUTPUT ;
    USE SIGNAL ;
    PORT
      LAYER M5 ;
        RECT  50.256 0 50.28 0.084 ;
    END
  END tk[3]
  PIN tk[40]
    DIRECTION OUTPUT ;
    USE SIGNAL ;
    PORT
      LAYER M5 ;
        RECT  55.584 0 55.608 0.084 ;
    END
  END tk[40]
  PIN tk[41]
    DIRECTION OUTPUT ;
    USE SIGNAL ;
    PORT
      LAYER M5 ;
        RECT  55.728 0 55.752 0.084 ;
    END
  END tk[41]
  PIN tk[42]
    DIRECTION OUTPUT ;
    USE SIGNAL ;
    PORT
      LAYER M5 ;
        RECT  55.872 0 55.896 0.084 ;
    END
  END tk[42]
  PIN tk[43]
    DIRECTION OUTPUT ;
    USE SIGNAL ;
    PORT
      LAYER M5 ;
        RECT  56.016 0 56.04 0.084 ;
    END
  END tk[43]
  PIN tk[44]
    DIRECTION OUTPUT ;
    USE SIGNAL ;
    PORT
      LAYER M5 ;
        RECT  56.16 0 56.184 0.084 ;
    END
  END tk[44]
  PIN tk[45]
    DIRECTION OUTPUT ;
    USE SIGNAL ;
    PORT
      LAYER M5 ;
        RECT  56.304 0 56.328 0.084 ;
    END
  END tk[45]
  PIN tk[46]
    DIRECTION OUTPUT ;
    USE SIGNAL ;
    PORT
      LAYER M5 ;
        RECT  56.448 0 56.472 0.084 ;
    END
  END tk[46]
  PIN tk[47]
    DIRECTION OUTPUT ;
    USE SIGNAL ;
    PORT
      LAYER M5 ;
        RECT  56.592 0 56.616 0.084 ;
    END
  END tk[47]
  PIN tk[48]
    DIRECTION OUTPUT ;
    USE SIGNAL ;
    PORT
      LAYER M5 ;
        RECT  56.736 0 56.76 0.084 ;
    END
  END tk[48]
  PIN tk[49]
    DIRECTION OUTPUT ;
    USE SIGNAL ;
    PORT
      LAYER M5 ;
        RECT  56.88 0 56.904 0.084 ;
    END
  END tk[49]
  PIN tk[4]
    DIRECTION OUTPUT ;
    USE SIGNAL ;
    PORT
      LAYER M5 ;
        RECT  50.4 0 50.424 0.084 ;
    END
  END tk[4]
  PIN tk[50]
    DIRECTION OUTPUT ;
    USE SIGNAL ;
    PORT
      LAYER M5 ;
        RECT  57.024 0 57.048 0.084 ;
    END
  END tk[50]
  PIN tk[51]
    DIRECTION OUTPUT ;
    USE SIGNAL ;
    PORT
      LAYER M5 ;
        RECT  43.344 0 43.368 0.084 ;
    END
  END tk[51]
  PIN tk[52]
    DIRECTION OUTPUT ;
    USE SIGNAL ;
    PORT
      LAYER M5 ;
        RECT  43.488 0 43.512 0.084 ;
    END
  END tk[52]
  PIN tk[53]
    DIRECTION OUTPUT ;
    USE SIGNAL ;
    PORT
      LAYER M5 ;
        RECT  43.632 0 43.656 0.084 ;
    END
  END tk[53]
  PIN tk[54]
    DIRECTION OUTPUT ;
    USE SIGNAL ;
    PORT
      LAYER M5 ;
        RECT  43.776 0 43.8 0.084 ;
    END
  END tk[54]
  PIN tk[55]
    DIRECTION OUTPUT ;
    USE SIGNAL ;
    PORT
      LAYER M5 ;
        RECT  43.92 0 43.944 0.084 ;
    END
  END tk[55]
  PIN tk[56]
    DIRECTION OUTPUT ;
    USE SIGNAL ;
    PORT
      LAYER M5 ;
        RECT  44.064 0 44.088 0.084 ;
    END
  END tk[56]
  PIN tk[57]
    DIRECTION OUTPUT ;
    USE SIGNAL ;
    PORT
      LAYER M5 ;
        RECT  44.208 0 44.232 0.084 ;
    END
  END tk[57]
  PIN tk[58]
    DIRECTION OUTPUT ;
    USE SIGNAL ;
    PORT
      LAYER M5 ;
        RECT  44.352 0 44.376 0.084 ;
    END
  END tk[58]
  PIN tk[59]
    DIRECTION OUTPUT ;
    USE SIGNAL ;
    PORT
      LAYER M5 ;
        RECT  44.496 0 44.52 0.084 ;
    END
  END tk[59]
  PIN tk[5]
    DIRECTION OUTPUT ;
    USE SIGNAL ;
    PORT
      LAYER M5 ;
        RECT  50.544 0 50.568 0.084 ;
    END
  END tk[5]
  PIN tk[60]
    DIRECTION OUTPUT ;
    USE SIGNAL ;
    PORT
      LAYER M5 ;
        RECT  44.64 0 44.664 0.084 ;
    END
  END tk[60]
  PIN tk[61]
    DIRECTION OUTPUT ;
    USE SIGNAL ;
    PORT
      LAYER M5 ;
        RECT  44.784 0 44.808 0.084 ;
    END
  END tk[61]
  PIN tk[62]
    DIRECTION OUTPUT ;
    USE SIGNAL ;
    PORT
      LAYER M5 ;
        RECT  44.928 0 44.952 0.084 ;
    END
  END tk[62]
  PIN tk[63]
    DIRECTION OUTPUT ;
    USE SIGNAL ;
    PORT
      LAYER M5 ;
        RECT  45.072 0 45.096 0.084 ;
    END
  END tk[63]
  PIN tk[64]
    DIRECTION OUTPUT ;
    USE SIGNAL ;
    PORT
      LAYER M5 ;
        RECT  45.216 0 45.24 0.084 ;
    END
  END tk[64]
  PIN tk[65]
    DIRECTION OUTPUT ;
    USE SIGNAL ;
    PORT
      LAYER M5 ;
        RECT  45.36 0 45.384 0.084 ;
    END
  END tk[65]
  PIN tk[66]
    DIRECTION OUTPUT ;
    USE SIGNAL ;
    PORT
      LAYER M5 ;
        RECT  45.504 0 45.528 0.084 ;
    END
  END tk[66]
  PIN tk[67]
    DIRECTION OUTPUT ;
    USE SIGNAL ;
    PORT
      LAYER M5 ;
        RECT  45.648 0 45.672 0.084 ;
    END
  END tk[67]
  PIN tk[68]
    DIRECTION OUTPUT ;
    USE SIGNAL ;
    PORT
      LAYER M5 ;
        RECT  45.792 0 45.816 0.084 ;
    END
  END tk[68]
  PIN tk[69]
    DIRECTION OUTPUT ;
    USE SIGNAL ;
    PORT
      LAYER M5 ;
        RECT  45.936 0 45.96 0.084 ;
    END
  END tk[69]
  PIN tk[6]
    DIRECTION OUTPUT ;
    USE SIGNAL ;
    PORT
      LAYER M5 ;
        RECT  50.688 0 50.712 0.084 ;
    END
  END tk[6]
  PIN tk[70]
    DIRECTION OUTPUT ;
    USE SIGNAL ;
    PORT
      LAYER M5 ;
        RECT  46.08 0 46.104 0.084 ;
    END
  END tk[70]
  PIN tk[71]
    DIRECTION OUTPUT ;
    USE SIGNAL ;
    PORT
      LAYER M5 ;
        RECT  46.224 0 46.248 0.084 ;
    END
  END tk[71]
  PIN tk[72]
    DIRECTION OUTPUT ;
    USE SIGNAL ;
    PORT
      LAYER M5 ;
        RECT  46.368 0 46.392 0.084 ;
    END
  END tk[72]
  PIN tk[73]
    DIRECTION OUTPUT ;
    USE SIGNAL ;
    PORT
      LAYER M5 ;
        RECT  46.512 0 46.536 0.084 ;
    END
  END tk[73]
  PIN tk[74]
    DIRECTION OUTPUT ;
    USE SIGNAL ;
    PORT
      LAYER M5 ;
        RECT  46.656 0 46.68 0.084 ;
    END
  END tk[74]
  PIN tk[75]
    DIRECTION OUTPUT ;
    USE SIGNAL ;
    PORT
      LAYER M5 ;
        RECT  46.8 0 46.824 0.084 ;
    END
  END tk[75]
  PIN tk[76]
    DIRECTION OUTPUT ;
    USE SIGNAL ;
    PORT
      LAYER M5 ;
        RECT  46.944 0 46.968 0.084 ;
    END
  END tk[76]
  PIN tk[77]
    DIRECTION OUTPUT ;
    USE SIGNAL ;
    PORT
      LAYER M5 ;
        RECT  47.088 0 47.112 0.084 ;
    END
  END tk[77]
  PIN tk[78]
    DIRECTION OUTPUT ;
    USE SIGNAL ;
    PORT
      LAYER M5 ;
        RECT  47.232 0 47.256 0.084 ;
    END
  END tk[78]
  PIN tk[79]
    DIRECTION OUTPUT ;
    USE SIGNAL ;
    PORT
      LAYER M5 ;
        RECT  47.376 0 47.4 0.084 ;
    END
  END tk[79]
  PIN tk[7]
    DIRECTION OUTPUT ;
    USE SIGNAL ;
    PORT
      LAYER M5 ;
        RECT  50.832 0 50.856 0.084 ;
    END
  END tk[7]
  PIN tk[80]
    DIRECTION OUTPUT ;
    USE SIGNAL ;
    PORT
      LAYER M5 ;
        RECT  47.52 0 47.544 0.084 ;
    END
  END tk[80]
  PIN tk[81]
    DIRECTION OUTPUT ;
    USE SIGNAL ;
    PORT
      LAYER M5 ;
        RECT  47.664 0 47.688 0.084 ;
    END
  END tk[81]
  PIN tk[82]
    DIRECTION OUTPUT ;
    USE SIGNAL ;
    PORT
      LAYER M5 ;
        RECT  47.808 0 47.832 0.084 ;
    END
  END tk[82]
  PIN tk[83]
    DIRECTION OUTPUT ;
    USE SIGNAL ;
    PORT
      LAYER M5 ;
        RECT  34.128 0 34.152 0.084 ;
    END
  END tk[83]
  PIN tk[84]
    DIRECTION OUTPUT ;
    USE SIGNAL ;
    PORT
      LAYER M5 ;
        RECT  34.272 0 34.296 0.084 ;
    END
  END tk[84]
  PIN tk[85]
    DIRECTION OUTPUT ;
    USE SIGNAL ;
    PORT
      LAYER M5 ;
        RECT  34.416 0 34.44 0.084 ;
    END
  END tk[85]
  PIN tk[86]
    DIRECTION OUTPUT ;
    USE SIGNAL ;
    PORT
      LAYER M5 ;
        RECT  34.56 0 34.584 0.084 ;
    END
  END tk[86]
  PIN tk[87]
    DIRECTION OUTPUT ;
    USE SIGNAL ;
    PORT
      LAYER M5 ;
        RECT  34.704 0 34.728 0.084 ;
    END
  END tk[87]
  PIN tk[88]
    DIRECTION OUTPUT ;
    USE SIGNAL ;
    PORT
      LAYER M5 ;
        RECT  34.848 0 34.872 0.084 ;
    END
  END tk[88]
  PIN tk[89]
    DIRECTION OUTPUT ;
    USE SIGNAL ;
    PORT
      LAYER M5 ;
        RECT  34.992 0 35.016 0.084 ;
    END
  END tk[89]
  PIN tk[8]
    DIRECTION OUTPUT ;
    USE SIGNAL ;
    PORT
      LAYER M5 ;
        RECT  50.976 0 51 0.084 ;
    END
  END tk[8]
  PIN tk[90]
    DIRECTION OUTPUT ;
    USE SIGNAL ;
    PORT
      LAYER M5 ;
        RECT  35.136 0 35.16 0.084 ;
    END
  END tk[90]
  PIN tk[91]
    DIRECTION OUTPUT ;
    USE SIGNAL ;
    PORT
      LAYER M5 ;
        RECT  35.28 0 35.304 0.084 ;
    END
  END tk[91]
  PIN tk[92]
    DIRECTION OUTPUT ;
    USE SIGNAL ;
    PORT
      LAYER M5 ;
        RECT  35.424 0 35.448 0.084 ;
    END
  END tk[92]
  PIN tk[9]
    DIRECTION OUTPUT ;
    USE SIGNAL ;
    PORT
      LAYER M5 ;
        RECT  51.12 0 51.144 0.084 ;
    END
  END tk[9]
  PIN x_cls[0]
    DIRECTION OUTPUT ;
    USE SIGNAL ;
    PORT
      LAYER M5 ;
        RECT  11.664 29.076 11.688 29.16 ;
    END
  END x_cls[0]
  PIN x_cls[1]
    DIRECTION OUTPUT ;
    USE SIGNAL ;
    PORT
      LAYER M5 ;
        RECT  11.808 29.076 11.832 29.16 ;
    END
  END x_cls[1]
  PIN x_cls[2]
    DIRECTION OUTPUT ;
    USE SIGNAL ;
    PORT
      LAYER M5 ;
        RECT  11.952 29.076 11.976 29.16 ;
    END
  END x_cls[2]
  PIN x_v
    DIRECTION OUTPUT ;
    USE SIGNAL ;
    PORT
      LAYER M5 ;
        RECT  12.096 29.076 12.12 29.16 ;
    END
  END x_v
  PIN VDD
    DIRECTION INOUT ;
    USE POWER ;
    PORT
      LAYER M5 ;
        RECT  61.992 2.151 62.112 27.009 ;
        RECT  59.292 2.151 59.412 27.009 ;
        RECT  56.592 2.151 56.712 27.009 ;
        RECT  53.892 2.151 54.012 27.009 ;
        RECT  51.192 2.151 51.312 27.009 ;
        RECT  48.492 2.151 48.612 27.009 ;
        RECT  45.792 2.151 45.912 27.009 ;
        RECT  43.092 2.151 43.212 27.009 ;
        RECT  40.392 2.151 40.512 27.009 ;
        RECT  37.692 2.151 37.812 27.009 ;
        RECT  34.992 2.151 35.112 27.009 ;
        RECT  32.292 2.151 32.412 27.009 ;
        RECT  29.592 2.151 29.712 27.009 ;
        RECT  26.892 2.151 27.012 27.009 ;
        RECT  24.192 2.151 24.312 27.009 ;
        RECT  21.492 2.151 21.612 27.009 ;
        RECT  18.792 2.151 18.912 27.009 ;
        RECT  16.092 2.151 16.212 27.009 ;
        RECT  13.392 2.151 13.512 27.009 ;
        RECT  10.692 2.151 10.812 27.009 ;
        RECT  7.992 2.151 8.112 27.009 ;
        RECT  5.292 2.151 5.412 27.009 ;
        RECT  2.592 2.151 2.712 27.009 ;
    END
  END VDD
  PIN VSS
    DIRECTION INOUT ;
    USE GROUND ;
    PORT
      LAYER M5 ;
        RECT  61.8 2.137 61.92 27.023 ;
        RECT  59.1 2.137 59.22 27.023 ;
        RECT  56.4 2.137 56.52 27.023 ;
        RECT  53.7 2.137 53.82 27.023 ;
        RECT  51 2.137 51.12 27.023 ;
        RECT  48.3 2.137 48.42 27.023 ;
        RECT  45.6 2.137 45.72 27.023 ;
        RECT  42.9 2.137 43.02 27.023 ;
        RECT  40.2 2.137 40.32 27.023 ;
        RECT  37.5 2.137 37.62 27.023 ;
        RECT  34.8 2.137 34.92 27.023 ;
        RECT  32.1 2.137 32.22 27.023 ;
        RECT  29.4 2.137 29.52 27.023 ;
        RECT  26.7 2.137 26.82 27.023 ;
        RECT  24 2.137 24.12 27.023 ;
        RECT  21.3 2.137 21.42 27.023 ;
        RECT  18.6 2.137 18.72 27.023 ;
        RECT  15.9 2.137 16.02 27.023 ;
        RECT  13.2 2.137 13.32 27.023 ;
        RECT  10.5 2.137 10.62 27.023 ;
        RECT  7.8 2.137 7.92 27.023 ;
        RECT  5.1 2.137 5.22 27.023 ;
        RECT  2.4 2.137 2.52 27.023 ;
    END
  END VSS
  # OT_OBS_CLOSED layer=M5 d_um=1.536 added=189
  OBS
    LAYER RVTN ;
     RECT  2.16 2.16 62.64 2.295 ;
     RECT  2.16 2.565 62.64 2.835 ;
     RECT  2.16 3.105 62.64 3.375 ;
     RECT  2.16 3.645 62.64 3.915 ;
     RECT  2.16 4.185 62.64 4.455 ;
     RECT  2.16 4.725 62.64 4.995 ;
     RECT  2.16 5.265 62.64 5.535 ;
     RECT  2.16 5.805 62.64 6.075 ;
     RECT  2.16 6.345 62.64 6.615 ;
     RECT  2.16 6.885 62.64 7.155 ;
     RECT  2.16 7.425 62.64 7.695 ;
     RECT  2.16 7.965 62.64 8.235 ;
     RECT  2.16 8.505 62.64 8.775 ;
     RECT  2.16 9.045 62.64 9.315 ;
     RECT  2.16 9.585 62.64 9.855 ;
     RECT  2.16 10.125 62.64 10.395 ;
     RECT  2.16 10.665 62.64 10.935 ;
     RECT  2.16 11.205 62.64 11.475 ;
     RECT  2.16 11.745 62.64 12.015 ;
     RECT  2.16 12.285 62.64 12.555 ;
     RECT  2.16 12.825 62.64 13.095 ;
     RECT  2.16 13.365 62.64 13.635 ;
     RECT  2.16 13.905 62.64 14.175 ;
     RECT  2.16 14.445 62.64 14.715 ;
     RECT  2.16 14.985 62.64 15.255 ;
     RECT  2.16 15.525 62.64 15.795 ;
     RECT  2.16 16.065 62.64 16.335 ;
     RECT  2.16 16.605 62.64 16.875 ;
     RECT  2.16 17.145 62.64 17.415 ;
     RECT  2.16 17.685 62.64 17.955 ;
     RECT  2.16 18.225 62.64 18.495 ;
     RECT  2.16 18.765 62.64 19.035 ;
     RECT  2.16 19.305 62.64 19.575 ;
     RECT  2.16 19.845 62.64 20.115 ;
     RECT  2.16 20.385 62.64 20.655 ;
     RECT  2.16 20.925 62.64 21.195 ;
     RECT  2.16 21.465 62.64 21.735 ;
     RECT  2.16 22.005 62.64 22.275 ;
     RECT  2.16 22.545 62.64 22.815 ;
     RECT  2.16 23.085 62.64 23.355 ;
     RECT  2.16 23.625 62.64 23.895 ;
     RECT  2.16 24.165 62.64 24.435 ;
     RECT  2.16 24.705 62.64 24.975 ;
     RECT  2.16 25.245 62.64 25.515 ;
     RECT  2.16 25.785 62.64 26.055 ;
     RECT  2.16 26.325 62.64 26.595 ;
     RECT  2.16 26.865 62.64 27 ;
    LAYER RVTP ;
     RECT  2.16 2.295 62.64 2.565 ;
     RECT  2.16 2.835 62.64 3.105 ;
     RECT  2.16 3.375 62.64 3.645 ;
     RECT  2.16 3.915 62.64 4.185 ;
     RECT  2.16 4.455 62.64 4.725 ;
     RECT  2.16 4.995 62.64 5.265 ;
     RECT  2.16 5.535 62.64 5.805 ;
     RECT  2.16 6.075 62.64 6.345 ;
     RECT  2.16 6.615 62.64 6.885 ;
     RECT  2.16 7.155 62.64 7.425 ;
     RECT  2.16 7.695 62.64 7.965 ;
     RECT  2.16 8.235 62.64 8.505 ;
     RECT  2.16 8.775 62.64 9.045 ;
     RECT  2.16 9.315 62.64 9.585 ;
     RECT  2.16 9.855 62.64 10.125 ;
     RECT  2.16 10.395 62.64 10.665 ;
     RECT  2.16 10.935 62.64 11.205 ;
     RECT  2.16 11.475 62.64 11.745 ;
     RECT  2.16 12.015 62.64 12.285 ;
     RECT  2.16 12.555 62.64 12.825 ;
     RECT  2.16 13.095 62.64 13.365 ;
     RECT  2.16 13.635 62.64 13.905 ;
     RECT  2.16 14.175 62.64 14.445 ;
     RECT  2.16 14.715 62.64 14.985 ;
     RECT  2.16 15.255 62.64 15.525 ;
     RECT  2.16 15.795 62.64 16.065 ;
     RECT  2.16 16.335 62.64 16.605 ;
     RECT  2.16 16.875 62.64 17.145 ;
     RECT  2.16 17.415 62.64 17.685 ;
     RECT  2.16 17.955 62.64 18.225 ;
     RECT  2.16 18.495 62.64 18.765 ;
     RECT  2.16 19.035 62.64 19.305 ;
     RECT  2.16 19.575 62.64 19.845 ;
     RECT  2.16 20.115 62.64 20.385 ;
     RECT  2.16 20.655 62.64 20.925 ;
     RECT  2.16 21.195 62.64 21.465 ;
     RECT  2.16 21.735 62.64 22.005 ;
     RECT  2.16 22.275 62.64 22.545 ;
     RECT  2.16 22.815 62.64 23.085 ;
     RECT  2.16 23.355 62.64 23.625 ;
     RECT  2.16 23.895 62.64 24.165 ;
     RECT  2.16 24.435 62.64 24.705 ;
     RECT  2.16 24.975 62.64 25.245 ;
     RECT  2.16 25.515 62.64 25.785 ;
     RECT  2.16 26.055 62.64 26.325 ;
     RECT  2.16 26.595 62.64 26.865 ;
    LAYER M1 ;
     RECT  2.16 2.151 62.64 27.009 ;
    LAYER M2 ;
     RECT  0.103 10.44 0.203 10.539 ;
     RECT  0.103 4.5 0.239 4.518 ;
     RECT  0.103 8.946 0.239 8.964 ;
     RECT  0.499 5.04 0.535 5.058 ;
     RECT  0.211 5.814 0.535 5.832 ;
     RECT  0.203 10.44 0.535 10.458 ;
     RECT  0.535 10.098 1.111 10.458 ;
     RECT  1.723 2.232 1.759 2.25 ;
     RECT  1.723 15.066 1.759 15.084 ;
     RECT  0.535 5.04 1.975 5.832 ;
     RECT  1.759 2.232 2.16 2.826 ;
     RECT  1.975 4.806 2.16 5.832 ;
     RECT  0.535 6.786 2.16 6.804 ;
     RECT  1.111 10.098 2.16 10.764 ;
     RECT  0.103 13.374 2.16 13.392 ;
     RECT  0.103 14.22 2.16 14.238 ;
     RECT  1.759 15.066 2.16 15.552 ;
     RECT  2.16 2.151 3.847 27.009 ;
     RECT  3.847 2.106 9.311 27.009 ;
     RECT  9.311 2.151 14.827 27.009 ;
     RECT  14.827 2.106 19.535 27.009 ;
     RECT  19.535 2.151 26.851 27.009 ;
     RECT  26.851 2.106 27.715 27.009 ;
     RECT  27.715 2.07 32.099 27.009 ;
     RECT  41.035 1.152 41.135 1.242 ;
     RECT  41.135 1.152 41.279 1.17 ;
     RECT  44.851 1.152 44.951 1.17 ;
     RECT  32.099 2.151 46.399 27.009 ;
     RECT  46.399 2.106 48.551 27.009 ;
     RECT  49.063 1.152 49.199 1.17 ;
     RECT  49.927 1.152 50.063 1.17 ;
     RECT  48.551 2.151 51.331 27.009 ;
     RECT  51.331 2.106 52.411 27.009 ;
     RECT  52.411 2.034 52.871 27.009 ;
     RECT  54.931 1.152 55.139 1.17 ;
     RECT  52.871 2.151 56.083 27.009 ;
     RECT  56.047 1.152 56.183 1.17 ;
     RECT  56.083 2.106 57.263 27.009 ;
     RECT  57.263 2.151 59.431 27.009 ;
     RECT  59.431 2.106 60.503 27.009 ;
     RECT  60.503 2.151 62.64 27.009 ;
     RECT  62.64 17.856 62.699 19.062 ;
     RECT  62.64 4.536 62.735 6.174 ;
     RECT  62.699 17.856 63.203 18.954 ;
     RECT  62.735 4.734 63.275 6.174 ;
     RECT  62.64 8.136 63.275 16.974 ;
     RECT  63.203 17.856 63.275 18.864 ;
     RECT  63.275 4.734 63.311 6.102 ;
     RECT  63.275 8.136 63.779 12.744 ;
     RECT  63.311 6.084 63.851 6.102 ;
     RECT  62.64 7.326 63.851 7.344 ;
     RECT  63.779 8.136 63.851 12.654 ;
     RECT  63.275 13.806 63.851 16.974 ;
     RECT  63.311 4.734 63.887 4.752 ;
     RECT  63.851 8.784 63.887 12.654 ;
     RECT  63.851 14.22 63.887 14.238 ;
     RECT  63.851 16.614 64.607 16.974 ;
     RECT  63.887 12.6 64.643 12.654 ;
     RECT  63.275 17.964 64.643 18.864 ;
     RECT  64.643 12.6 64.679 12.618 ;
     RECT  63.851 15.03 64.679 15.714 ;
     RECT  64.607 16.614 64.679 16.938 ;
     RECT  64.643 17.964 64.679 18.324 ;
     RECT  63.887 8.856 64.715 9.414 ;
     RECT  63.887 10.638 64.715 11.844 ;
     RECT  64.679 15.696 64.715 15.714 ;
     RECT  64.679 17.964 64.715 17.982 ;
     RECT  64.651 13.842 64.787 13.86 ;
     RECT  64.679 16.92 64.787 16.938 ;
    LAYER M3 ;
     RECT  58.284 0.043 58.302 0.091 ;
     RECT  22.212 0.091 22.23 0.139 ;
     RECT  41.04 0.091 41.058 0.139 ;
     RECT  54.432 0.091 55.134 0.139 ;
     RECT  57.168 0.091 57.186 0.139 ;
     RECT  48.456 0.091 48.474 0.187 ;
     RECT  60.624 0.043 60.642 0.221 ;
     RECT  45.54 0.091 45.558 0.523 ;
     RECT  51.516 0.091 53.262 0.523 ;
     RECT  54.432 0.139 55.386 0.523 ;
     RECT  56.124 0.475 56.142 0.523 ;
     RECT  57.024 0.139 57.186 0.523 ;
     RECT  21.708 0.139 22.23 0.571 ;
     RECT  44.928 0.523 45.558 0.571 ;
     RECT  46.656 0.091 46.674 0.571 ;
     RECT  50.04 0.523 50.058 0.571 ;
     RECT  51.156 0.523 53.262 0.571 ;
     RECT  1.728 0.859 1.746 1.003 ;
     RECT  34.272 0.523 34.29 1.099 ;
     RECT  35.208 0.571 35.226 1.099 ;
     RECT  1.728 1.003 1.782 1.147 ;
     RECT  41.04 0.139 41.13 1.147 ;
     RECT  44.928 0.571 46.674 1.147 ;
     RECT  48.456 0.187 49.086 1.147 ;
     RECT  50.04 0.571 53.262 1.147 ;
     RECT  54.432 0.523 57.186 1.147 ;
     RECT  44.856 1.147 46.89 1.195 ;
     RECT  21.708 0.571 22.338 1.627 ;
     RECT  7.956 1.435 7.974 1.723 ;
     RECT  19.404 1.147 19.422 1.723 ;
     RECT  21.24 1.627 22.338 1.723 ;
     RECT  34.272 1.099 35.226 1.723 ;
     RECT  39.564 1.675 39.582 1.723 ;
     RECT  41.04 1.147 41.274 1.723 ;
     RECT  43.776 1.099 43.794 1.723 ;
     RECT  44.856 1.195 47.106 1.723 ;
     RECT  48.456 1.147 53.262 1.723 ;
     RECT  54.216 1.147 57.186 1.723 ;
     RECT  58.284 0.091 58.518 1.723 ;
     RECT  60.48 0.571 60.498 1.723 ;
     RECT  18.936 1.723 20.178 1.771 ;
     RECT  20.916 1.723 23.706 1.771 ;
     RECT  40.932 1.723 42.606 1.771 ;
     RECT  43.776 1.723 53.262 1.771 ;
     RECT  54 1.723 57.186 1.771 ;
     RECT  40.932 1.771 42.75 1.819 ;
     RECT  43.776 1.771 57.186 1.819 ;
     RECT  4.644 1.579 4.662 2.011 ;
     RECT  1.728 1.147 2.322 2.059 ;
     RECT  3.132 1.291 3.15 2.059 ;
     RECT  7.416 1.723 7.974 2.059 ;
     RECT  1.728 2.059 3.15 2.101 ;
     RECT  32.076 2.065 32.094 2.101 ;
     RECT  40.932 1.819 57.186 2.101 ;
     RECT  4.644 2.011 5.094 2.143 ;
     RECT  18.936 1.771 23.922 2.143 ;
     RECT  26.856 2.101 26.874 2.143 ;
     RECT  31.968 2.101 32.094 2.143 ;
     RECT  38.52 1.723 39.87 2.143 ;
     RECT  40.932 2.101 57.258 2.143 ;
     RECT  60.48 1.723 61.398 2.143 ;
     RECT  62.28 1.723 62.298 2.143 ;
     RECT  1.728 2.101 3.87 2.191 ;
     RECT  4.644 2.143 5.205 2.191 ;
     RECT  7.236 2.059 7.974 2.191 ;
     RECT  29.415 2.143 29.505 2.191 ;
     RECT  34.272 1.723 35.262 2.191 ;
     RECT  36.612 1.771 36.63 2.191 ;
     RECT  38.52 2.143 57.258 2.191 ;
     RECT  58.284 1.723 59.526 2.191 ;
     RECT  60.48 2.143 62.298 2.191 ;
     RECT  14.832 2.101 14.85 2.219 ;
     RECT  26.715 2.143 26.874 2.227 ;
     RECT  27.72 2.065 27.738 2.227 ;
     RECT  1.728 2.191 5.67 2.255 ;
     RECT  31.968 2.143 32.205 2.263 ;
     RECT  1.764 2.255 5.67 2.299 ;
     RECT  29.34 2.191 30.186 2.299 ;
     RECT  1.764 2.299 6.102 2.335 ;
     RECT  6.876 2.191 7.974 2.335 ;
     RECT  31.86 2.263 32.205 2.335 ;
     RECT  37.515 2.143 37.605 2.335 ;
     RECT  38.52 2.191 62.334 2.335 ;
     RECT  18.615 2.143 24.105 2.371 ;
     RECT  26.715 2.227 27.738 2.371 ;
     RECT  29.196 2.299 30.69 2.371 ;
     RECT  10.515 2.143 10.605 2.413 ;
     RECT  13.215 2.143 13.305 2.413 ;
     RECT  15.915 2.143 16.005 2.413 ;
     RECT  33.876 2.191 36.63 2.461 ;
     RECT  18.615 2.371 25.11 2.497 ;
     RECT  17.208 2.497 17.226 2.533 ;
     RECT  18 2.497 25.11 2.533 ;
     RECT  26.352 2.371 30.69 2.533 ;
     RECT  26.172 2.533 30.69 2.539 ;
     RECT  31.5 2.335 33.03 2.539 ;
     RECT  1.764 2.335 8.19 2.587 ;
     RECT  9.288 2.101 9.306 2.605 ;
     RECT  15.915 2.413 16.197 2.605 ;
     RECT  26.172 2.539 33.03 2.605 ;
     RECT  33.804 2.461 36.63 2.605 ;
     RECT  37.515 2.335 62.334 2.605 ;
     RECT  10.515 2.413 10.797 2.641 ;
     RECT  15.915 2.605 16.254 2.641 ;
     RECT  17.208 2.533 25.11 2.641 ;
     RECT  26.028 2.605 33.03 2.641 ;
     RECT  33.804 2.605 62.334 2.641 ;
     RECT  13.215 2.413 13.497 2.731 ;
     RECT  15.588 2.641 16.434 2.731 ;
     RECT  17.208 2.641 33.03 2.731 ;
     RECT  15.588 2.731 33.03 2.803 ;
     RECT  15.408 2.803 33.03 2.861 ;
     RECT  1.764 2.587 8.226 2.911 ;
     RECT  9.288 2.605 9.414 2.911 ;
     RECT  15.66 2.861 33.03 2.911 ;
     RECT  33.804 2.641 62.478 2.911 ;
     RECT  1.764 2.911 8.478 3.019 ;
     RECT  1.728 3.019 8.478 3.109 ;
     RECT  9.252 2.911 9.414 3.109 ;
     RECT  10.152 2.641 10.797 3.109 ;
     RECT  12.816 2.731 13.497 3.181 ;
     RECT  15.66 2.911 62.478 3.181 ;
     RECT  15.66 3.181 62.514 3.371 ;
     RECT  12.456 3.181 13.698 3.379 ;
     RECT  28.584 3.371 62.514 3.407 ;
     RECT  10.152 3.109 10.854 3.541 ;
     RECT  29.016 3.407 62.514 3.569 ;
     RECT  10.152 3.541 10.998 3.577 ;
     RECT  12.384 3.379 13.698 3.577 ;
     RECT  10.152 3.577 13.698 3.685 ;
     RECT  14.832 3.541 14.85 3.811 ;
     RECT  15.66 3.371 27.81 3.811 ;
     RECT  29.088 3.569 62.514 3.983 ;
     RECT  1.728 3.109 9.414 3.991 ;
     RECT  10.152 3.685 14.022 3.991 ;
     RECT  1.728 3.991 14.022 4.117 ;
     RECT  14.832 3.811 27.81 4.117 ;
     RECT  0.144 3.739 0.162 4.459 ;
     RECT  0.108 4.459 0.162 4.495 ;
     RECT  0.108 4.495 0.234 4.523 ;
     RECT  33.804 3.983 62.514 4.531 ;
     RECT  1.728 4.117 27.81 4.555 ;
     RECT  29.088 3.983 33.03 4.555 ;
     RECT  1.728 4.555 33.03 4.963 ;
     RECT  33.804 4.531 62.73 4.963 ;
     RECT  1.728 4.963 62.73 4.991 ;
     RECT  0.144 4.523 0.234 5.021 ;
     RECT  0.216 5.021 0.234 5.035 ;
     RECT  1.728 4.991 28.278 5.063 ;
     RECT  1.728 5.063 27.99 5.099 ;
     RECT  29.016 4.991 62.73 5.189 ;
     RECT  0.216 5.035 0.522 5.269 ;
     RECT  33.876 5.189 62.73 5.305 ;
     RECT  63.864 4.729 63.882 5.305 ;
     RECT  1.764 5.099 27.99 5.369 ;
     RECT  29.016 5.189 32.994 5.369 ;
     RECT  2.232 5.369 27.99 5.495 ;
     RECT  29.016 5.369 32.922 5.567 ;
     RECT  33.876 5.305 63.882 5.645 ;
     RECT  2.268 5.495 27.99 5.885 ;
     RECT  2.268 5.885 27.918 6.107 ;
     RECT  2.304 6.107 27.918 6.269 ;
     RECT  33.876 5.645 62.514 6.269 ;
     RECT  29.016 5.567 32.67 6.349 ;
     RECT  33.876 6.269 62.478 6.377 ;
     RECT  0.216 5.269 0.558 6.379 ;
     RECT  33.876 6.377 62.406 6.421 ;
     RECT  28.8 6.349 32.67 6.547 ;
     RECT  33.624 6.421 62.406 6.547 ;
     RECT  0.144 6.379 1.17 6.653 ;
     RECT  63.252 5.645 63.882 6.653 ;
     RECT  28.8 6.547 62.406 6.691 ;
     RECT  0.144 6.653 0.558 6.749 ;
     RECT  2.34 6.269 27.918 6.781 ;
     RECT  28.764 6.691 62.406 6.781 ;
     RECT  64.62 6.667 64.638 6.797 ;
     RECT  2.34 6.781 62.406 7.051 ;
     RECT  0.54 6.749 0.558 7.085 ;
     RECT  63.252 6.653 63.846 7.373 ;
     RECT  0.324 7.483 0.342 7.661 ;
     RECT  2.304 7.051 62.406 7.889 ;
     RECT  63.792 7.373 63.846 8.347 ;
     RECT  2.304 7.889 39.294 8.429 ;
     RECT  40.176 7.889 62.262 8.671 ;
     RECT  63.252 8.347 63.846 8.779 ;
     RECT  33.984 8.429 39.294 8.851 ;
     RECT  40.176 8.671 62.442 8.851 ;
     RECT  0.144 8.539 0.162 8.923 ;
     RECT  0.144 8.923 0.234 8.941 ;
     RECT  0.108 8.941 0.234 8.969 ;
     RECT  63.216 8.779 63.882 9.101 ;
     RECT  2.304 8.429 33.138 9.247 ;
     RECT  33.984 8.851 62.442 9.247 ;
     RECT  63.216 9.101 63.846 9.499 ;
     RECT  1.116 8.059 1.134 9.547 ;
     RECT  2.304 9.247 62.442 9.625 ;
     RECT  63.18 9.499 63.846 9.625 ;
     RECT  2.304 9.625 63.846 9.677 ;
     RECT  2.304 9.677 62.442 9.815 ;
     RECT  1.116 9.547 1.17 9.917 ;
     RECT  63.18 9.677 63.846 9.931 ;
     RECT  2.304 9.815 62.298 10.085 ;
     RECT  0.108 8.969 0.198 10.093 ;
     RECT  1.116 9.917 1.134 10.093 ;
     RECT  63.18 9.931 63.882 10.121 ;
     RECT  63.18 10.121 63.234 10.157 ;
     RECT  64.692 8.635 64.71 10.219 ;
     RECT  63.18 10.157 63.198 10.229 ;
     RECT  44.136 10.085 62.298 10.319 ;
     RECT  64.656 10.219 64.71 10.363 ;
     RECT  64.62 10.363 64.71 10.507 ;
     RECT  44.244 10.319 62.298 10.589 ;
     RECT  0.108 10.093 1.134 10.769 ;
     RECT  2.304 10.085 43.398 10.987 ;
     RECT  2.304 10.987 43.47 11.101 ;
     RECT  2.268 11.101 43.47 11.129 ;
     RECT  64.512 10.507 64.71 11.237 ;
     RECT  23.796 11.129 43.47 11.273 ;
     RECT  44.244 10.589 62.154 11.371 ;
     RECT  0.108 10.769 0.558 11.405 ;
     RECT  23.832 11.273 43.47 11.479 ;
     RECT  44.244 11.371 62.19 11.479 ;
     RECT  63.252 11.083 63.27 11.515 ;
     RECT  2.268 11.129 22.95 11.669 ;
     RECT  63.252 11.515 63.882 11.741 ;
     RECT  64.62 11.237 64.71 11.849 ;
     RECT  23.832 11.479 62.19 11.947 ;
     RECT  2.304 11.669 22.95 11.995 ;
     RECT  23.832 11.947 62.334 11.995 ;
     RECT  2.304 11.995 62.334 12.011 ;
     RECT  63.756 11.741 63.882 12.125 ;
     RECT  1.26 12.091 1.278 12.235 ;
     RECT  1.152 12.235 1.278 12.269 ;
     RECT  0.108 11.405 0.126 12.283 ;
     RECT  25.488 12.011 62.334 12.361 ;
     RECT  64.62 11.849 64.674 12.379 ;
     RECT  1.152 12.269 1.17 12.509 ;
     RECT  64.584 12.379 64.674 12.509 ;
     RECT  25.488 12.361 62.73 12.523 ;
     RECT  63.756 12.125 63.846 12.523 ;
     RECT  64.62 12.509 64.674 12.623 ;
     RECT  64.62 12.623 64.638 12.659 ;
     RECT  0.108 12.283 0.162 13.085 ;
     RECT  0.108 13.085 0.126 13.397 ;
     RECT  2.304 12.011 24.75 13.441 ;
     RECT  25.488 12.523 63.846 13.441 ;
     RECT  2.304 13.441 63.846 13.531 ;
     RECT  1.728 13.531 63.846 13.739 ;
     RECT  64.692 13.387 64.71 13.819 ;
     RECT  64.656 13.819 64.71 13.837 ;
     RECT  64.656 13.837 64.782 13.865 ;
     RECT  63.216 13.739 63.846 14.009 ;
     RECT  63.252 14.009 63.846 14.207 ;
     RECT  63.324 14.207 63.846 14.215 ;
     RECT  0.108 14.215 0.126 14.251 ;
     RECT  63.324 14.215 63.882 14.285 ;
     RECT  0.108 14.251 0.342 14.429 ;
     RECT  63.324 14.285 63.846 14.429 ;
     RECT  1.728 13.739 62.226 14.485 ;
     RECT  1.728 14.485 62.298 14.639 ;
     RECT  64.692 13.865 64.782 14.683 ;
     RECT  1.728 14.639 36.126 15.089 ;
     RECT  7.815 15.089 36.126 15.215 ;
     RECT  9.576 15.215 36.126 15.421 ;
     RECT  36.9 14.639 62.298 15.421 ;
     RECT  1.764 15.089 6.858 15.449 ;
     RECT  64.656 14.683 64.782 15.547 ;
     RECT  1.764 15.449 5.397 15.557 ;
     RECT  9.576 15.421 62.298 15.601 ;
     RECT  2.304 15.557 5.397 15.629 ;
     RECT  6.372 15.449 6.858 15.629 ;
     RECT  2.304 15.629 2.826 15.719 ;
     RECT  3.816 15.629 3.942 15.719 ;
     RECT  5.004 15.629 5.397 15.719 ;
     RECT  9.576 15.601 62.73 15.725 ;
     RECT  3.816 15.719 3.834 15.755 ;
     RECT  64.62 15.547 64.782 15.835 ;
     RECT  6.732 15.629 6.858 15.863 ;
     RECT  63.792 14.429 63.846 15.979 ;
     RECT  64.584 15.835 64.782 15.979 ;
     RECT  9.576 15.725 62.298 15.989 ;
     RECT  7.815 15.215 8.802 16.105 ;
     RECT  9.576 15.989 31.266 16.105 ;
     RECT  32.004 15.989 62.298 16.403 ;
     RECT  63.792 15.979 64.782 16.411 ;
     RECT  55.152 16.403 62.298 16.501 ;
     RECT  55.152 16.501 62.334 16.541 ;
     RECT  56.376 16.541 62.334 16.601 ;
     RECT  63.252 16.411 64.782 16.699 ;
     RECT  63.216 16.699 64.782 16.709 ;
     RECT  7.815 16.105 31.266 16.795 ;
     RECT  7.38 16.795 31.266 16.807 ;
     RECT  56.415 16.601 62.334 16.835 ;
     RECT  60.156 16.835 62.334 16.915 ;
     RECT  63.216 16.709 63.846 16.915 ;
     RECT  64.584 16.709 64.782 16.943 ;
     RECT  64.584 16.943 64.71 16.979 ;
     RECT  6.984 16.807 31.266 17.077 ;
     RECT  32.004 16.403 54.306 17.077 ;
     RECT  6.984 17.077 54.306 17.323 ;
     RECT  55.152 16.541 55.458 17.323 ;
     RECT  56.415 16.835 59.397 17.581 ;
     RECT  60.156 16.915 63.846 17.581 ;
     RECT  6.984 17.323 55.458 17.645 ;
     RECT  56.415 17.581 63.846 17.645 ;
     RECT  7.164 17.645 55.458 17.681 ;
     RECT  52.272 17.681 55.458 17.717 ;
     RECT  52.344 17.717 55.458 17.753 ;
     RECT  52.452 17.753 55.458 17.789 ;
     RECT  56.415 17.645 57.33 17.879 ;
     RECT  52.668 17.789 55.458 17.899 ;
     RECT  56.415 17.879 57.186 17.899 ;
     RECT  52.668 17.899 57.186 17.987 ;
     RECT  64.62 16.979 64.71 17.987 ;
     RECT  52.668 17.987 55.242 18.023 ;
     RECT  7.164 17.681 51.498 18.149 ;
     RECT  52.668 18.023 54.882 18.149 ;
     RECT  56.052 17.987 57.186 18.149 ;
     RECT  7.164 18.149 50.094 18.185 ;
     RECT  50.976 18.149 51.297 18.185 ;
     RECT  56.415 18.149 57.186 18.185 ;
     RECT  52.668 18.149 54.774 18.221 ;
     RECT  56.415 18.185 57.042 18.293 ;
     RECT  64.62 17.987 64.674 18.329 ;
     RECT  58.14 17.645 63.846 18.419 ;
     RECT  52.668 18.221 54.738 18.455 ;
     RECT  54.72 18.455 54.738 18.461 ;
     RECT  52.668 18.455 53.997 18.523 ;
     RECT  52.632 18.523 53.997 18.527 ;
     RECT  58.14 18.419 58.23 18.527 ;
     RECT  59.115 18.419 63.27 18.527 ;
     RECT  52.632 18.527 52.65 18.563 ;
     RECT  53.46 18.527 53.997 18.563 ;
     RECT  7.164 18.185 49.698 18.689 ;
     RECT  59.115 18.527 63.234 18.689 ;
     RECT  58.14 18.527 58.158 18.725 ;
     RECT  7.164 18.689 49.626 18.811 ;
     RECT  64.62 18.329 64.638 18.869 ;
     RECT  60.588 18.689 63.198 18.959 ;
     RECT  60.588 18.959 62.694 18.995 ;
     RECT  61.776 18.995 62.694 19.067 ;
     RECT  59.115 18.689 59.742 19.229 ;
     RECT  60.588 18.995 61.002 19.229 ;
     RECT  61.776 19.067 62.097 19.229 ;
     RECT  6.948 18.811 49.626 19.265 ;
     RECT  60.984 19.229 61.002 19.265 ;
     RECT  7.2 19.265 49.626 19.301 ;
     RECT  7.2 19.301 33.138 19.373 ;
     RECT  7.2 19.373 24.822 19.805 ;
     RECT  7.2 19.805 8.097 19.913 ;
     RECT  25.56 19.373 33.138 20.039 ;
     RECT  8.892 19.805 24.822 20.191 ;
     RECT  25.56 20.039 27.63 20.191 ;
     RECT  33.876 19.301 49.626 20.191 ;
     RECT  28.44 20.039 33.138 20.237 ;
     RECT  33.876 20.191 50.13 20.417 ;
     RECT  28.476 20.237 33.138 20.461 ;
     RECT  33.876 20.417 49.698 20.461 ;
     RECT  7.272 19.913 8.097 20.623 ;
     RECT  8.892 20.191 27.63 20.623 ;
     RECT  7.272 20.623 27.63 20.731 ;
     RECT  6.84 20.731 27.63 20.849 ;
     RECT  7.488 20.849 27.63 20.885 ;
     RECT  7.632 20.885 27.63 20.921 ;
     RECT  7.815 20.921 27.63 21.001 ;
     RECT  28.476 20.461 49.698 21.001 ;
     RECT  7.815 21.001 49.698 21.029 ;
     RECT  6.66 20.929 6.678 21.101 ;
     RECT  10.008 21.029 49.698 21.271 ;
     RECT  10.008 21.271 49.806 21.533 ;
     RECT  22.428 21.533 49.806 21.541 ;
     RECT  22.428 21.541 50.238 21.659 ;
     RECT  22.428 21.659 49.662 21.929 ;
     RECT  7.815 21.029 9.162 22.045 ;
     RECT  10.008 21.533 21.654 22.045 ;
     RECT  7.815 22.045 21.654 22.267 ;
     RECT  22.572 21.929 49.662 22.307 ;
     RECT  7.38 22.267 21.654 22.343 ;
     RECT  23.292 22.307 49.662 22.513 ;
     RECT  7.776 22.343 21.654 22.711 ;
     RECT  23.292 22.513 50.094 22.739 ;
     RECT  23.292 22.739 49.59 22.811 ;
     RECT  39.528 22.811 49.59 22.883 ;
     RECT  39.528 22.883 49.554 23.081 ;
     RECT  7.776 22.711 22.482 23.117 ;
     RECT  7.776 23.117 8.838 23.125 ;
     RECT  6.552 22.795 6.57 23.161 ;
     RECT  7.38 23.125 8.838 23.161 ;
     RECT  6.552 23.161 8.838 23.279 ;
     RECT  23.292 22.811 38.79 23.279 ;
     RECT  9.612 23.117 22.482 23.287 ;
     RECT  23.292 23.279 31.158 23.287 ;
     RECT  7.38 23.279 8.838 23.315 ;
     RECT  9.612 23.287 31.158 23.315 ;
     RECT  6.552 23.279 6.57 23.351 ;
     RECT  7.38 23.315 8.586 23.423 ;
     RECT  31.932 23.279 38.79 23.459 ;
     RECT  32.115 23.459 38.79 23.791 ;
     RECT  32.115 23.791 38.934 23.971 ;
     RECT  39.672 23.081 49.554 23.971 ;
     RECT  9.648 23.315 31.158 24.097 ;
     RECT  32.115 23.971 49.554 24.161 ;
     RECT  9.576 24.097 31.158 24.205 ;
     RECT  32.115 24.161 48.762 24.205 ;
     RECT  9.468 24.205 48.762 24.395 ;
     RECT  30.78 24.395 48.762 24.431 ;
     RECT  7.815 23.423 8.586 24.439 ;
     RECT  9.468 24.395 29.97 24.439 ;
     RECT  49.752 24.241 49.77 24.503 ;
     RECT  30.78 24.431 48.69 24.539 ;
     RECT  7.815 24.439 29.97 24.665 ;
     RECT  30.78 24.539 48.597 24.899 ;
     RECT  30.78 24.899 31.374 24.935 ;
     RECT  7.815 24.665 29.898 25.169 ;
     RECT  30.78 24.935 31.014 25.349 ;
     RECT  32.115 24.899 48.597 25.349 ;
     RECT  7.815 25.169 8.622 25.439 ;
     RECT  9.72 25.169 29.898 25.439 ;
     RECT  30.924 25.349 31.014 25.439 ;
     RECT  32.115 25.349 47.502 25.511 ;
     RECT  9.756 25.439 29.898 25.709 ;
     RECT  32.115 25.511 46.854 25.781 ;
     RECT  32.115 25.781 33.138 25.979 ;
     RECT  33.912 25.781 46.854 26.123 ;
     RECT  32.115 25.979 32.994 26.237 ;
     RECT  10.368 25.709 29.862 26.249 ;
     RECT  10.368 26.249 29.754 26.285 ;
     RECT  33.912 26.123 46.746 26.285 ;
     RECT  33.912 26.285 46.494 26.321 ;
     RECT  10.368 26.285 29.697 26.519 ;
     RECT  33.912 26.321 39.078 26.519 ;
     RECT  39.996 26.321 46.494 26.519 ;
     RECT  36.54 26.519 39.078 26.627 ;
     RECT  18.615 26.519 19.602 26.663 ;
     RECT  20.34 26.519 29.697 26.663 ;
     RECT  37.332 26.627 39.078 26.663 ;
     RECT  39.996 26.519 46.242 26.663 ;
     RECT  36.54 26.627 36.558 26.669 ;
     RECT  10.368 26.519 17.838 26.671 ;
     RECT  42.732 26.663 46.206 26.686 ;
     RECT  20.412 26.663 29.697 26.699 ;
     RECT  2.415 15.719 2.697 26.747 ;
     RECT  5.115 15.719 5.397 26.747 ;
     RECT  7.815 25.439 8.097 26.747 ;
     RECT  18.615 26.663 18.897 26.747 ;
     RECT  29.415 26.699 29.697 26.747 ;
     RECT  32.115 26.237 32.397 26.747 ;
     RECT  48.315 25.349 48.597 26.747 ;
     RECT  51.015 18.185 51.297 26.747 ;
     RECT  53.715 18.563 53.997 26.747 ;
     RECT  56.415 18.293 56.697 26.747 ;
     RECT  59.115 19.229 59.397 26.747 ;
     RECT  61.815 19.229 62.097 26.747 ;
     RECT  10.296 26.671 17.838 26.789 ;
     RECT  20.412 26.699 20.43 26.789 ;
     RECT  21.315 26.699 28.53 26.789 ;
     RECT  33.912 26.519 35.694 26.789 ;
     RECT  37.515 26.663 38.286 26.789 ;
     RECT  40.215 26.663 41.706 26.789 ;
     RECT  42.732 26.686 44.802 26.789 ;
     RECT  28.368 26.789 28.386 26.825 ;
     RECT  34.632 26.789 35.694 26.825 ;
     RECT  42.915 26.789 43.866 26.825 ;
     RECT  45.615 26.686 46.206 26.825 ;
     RECT  10.296 26.789 17.694 26.861 ;
     RECT  34.815 26.825 35.694 26.861 ;
     RECT  37.515 26.789 38.07 26.861 ;
     RECT  39.06 26.663 39.078 26.861 ;
     RECT  43.812 26.825 43.866 26.861 ;
     RECT  40.215 26.789 41.31 26.897 ;
     RECT  10.296 26.861 13.878 26.933 ;
     RECT  34.815 26.861 35.334 26.933 ;
     RECT  43.848 26.861 43.866 26.933 ;
     RECT  44.784 26.789 44.802 26.933 ;
     RECT  37.515 26.861 37.998 26.969 ;
     RECT  40.215 26.897 40.95 26.969 ;
     RECT  2.415 26.747 2.505 27.017 ;
     RECT  5.115 26.747 5.205 27.017 ;
     RECT  7.815 26.747 7.905 27.017 ;
     RECT  18.615 26.747 18.705 27.017 ;
     RECT  21.315 26.789 27.522 27.017 ;
     RECT  29.415 26.747 29.505 27.017 ;
     RECT  32.115 26.747 32.205 27.017 ;
     RECT  34.815 26.933 34.905 27.017 ;
     RECT  37.515 26.969 37.605 27.017 ;
     RECT  40.215 26.969 40.305 27.017 ;
     RECT  42.915 26.825 43.005 27.017 ;
     RECT  45.615 26.825 45.705 27.017 ;
     RECT  48.315 26.747 48.405 27.017 ;
     RECT  51.015 26.747 51.105 27.017 ;
     RECT  53.715 26.747 53.805 27.017 ;
     RECT  56.415 26.747 56.505 27.017 ;
     RECT  59.115 26.747 59.205 27.017 ;
     RECT  61.815 26.747 61.905 27.017 ;
     RECT  27.504 27.017 27.522 27.101 ;
     RECT  10.368 26.933 13.878 27.341 ;
     RECT  14.724 26.861 17.01 27.341 ;
     RECT  21.528 27.017 26.406 27.341 ;
     RECT  15.804 27.341 15.822 27.389 ;
     RECT  10.368 27.341 12.51 27.437 ;
     RECT  10.368 27.437 10.386 27.965 ;
     RECT  11.16 27.437 12.51 28.013 ;
     RECT  23.904 27.341 23.922 28.493 ;
     RECT  11.952 28.013 12.51 28.973 ;
     RECT  11.952 28.973 11.97 29.021 ;
     RECT  13.68 28.795 13.698 29.021 ;
     RECT  26.28 27.341 26.406 29.021 ;
     RECT  11.16 28.013 11.178 29.069 ;
     RECT  21.96 27.341 21.978 29.069 ;
     RECT  25.38 27.341 25.398 29.069 ;
     RECT  26.388 29.021 26.406 29.069 ;
    LAYER M4 ;
     RECT  0.084 0.864 0.133 0.888 ;
     RECT  0.06 0.888 0.133 1.008 ;
     RECT  0.084 1.008 0.133 1.032 ;
     RECT  0.06 1.032 0.133 1.152 ;
     RECT  0.084 1.152 0.133 1.176 ;
     RECT  0.06 1.176 0.133 1.296 ;
     RECT  0.084 1.296 0.133 1.32 ;
     RECT  0.06 1.32 0.133 1.44 ;
     RECT  0.084 1.44 0.133 1.464 ;
     RECT  0.06 1.464 0.133 1.584 ;
     RECT  0.084 1.584 0.133 1.608 ;
     RECT  0.06 1.608 0.133 1.728 ;
     RECT  0.084 1.728 0.133 1.752 ;
     RECT  0.06 1.752 0.133 1.872 ;
     RECT  0.084 1.872 0.133 1.896 ;
     RECT  0.06 1.896 0.133 2.016 ;
     RECT  0.084 2.016 0.133 2.04 ;
     RECT  0.06 2.04 0.133 2.16 ;
     RECT  0.084 2.16 0.133 2.184 ;
     RECT  0.06 2.184 0.133 2.304 ;
     RECT  0.084 2.304 0.133 2.328 ;
     RECT  0.06 2.328 0.133 2.448 ;
     RECT  0.084 2.448 0.133 2.472 ;
     RECT  0.06 2.472 0.133 2.592 ;
     RECT  0.084 2.592 0.133 2.616 ;
     RECT  0.06 2.616 0.133 2.736 ;
     RECT  0.084 2.736 0.133 2.76 ;
     RECT  0.06 2.76 0.133 2.88 ;
     RECT  0.084 2.88 0.133 2.904 ;
     RECT  0.06 2.904 0.133 3.024 ;
     RECT  0.084 3.024 0.133 3.048 ;
     RECT  0.06 3.048 0.133 3.168 ;
     RECT  0.084 3.168 0.133 3.192 ;
     RECT  0.06 3.192 0.133 3.312 ;
     RECT  0.084 3.312 0.133 3.336 ;
     RECT  0.06 3.336 0.133 3.456 ;
     RECT  0.084 3.456 0.133 3.48 ;
     RECT  0.06 3.48 0.133 3.6 ;
     RECT  0.084 3.6 0.133 3.624 ;
     RECT  0.06 3.624 0.133 3.744 ;
     RECT  0.084 3.744 0.133 3.768 ;
     RECT  0.06 3.768 0.133 3.888 ;
     RECT  0.084 3.888 0.133 3.912 ;
     RECT  0.06 3.912 0.133 4.032 ;
     RECT  0.084 4.032 0.133 4.056 ;
     RECT  0.06 4.056 0.133 4.176 ;
     RECT  0.084 4.176 0.133 4.2 ;
     RECT  0.06 4.2 0.133 4.32 ;
     RECT  0.084 4.32 0.133 4.344 ;
     RECT  0.06 4.344 0.133 4.464 ;
     RECT  0.084 4.464 0.133 4.488 ;
     RECT  0.06 4.488 0.133 4.608 ;
     RECT  0.084 4.608 0.133 4.632 ;
     RECT  0.06 4.632 0.133 4.752 ;
     RECT  0.084 4.752 0.133 4.776 ;
     RECT  0.06 4.776 0.133 4.896 ;
     RECT  0.084 4.896 0.133 4.92 ;
     RECT  0.06 4.92 0.133 5.04 ;
     RECT  0.084 5.04 0.133 5.064 ;
     RECT  0.06 5.064 0.133 5.184 ;
     RECT  0.084 5.184 0.133 5.208 ;
     RECT  0.06 5.208 0.133 5.328 ;
     RECT  0.084 5.328 0.133 5.352 ;
     RECT  0.06 5.352 0.133 5.472 ;
     RECT  0.084 5.472 0.133 5.496 ;
     RECT  0.06 5.496 0.133 5.616 ;
     RECT  0.084 5.616 0.133 5.64 ;
     RECT  0.06 5.64 0.133 5.76 ;
     RECT  0.084 5.76 0.133 5.784 ;
     RECT  0.06 5.784 0.133 5.904 ;
     RECT  0.084 5.904 0.133 5.928 ;
     RECT  0.06 5.928 0.133 6.048 ;
     RECT  0.084 6.048 0.133 6.072 ;
     RECT  0.06 6.072 0.133 6.192 ;
     RECT  0.084 6.192 0.133 6.216 ;
     RECT  0.06 6.216 0.133 6.336 ;
     RECT  0.084 6.336 0.133 6.36 ;
     RECT  0.06 6.36 0.133 6.48 ;
     RECT  0.084 6.48 0.133 6.504 ;
     RECT  0.06 6.504 0.133 6.624 ;
     RECT  0.084 6.624 0.133 6.648 ;
     RECT  0.06 6.648 0.133 6.768 ;
     RECT  0.084 6.768 0.133 6.792 ;
     RECT  0.06 6.792 0.133 6.912 ;
     RECT  0.084 6.912 0.133 6.936 ;
     RECT  0.06 6.936 0.133 7.056 ;
     RECT  0.084 7.056 0.133 7.08 ;
     RECT  0.06 7.08 0.133 7.2 ;
     RECT  0.084 7.2 0.133 7.224 ;
     RECT  0.06 7.224 0.133 7.344 ;
     RECT  0.084 7.344 0.133 7.368 ;
     RECT  0.06 7.368 0.133 7.488 ;
     RECT  0.084 7.488 0.133 7.512 ;
     RECT  0.06 7.512 0.133 7.632 ;
     RECT  0.084 7.632 0.133 7.656 ;
     RECT  0.06 7.656 0.133 7.776 ;
     RECT  0.084 7.776 0.133 7.8 ;
     RECT  0.06 7.8 0.133 7.92 ;
     RECT  0.084 7.92 0.133 7.944 ;
     RECT  0.06 7.944 0.133 8.064 ;
     RECT  0.084 8.064 0.133 8.088 ;
     RECT  0.06 8.088 0.133 8.208 ;
     RECT  0.084 8.208 0.133 8.232 ;
     RECT  0.06 8.232 0.133 8.352 ;
     RECT  0.084 8.352 0.133 8.376 ;
     RECT  0.06 8.376 0.133 8.496 ;
     RECT  0.084 8.496 0.133 8.52 ;
     RECT  0.06 8.52 0.133 8.64 ;
     RECT  0.084 8.64 0.133 8.664 ;
     RECT  0.06 8.664 0.133 8.784 ;
     RECT  0.084 8.784 0.133 8.808 ;
     RECT  0.06 8.808 0.133 8.928 ;
     RECT  0.084 8.928 0.133 8.952 ;
     RECT  0.06 8.952 0.133 9.072 ;
     RECT  0.084 9.072 0.133 9.096 ;
     RECT  0.06 9.096 0.133 9.216 ;
     RECT  0.084 9.216 0.133 9.24 ;
     RECT  0.06 9.24 0.133 9.36 ;
     RECT  0.084 9.36 0.133 9.384 ;
     RECT  0.06 9.384 0.133 9.504 ;
     RECT  0.084 9.504 0.133 9.528 ;
     RECT  0.06 9.528 0.133 9.648 ;
     RECT  0.084 9.648 0.133 9.672 ;
     RECT  0.06 9.672 0.133 9.792 ;
     RECT  0.084 9.792 0.133 9.816 ;
     RECT  0.06 9.816 0.133 9.936 ;
     RECT  0.084 9.936 0.133 9.96 ;
     RECT  0.084 10.944 0.133 10.968 ;
     RECT  0.06 10.968 0.133 11.088 ;
     RECT  0.084 11.088 0.133 11.112 ;
     RECT  0.06 11.112 0.133 11.232 ;
     RECT  0.084 11.232 0.133 11.256 ;
     RECT  0.06 11.256 0.133 11.376 ;
     RECT  0.084 11.376 0.133 11.4 ;
     RECT  0.06 11.4 0.133 11.52 ;
     RECT  0.084 11.52 0.133 11.544 ;
     RECT  0.06 11.544 0.133 11.664 ;
     RECT  0.084 11.664 0.133 11.688 ;
     RECT  0.06 11.688 0.133 11.808 ;
     RECT  0.084 11.808 0.133 11.832 ;
     RECT  0.06 11.832 0.133 11.952 ;
     RECT  0.084 11.952 0.133 11.976 ;
     RECT  0.06 11.976 0.133 12.096 ;
     RECT  0.084 12.096 0.133 12.12 ;
     RECT  0.06 12.12 0.133 12.24 ;
     RECT  0.084 12.24 0.133 12.264 ;
     RECT  0.06 12.264 0.133 12.384 ;
     RECT  0.084 12.384 0.133 12.408 ;
     RECT  0.06 12.408 0.133 12.528 ;
     RECT  0.084 12.528 0.133 12.552 ;
     RECT  0.06 12.552 0.133 12.672 ;
     RECT  0.084 12.672 0.133 12.696 ;
     RECT  0.06 12.696 0.133 12.816 ;
     RECT  0.084 12.816 0.133 12.84 ;
     RECT  0.06 12.84 0.133 12.96 ;
     RECT  0.084 12.96 0.133 12.984 ;
     RECT  0.06 12.984 0.133 13.104 ;
     RECT  0.084 13.104 0.133 13.128 ;
     RECT  0.06 13.128 0.133 13.248 ;
     RECT  0.084 13.248 0.133 13.272 ;
     RECT  0.06 13.272 0.133 13.392 ;
     RECT  0.084 13.392 0.133 13.416 ;
     RECT  0.06 13.416 0.133 13.536 ;
     RECT  0.084 13.536 0.133 13.56 ;
     RECT  0.06 13.56 0.133 13.68 ;
     RECT  0.084 13.68 0.133 13.704 ;
     RECT  0.06 13.704 0.133 13.824 ;
     RECT  0.084 13.824 0.133 13.848 ;
     RECT  0.06 13.848 0.133 13.968 ;
     RECT  0.084 13.968 0.133 13.992 ;
     RECT  0.06 13.992 0.133 14.112 ;
     RECT  0.084 14.112 0.133 14.136 ;
     RECT  0.06 14.136 0.133 14.256 ;
     RECT  0.084 14.256 0.133 14.28 ;
     RECT  0.06 14.28 0.133 14.4 ;
     RECT  0.084 14.4 0.133 14.424 ;
     RECT  0.06 14.424 0.133 14.544 ;
     RECT  0.084 14.544 0.133 14.568 ;
     RECT  0.133 0.864 1.757 14.568 ;
     RECT  1.757 1.008 1.793 14.568 ;
     RECT  1.793 1.152 2.333 14.568 ;
     RECT  2.333 1.296 2.408 14.568 ;
     RECT  2.408 1.296 2.512 27.012 ;
     RECT  2.512 1.296 2.704 26.742 ;
     RECT  2.704 1.296 2.873 14.424 ;
     RECT  2.873 10.896 2.909 14.424 ;
     RECT  2.873 1.296 3.161 9.912 ;
     RECT  2.909 10.896 3.413 13.896 ;
     RECT  3.413 13.392 3.521 13.896 ;
     RECT  3.161 1.44 4.453 9.912 ;
     RECT  3.413 10.896 4.453 12.312 ;
     RECT  3.521 13.872 4.489 13.896 ;
     RECT  2.704 15.408 4.849 15.432 ;
     RECT  4.453 1.44 5.029 12.312 ;
     RECT  5.029 1.44 5.108 12.552 ;
     RECT  4.489 13.584 5.108 13.896 ;
     RECT  4.849 15.408 5.108 15.528 ;
     RECT  5.108 1.44 5.212 27.012 ;
     RECT  5.212 1.44 5.404 26.742 ;
     RECT  5.404 1.44 5.501 16.296 ;
     RECT  5.501 13.584 5.977 16.296 ;
     RECT  6.541 22.8 6.805 22.824 ;
     RECT  5.501 1.44 6.901 12.504 ;
     RECT  6.973 17.616 6.997 17.64 ;
     RECT  6.937 18.816 6.997 18.84 ;
     RECT  6.901 1.44 7.225 12.6 ;
     RECT  5.977 13.584 7.225 13.992 ;
     RECT  5.977 15.408 7.333 16.296 ;
     RECT  6.997 17.616 7.333 18.84 ;
     RECT  6.805 22.272 7.513 22.824 ;
     RECT  6.649 21.072 7.621 21.096 ;
     RECT  7.333 15.408 7.628 18.84 ;
     RECT  7.621 20.88 7.669 21.096 ;
     RECT  7.513 22.272 7.669 23.4 ;
     RECT  7.225 1.44 7.808 13.992 ;
     RECT  7.628 15.408 7.808 19.272 ;
     RECT  7.669 20.88 7.808 21.192 ;
     RECT  7.669 22.224 7.808 23.4 ;
     RECT  7.808 1.44 7.912 27.012 ;
     RECT  7.912 1.44 7.985 26.742 ;
     RECT  7.985 2.418 8.104 26.742 ;
     RECT  8.104 2.592 8.237 13.896 ;
     RECT  8.104 21.168 8.243 22.872 ;
     RECT  8.104 15.024 8.633 17.976 ;
     RECT  8.243 21.168 9.421 21.192 ;
     RECT  9.421 20.928 9.493 21.192 ;
     RECT  8.243 22.272 9.493 22.872 ;
     RECT  8.633 17.952 9.565 17.976 ;
     RECT  9.493 22.272 9.601 23.112 ;
     RECT  8.104 19.584 9.673 19.608 ;
     RECT  9.493 20.592 9.673 21.192 ;
     RECT  9.601 22.272 9.685 23.304 ;
     RECT  9.685 22.224 9.709 23.304 ;
     RECT  8.104 25.056 9.745 25.08 ;
     RECT  9.673 19.584 10.249 21.192 ;
     RECT  9.709 22.224 10.249 23.544 ;
     RECT  8.237 2.832 10.349 13.896 ;
     RECT  8.633 15.024 10.349 16.824 ;
     RECT  10.349 2.832 10.393 16.824 ;
     RECT  9.565 17.952 10.393 18.504 ;
     RECT  10.357 27.936 10.429 27.96 ;
     RECT  10.393 2.832 10.508 18.504 ;
     RECT  10.249 19.584 10.508 23.544 ;
     RECT  9.745 25.056 10.508 25.272 ;
     RECT  10.429 27.36 10.508 27.96 ;
     RECT  10.508 2.148 10.612 27.96 ;
     RECT  10.612 2.418 10.804 27.96 ;
     RECT  10.804 24.72 10.835 27.96 ;
     RECT  10.804 20.88 10.931 21.528 ;
     RECT  10.804 22.848 10.931 23.544 ;
     RECT  10.931 20.88 10.937 21.192 ;
     RECT  10.835 24.72 11.045 26.808 ;
     RECT  10.804 18.24 11.153 18.792 ;
     RECT  11.077 29.04 11.189 29.064 ;
     RECT  10.835 27.888 11.266 27.96 ;
     RECT  10.804 3.312 11.297 17.064 ;
     RECT  11.045 24.72 11.621 25.704 ;
     RECT  11.266 27.888 11.843 28.008 ;
     RECT  11.153 18.48 11.905 18.792 ;
     RECT  10.937 21.12 11.905 21.192 ;
     RECT  10.931 22.896 11.905 23.544 ;
     RECT  11.905 18.48 11.941 19.416 ;
     RECT  11.905 21.12 11.941 21.768 ;
     RECT  11.297 3.312 11.945 16.872 ;
     RECT  11.941 28.992 12.085 29.016 ;
     RECT  11.045 26.784 12.229 26.808 ;
     RECT  11.905 22.8 12.337 23.544 ;
     RECT  11.621 24.72 12.337 24.744 ;
     RECT  12.085 28.896 12.419 29.016 ;
     RECT  12.229 26.208 12.517 26.808 ;
     RECT  12.419 28.944 12.521 28.968 ;
     RECT  11.941 18.48 12.62 21.768 ;
     RECT  12.337 22.8 12.62 24.744 ;
     RECT  12.62 18.48 12.733 24.744 ;
     RECT  12.517 26.208 12.949 27.336 ;
     RECT  12.949 26.112 13.093 27.336 ;
     RECT  11.945 3.312 13.208 16.824 ;
     RECT  12.733 18 13.208 24.744 ;
     RECT  13.093 26.016 13.208 27.336 ;
     RECT  13.208 2.148 13.312 27.336 ;
     RECT  13.312 2.418 13.504 27.336 ;
     RECT  13.381 28.992 13.525 29.016 ;
     RECT  13.525 28.896 13.669 29.016 ;
     RECT  13.504 21.12 13.811 27.336 ;
     RECT  13.669 28.8 13.811 29.016 ;
     RECT  13.504 3.312 14.051 20.136 ;
     RECT  14.051 4.176 14.285 20.136 ;
     RECT  14.285 4.176 14.465 18.792 ;
     RECT  13.811 21.168 14.501 27.336 ;
     RECT  14.501 21.504 14.609 27.336 ;
     RECT  13.811 28.992 14.675 29.016 ;
     RECT  14.609 21.504 14.716 25.32 ;
     RECT  14.465 4.176 15.793 18.504 ;
     RECT  14.609 26.688 15.793 27.336 ;
     RECT  15.397 2.832 15.908 2.856 ;
     RECT  15.793 3.84 15.908 18.504 ;
     RECT  14.285 20.112 15.908 20.136 ;
     RECT  14.716 21.504 15.908 25.272 ;
     RECT  15.793 26.688 15.908 27.384 ;
     RECT  15.908 2.148 16.012 27.384 ;
     RECT  16.012 2.418 16.019 27.384 ;
     RECT  16.019 2.418 16.204 27.336 ;
     RECT  16.204 21.12 16.307 27.336 ;
     RECT  16.307 27.264 16.769 27.336 ;
     RECT  16.204 2.832 16.835 19.896 ;
     RECT  16.835 2.832 16.876 3.432 ;
     RECT  16.769 27.312 17.021 27.336 ;
     RECT  16.876 2.832 17.237 2.856 ;
     RECT  16.307 21.12 17.237 26.232 ;
     RECT  16.835 4.704 17.273 19.896 ;
     RECT  17.273 18.432 17.525 19.896 ;
     RECT  17.525 18.48 17.633 19.896 ;
     RECT  17.273 4.704 17.917 17.4 ;
     RECT  17.917 4.512 18.205 17.4 ;
     RECT  18.205 4.176 18.385 17.4 ;
     RECT  18.385 4.176 18.529 17.496 ;
     RECT  17.633 18.48 18.529 19.848 ;
     RECT  18.529 4.176 18.608 19.848 ;
     RECT  17.237 21.216 18.608 26.232 ;
     RECT  18.608 2.148 18.712 27.012 ;
     RECT  18.712 2.148 18.904 26.742 ;
     RECT  18.904 2.148 18.925 2.28 ;
     RECT  18.925 1.728 19.393 2.28 ;
     RECT  19.393 1.152 19.477 2.28 ;
     RECT  18.904 3.408 19.721 20.088 ;
     RECT  18.904 23.088 19.811 26.328 ;
     RECT  18.904 21.936 19.909 22.104 ;
     RECT  19.811 23.088 19.909 25.272 ;
     RECT  19.909 21.936 19.955 25.272 ;
     RECT  19.955 24.24 20.045 25.272 ;
     RECT  19.477 1.728 20.509 2.28 ;
     RECT  19.955 21.936 20.645 23.112 ;
     RECT  19.721 4.464 20.677 20.088 ;
     RECT  20.645 21.12 20.677 23.112 ;
     RECT  20.045 24.624 21.085 25.272 ;
     RECT  19.811 26.304 21.085 26.328 ;
     RECT  21.085 24.624 21.116 26.328 ;
     RECT  20.509 1.728 21.229 2.328 ;
     RECT  21.229 1.632 21.308 2.328 ;
     RECT  19.721 3.408 21.308 3.432 ;
     RECT  20.677 4.464 21.308 23.112 ;
     RECT  21.116 24.288 21.308 26.328 ;
     RECT  21.308 1.632 21.347 27.012 ;
     RECT  21.347 1.728 21.445 27.012 ;
     RECT  21.445 0.096 21.589 0.12 ;
     RECT  21.445 1.728 21.604 27.336 ;
     RECT  21.604 2.88 21.881 2.952 ;
     RECT  21.881 2.928 21.953 2.952 ;
     RECT  21.604 25.68 22.025 26.136 ;
     RECT  21.604 18.768 22.205 23.4 ;
     RECT  21.589 0.096 22.237 0.168 ;
     RECT  22.237 0.096 22.241 0.648 ;
     RECT  21.949 29.04 22.355 29.064 ;
     RECT  22.241 0.576 22.393 0.648 ;
     RECT  22.393 0.624 22.643 0.648 ;
     RECT  21.604 4.464 22.669 17.736 ;
     RECT  22.205 18.768 22.669 22.824 ;
     RECT  21.604 24.384 22.705 24.504 ;
     RECT  22.669 3.456 22.741 3.48 ;
     RECT  22.669 4.464 22.741 22.824 ;
     RECT  22.025 25.68 22.745 25.704 ;
     RECT  21.604 1.728 22.844 1.8 ;
     RECT  22.705 23.808 22.993 24.504 ;
     RECT  21.604 27.312 23.132 27.336 ;
     RECT  22.741 3.456 23.281 22.824 ;
     RECT  22.993 23.808 23.281 25.08 ;
     RECT  23.132 26.784 23.353 27.336 ;
     RECT  22.981 28.992 23.363 29.016 ;
     RECT  22.844 1.728 23.717 2.28 ;
     RECT  23.281 3.456 23.845 25.08 ;
     RECT  23.717 1.776 23.933 2.28 ;
     RECT  23.933 2.148 24.008 2.28 ;
     RECT  23.845 3.456 24.008 25.128 ;
     RECT  23.353 26.16 24.008 27.336 ;
     RECT  24.008 2.148 24.112 27.336 ;
     RECT  24.112 2.418 24.304 27.336 ;
     RECT  24.304 12.816 24.509 25.656 ;
     RECT  23.893 28.464 24.515 28.488 ;
     RECT  24.509 20.592 24.905 25.656 ;
     RECT  24.905 25.392 25.049 25.656 ;
     RECT  25.049 25.392 25.337 25.56 ;
     RECT  24.304 3.408 25.513 11.832 ;
     RECT  24.509 12.816 25.513 19.368 ;
     RECT  24.905 20.592 25.517 24.36 ;
     RECT  24.304 26.784 25.523 27.336 ;
     RECT  25.513 3.408 25.553 19.368 ;
     RECT  25.553 18.96 25.669 19.368 ;
     RECT  25.517 20.592 25.669 23.928 ;
     RECT  25.523 27.072 25.697 27.336 ;
     RECT  25.325 29.04 25.909 29.064 ;
     RECT  25.337 25.536 26.125 25.56 ;
     RECT  25.909 28.992 26.309 29.064 ;
     RECT  26.309 29.04 26.417 29.064 ;
     RECT  25.553 3.408 26.708 17.736 ;
     RECT  25.669 18.96 26.708 23.928 ;
     RECT  26.125 25.536 26.708 25.752 ;
     RECT  25.697 27.072 26.708 27.096 ;
     RECT  26.708 2.148 26.812 27.096 ;
     RECT  26.812 2.304 27.004 27.096 ;
     RECT  27.004 25.536 27.533 27.096 ;
     RECT  27.533 25.536 27.605 26.76 ;
     RECT  27.605 26.736 27.893 26.76 ;
     RECT  27.004 20.16 27.965 22.92 ;
     RECT  27.965 21.216 28.213 22.92 ;
     RECT  27.004 23.904 28.213 23.928 ;
     RECT  28.213 21.216 28.789 24.504 ;
     RECT  27.605 25.68 28.789 25.704 ;
     RECT  27.965 20.16 29.149 20.232 ;
     RECT  28.789 21.216 29.149 25.704 ;
     RECT  27.004 2.304 29.408 18.984 ;
     RECT  29.149 20.16 29.408 25.704 ;
     RECT  29.408 2.148 29.512 27.012 ;
     RECT  29.512 2.304 29.704 26.742 ;
     RECT  29.704 23.28 29.909 25.032 ;
     RECT  29.704 20.88 30.197 21.72 ;
     RECT  29.704 2.304 30.521 18.984 ;
     RECT  29.909 23.28 30.629 24.504 ;
     RECT  30.521 2.304 30.701 18.552 ;
     RECT  30.629 23.808 30.755 24.504 ;
     RECT  30.197 20.88 30.845 21.096 ;
     RECT  30.701 2.544 32.108 18.552 ;
     RECT  30.845 21.072 32.108 21.096 ;
     RECT  30.755 24.48 32.108 24.504 ;
     RECT  32.108 2.148 32.212 27.012 ;
     RECT  32.212 2.418 32.404 26.742 ;
     RECT  32.404 24.096 32.531 24.12 ;
     RECT  32.404 2.832 32.825 19.368 ;
     RECT  32.404 20.832 32.825 20.856 ;
     RECT  32.825 2.832 33.059 19.08 ;
     RECT  33.059 2.88 33.113 19.08 ;
     RECT  32.404 22.992 33.397 23.016 ;
     RECT  32.404 26.208 33.901 26.232 ;
     RECT  33.113 2.88 34.081 19.032 ;
     RECT  34.045 20.736 34.153 21 ;
     RECT  33.397 22.032 34.153 23.016 ;
     RECT  34.22 0.528 34.307 0.552 ;
     RECT  34.153 20.4 34.369 23.016 ;
     RECT  34.405 24.72 34.585 24.744 ;
     RECT  34.364 0.576 34.685 1.128 ;
     RECT  34.081 2.304 34.685 19.032 ;
     RECT  34.585 24.72 34.693 24.936 ;
     RECT  34.685 0.576 34.808 19.032 ;
     RECT  34.369 20.304 34.808 23.016 ;
     RECT  34.693 24.384 34.808 24.936 ;
     RECT  33.901 26.208 34.808 26.664 ;
     RECT  34.808 0.576 34.912 27.012 ;
     RECT  34.912 0.576 34.985 26.742 ;
     RECT  34.985 1.728 35.104 26.742 ;
     RECT  34.985 0.576 35.237 0.6 ;
     RECT  35.104 1.728 35.273 2.328 ;
     RECT  35.273 1.776 35.597 2.328 ;
     RECT  35.104 24.384 35.885 26.664 ;
     RECT  35.885 24.384 36.385 25.512 ;
     RECT  36.385 24.096 36.425 25.512 ;
     RECT  35.597 1.776 36.641 1.8 ;
     RECT  35.104 3.936 36.961 22.776 ;
     RECT  36.961 3.12 37.148 22.776 ;
     RECT  36.425 24.096 37.148 24.168 ;
     RECT  36.425 25.152 37.189 25.512 ;
     RECT  35.885 26.64 37.189 26.664 ;
     RECT  37.148 3.12 37.508 24.168 ;
     RECT  37.189 25.152 37.508 26.664 ;
     RECT  37.508 2.148 37.612 27.012 ;
     RECT  37.612 2.148 37.804 26.742 ;
     RECT  37.804 25.248 37.973 26.664 ;
     RECT  37.804 2.736 38.225 22.776 ;
     RECT  37.973 25.248 38.261 26.232 ;
     RECT  38.225 20.88 38.837 22.776 ;
     RECT  38.509 1.728 38.916 1.752 ;
     RECT  38.225 2.736 38.916 19.56 ;
     RECT  38.837 20.88 39.509 22.248 ;
     RECT  38.916 1.728 39.553 19.56 ;
     RECT  39.553 1.68 39.923 19.56 ;
     RECT  39.509 20.688 39.925 22.248 ;
     RECT  39.923 1.728 39.98 19.56 ;
     RECT  39.925 20.688 39.98 22.296 ;
     RECT  38.261 25.296 39.985 26.232 ;
     RECT  39.973 0.192 40.069 0.216 ;
     RECT  39.985 25.296 40.129 26.616 ;
     RECT  39.98 1.728 40.208 22.296 ;
     RECT  40.129 24.48 40.208 26.616 ;
     RECT  40.208 1.728 40.312 27.012 ;
     RECT  40.069 0.144 40.355 0.216 ;
     RECT  40.355 0.144 40.453 0.168 ;
     RECT  40.312 1.728 40.504 26.742 ;
     RECT  40.453 0.096 41.069 0.168 ;
     RECT  41.069 0.144 41.141 0.168 ;
     RECT  40.504 3.936 41.321 23.352 ;
     RECT  41.321 3.936 41.465 22.2 ;
     RECT  40.504 1.728 41.497 2.856 ;
     RECT  40.504 24.48 41.557 25.512 ;
     RECT  40.504 26.544 41.557 26.616 ;
     RECT  41.557 24.48 41.603 26.616 ;
     RECT  41.603 24.624 41.645 26.568 ;
     RECT  41.497 1.728 41.713 2.904 ;
     RECT  41.465 3.936 41.713 19.896 ;
     RECT  41.645 26.544 41.717 26.568 ;
     RECT  41.713 1.728 42.469 19.896 ;
     RECT  41.465 20.88 42.469 22.2 ;
     RECT  42.469 1.728 42.541 22.2 ;
     RECT  42.541 1.728 42.908 22.296 ;
     RECT  41.321 23.328 42.908 23.352 ;
     RECT  41.645 24.624 42.908 25.56 ;
     RECT  42.865 26.64 42.908 26.664 ;
     RECT  42.908 1.728 43.012 27.012 ;
     RECT  43.012 1.728 43.204 26.742 ;
     RECT  43.204 1.728 43.477 19.656 ;
     RECT  42.325 0.144 43.724 0.168 ;
     RECT  43.477 1.2 43.724 19.656 ;
     RECT  43.724 0.144 43.763 19.656 ;
     RECT  43.763 14.976 43.805 19.656 ;
     RECT  43.763 0.144 43.811 13.896 ;
     RECT  43.204 20.688 44.057 23.352 ;
     RECT  44.057 20.976 44.093 23.352 ;
     RECT  43.204 26.64 44.161 26.742 ;
     RECT  43.811 0.144 44.195 0.168 ;
     RECT  43.204 24.72 44.449 24.744 ;
     RECT  44.449 24.72 44.489 25.032 ;
     RECT  44.161 26.64 44.525 26.76 ;
     RECT  43.811 1.728 44.561 13.896 ;
     RECT  44.561 1.728 44.773 1.752 ;
     RECT  43.805 14.976 44.809 19.272 ;
     RECT  44.773 1.152 44.876 1.752 ;
     RECT  44.876 0.528 44.993 1.752 ;
     RECT  44.993 1.68 45.107 1.752 ;
     RECT  44.489 25.008 45.164 25.032 ;
     RECT  44.525 26.64 45.164 26.664 ;
     RECT  44.561 2.736 45.205 13.896 ;
     RECT  44.809 14.976 45.205 19.368 ;
     RECT  44.993 0.528 45.349 0.6 ;
     RECT  45.107 1.728 45.608 1.752 ;
     RECT  45.205 2.736 45.608 19.368 ;
     RECT  44.093 20.976 45.608 22.872 ;
     RECT  45.457 23.856 45.608 23.88 ;
     RECT  45.164 25.008 45.608 26.664 ;
     RECT  45.608 1.728 45.712 27.012 ;
     RECT  45.712 1.728 45.904 26.742 ;
     RECT  45.904 3.408 46.019 20.088 ;
     RECT  45.904 22.464 46.067 23.928 ;
     RECT  45.349 0.096 46.073 0.6 ;
     RECT  45.904 25.008 46.108 25.032 ;
     RECT  45.904 21.408 46.115 21.432 ;
     RECT  46.067 22.464 46.115 23.88 ;
     RECT  45.904 1.728 46.493 1.752 ;
     RECT  46.073 0.096 46.685 0.12 ;
     RECT  46.115 22.512 46.865 23.88 ;
     RECT  46.493 1.152 46.901 1.752 ;
     RECT  46.901 1.2 47.117 1.752 ;
     RECT  46.019 3.408 47.297 19.8 ;
     RECT  47.117 1.728 47.329 1.752 ;
     RECT  47.329 1.728 47.365 2.28 ;
     RECT  47.297 3.408 47.365 19.416 ;
     RECT  46.865 23.232 48.157 23.88 ;
     RECT  47.509 0.192 48.181 0.216 ;
     RECT  47.365 1.728 48.308 19.416 ;
     RECT  48.085 21.12 48.308 21.144 ;
     RECT  48.157 23.232 48.308 23.976 ;
     RECT  48.308 1.728 48.412 27.012 ;
     RECT  48.181 0.144 48.418 0.216 ;
     RECT  48.418 0.096 48.517 0.216 ;
     RECT  48.412 1.728 48.604 26.742 ;
     RECT  48.517 0.096 48.851 0.6 ;
     RECT  48.604 20.112 48.899 22.248 ;
     RECT  48.604 2.736 48.953 18.792 ;
     RECT  48.899 21.36 48.989 21.384 ;
     RECT  48.851 0.192 49.097 0.6 ;
     RECT  49.097 0.528 49.201 0.6 ;
     RECT  48.604 1.728 49.201 1.752 ;
     RECT  49.201 0.528 49.285 1.752 ;
     RECT  49.285 1.728 49.661 1.752 ;
     RECT  48.953 2.736 49.661 11.736 ;
     RECT  49.661 1.728 49.859 11.736 ;
     RECT  49.285 0.528 50.147 0.6 ;
     RECT  49.859 4.176 50.281 11.736 ;
     RECT  48.953 12.864 50.281 18.792 ;
     RECT  50.147 0.576 50.317 0.6 ;
     RECT  49.859 1.728 50.317 2.856 ;
     RECT  50.317 0.576 50.579 2.856 ;
     RECT  50.579 1.728 51.008 2.856 ;
     RECT  50.281 4.176 51.008 18.792 ;
     RECT  51.008 1.728 51.112 27.012 ;
     RECT  51.145 0.528 51.299 0.552 ;
     RECT  51.112 1.728 51.304 26.742 ;
     RECT  51.304 3.936 51.545 18.792 ;
     RECT  51.545 14.928 52.013 18.792 ;
     RECT  51.304 1.728 52.261 2.808 ;
     RECT  52.261 1.248 52.373 2.808 ;
     RECT  51.397 0.096 52.693 0.12 ;
     RECT  52.373 1.728 52.909 2.808 ;
     RECT  51.545 3.936 52.909 13.944 ;
     RECT  52.013 14.976 53.125 18.792 ;
     RECT  52.909 1.728 53.161 13.944 ;
     RECT  53.125 14.928 53.161 18.792 ;
     RECT  52.693 0.096 53.273 0.168 ;
     RECT  53.365 0.192 53.557 0.216 ;
     RECT  53.161 1.728 53.708 18.792 ;
     RECT  53.557 0.192 53.747 0.312 ;
     RECT  53.708 1.728 53.812 27.012 ;
     RECT  53.812 1.728 54.004 26.742 ;
     RECT  54.004 1.728 54.133 18.792 ;
     RECT  54.133 1.152 54.179 18.792 ;
     RECT  54.179 1.152 54.785 18.552 ;
     RECT  54.277 0.096 55.045 0.168 ;
     RECT  55.045 0.096 55.145 0.552 ;
     RECT  55.145 0.144 55.397 0.552 ;
     RECT  55.397 0.48 55.861 0.552 ;
     RECT  54.785 1.728 56.089 18.552 ;
     RECT  55.861 0.48 56.149 0.6 ;
     RECT  56.149 0.48 56.339 0.648 ;
     RECT  56.089 2.148 56.408 18.552 ;
     RECT  56.408 2.148 56.512 27.012 ;
     RECT  56.339 0.48 56.581 0.552 ;
     RECT  56.581 0.336 56.693 0.552 ;
     RECT  56.512 2.208 56.704 26.742 ;
     RECT  56.693 0.336 56.725 0.36 ;
     RECT  56.725 0.24 56.866 0.36 ;
     RECT  56.866 0.096 56.867 0.36 ;
     RECT  56.867 0.096 56.915 0.264 ;
     RECT  56.915 0.096 57.097 0.168 ;
     RECT  57.097 0.096 57.197 0.12 ;
     RECT  56.704 2.208 57.685 13.08 ;
     RECT  56.704 14.496 57.827 18.552 ;
     RECT  57.827 14.496 57.985 15.384 ;
     RECT  57.685 2.208 58.117 13.128 ;
     RECT  58.117 2.208 58.405 13.32 ;
     RECT  57.985 14.4 58.405 15.384 ;
     RECT  58.273 0.048 58.445 0.072 ;
     RECT  58.405 2.208 58.741 15.384 ;
     RECT  58.445 0.048 58.933 0.12 ;
     RECT  58.741 1.728 59.108 15.384 ;
     RECT  57.827 16.368 59.108 18.552 ;
     RECT  59.108 1.728 59.212 27.012 ;
     RECT  59.212 1.728 59.404 26.742 ;
     RECT  59.404 1.728 59.537 13.128 ;
     RECT  59.537 2.112 59.651 13.128 ;
     RECT  59.651 2.208 59.699 13.128 ;
     RECT  59.404 18.432 59.717 18.456 ;
     RECT  59.404 14.4 59.861 15.288 ;
     RECT  59.699 2.256 60.005 13.128 ;
     RECT  60.005 2.256 60.371 11.4 ;
     RECT  58.933 0.048 60.469 0.168 ;
     RECT  59.861 14.4 60.473 14.952 ;
     RECT  60.473 14.4 60.545 14.424 ;
     RECT  60.469 0.048 60.553 0.6 ;
     RECT  60.553 0.048 60.653 0.216 ;
     RECT  60.653 0.144 60.697 0.216 ;
     RECT  60.371 10.032 60.797 11.4 ;
     RECT  60.005 12.48 60.973 13.128 ;
     RECT  60.371 2.256 61.045 8.616 ;
     RECT  60.697 0.144 61.669 0.168 ;
     RECT  61.045 1.728 61.808 8.616 ;
     RECT  60.797 10.032 61.808 11.208 ;
     RECT  60.973 12.48 61.808 13.848 ;
     RECT  61.808 1.728 61.912 27.012 ;
     RECT  61.669 0.144 61.955 0.216 ;
     RECT  61.955 0.192 62.099 0.216 ;
     RECT  61.912 1.728 62.104 26.742 ;
     RECT  62.104 12.48 62.129 13.848 ;
     RECT  62.104 1.728 62.309 10.968 ;
     RECT  62.309 2.256 62.345 10.968 ;
     RECT  62.345 2.304 62.387 10.968 ;
     RECT  62.387 2.304 62.531 3.72 ;
     RECT  62.387 5.088 62.569 10.968 ;
     RECT  62.531 3.696 62.675 3.72 ;
     RECT  62.531 2.304 62.819 2.328 ;
     RECT  62.104 14.832 63.205 16.152 ;
     RECT  62.104 17.28 63.205 18.024 ;
     RECT  62.569 5.328 63.241 10.968 ;
     RECT  62.129 12.48 63.241 13.704 ;
     RECT  63.205 14.832 63.241 18.024 ;
     RECT  63.241 5.328 63.745 11.112 ;
     RECT  63.241 12.48 63.745 18.168 ;
     RECT  63.745 5.328 64.716 5.352 ;
     RECT  63.745 5.352 64.764 5.472 ;
     RECT  63.745 5.472 64.716 5.496 ;
     RECT  63.745 5.496 64.764 5.616 ;
     RECT  63.745 5.616 64.716 5.64 ;
     RECT  63.745 5.64 64.764 5.76 ;
     RECT  63.745 5.76 64.716 5.784 ;
     RECT  63.745 5.784 64.764 5.904 ;
     RECT  63.745 5.904 64.716 5.928 ;
     RECT  63.745 5.928 64.764 6.048 ;
     RECT  63.745 6.048 64.716 6.072 ;
     RECT  63.745 6.072 64.764 6.192 ;
     RECT  63.745 6.192 64.716 6.216 ;
     RECT  63.745 6.216 64.764 6.336 ;
     RECT  63.745 6.336 64.716 6.36 ;
     RECT  63.745 6.36 64.764 6.48 ;
     RECT  63.745 6.48 64.716 6.504 ;
     RECT  63.745 6.504 64.764 6.624 ;
     RECT  63.745 6.624 64.716 6.648 ;
     RECT  63.745 6.648 64.764 6.768 ;
     RECT  63.745 6.768 64.716 6.792 ;
     RECT  63.745 6.792 64.764 6.912 ;
     RECT  63.745 6.912 64.716 6.936 ;
     RECT  63.745 6.936 64.764 7.056 ;
     RECT  63.745 7.056 64.716 7.08 ;
     RECT  63.745 7.08 64.764 7.2 ;
     RECT  63.745 7.2 64.716 7.224 ;
     RECT  63.745 7.224 64.764 7.344 ;
     RECT  63.745 7.344 64.716 7.368 ;
     RECT  63.745 7.368 64.764 7.488 ;
     RECT  63.745 7.488 64.716 7.512 ;
     RECT  63.745 7.512 64.764 7.632 ;
     RECT  63.745 7.632 64.716 7.656 ;
     RECT  63.745 7.656 64.764 7.776 ;
     RECT  63.745 7.776 64.716 7.8 ;
     RECT  63.745 7.8 64.764 7.92 ;
     RECT  63.745 7.92 64.716 7.944 ;
     RECT  63.745 7.944 64.764 8.064 ;
     RECT  63.745 8.064 64.716 8.088 ;
     RECT  63.745 8.088 64.764 8.208 ;
     RECT  63.745 8.208 64.716 8.232 ;
     RECT  63.745 8.232 64.764 8.352 ;
     RECT  63.745 8.352 64.716 8.376 ;
     RECT  63.745 8.376 64.764 8.496 ;
     RECT  63.745 8.496 64.716 8.52 ;
     RECT  63.745 8.52 64.764 8.64 ;
     RECT  63.745 8.64 64.716 8.664 ;
     RECT  63.745 8.664 64.764 8.784 ;
     RECT  63.745 8.784 64.716 8.808 ;
     RECT  63.745 8.808 64.764 8.928 ;
     RECT  63.745 8.928 64.716 8.952 ;
     RECT  63.745 8.952 64.764 9.072 ;
     RECT  63.745 9.072 64.716 9.096 ;
     RECT  63.745 9.096 64.764 9.216 ;
     RECT  63.745 9.216 64.716 9.24 ;
     RECT  63.745 9.24 64.764 9.36 ;
     RECT  63.745 9.36 64.716 9.384 ;
     RECT  63.745 9.384 64.764 9.504 ;
     RECT  63.745 9.504 64.716 9.528 ;
     RECT  63.745 9.528 64.764 9.648 ;
     RECT  63.745 9.648 64.716 9.672 ;
     RECT  63.745 9.672 64.764 9.792 ;
     RECT  63.745 9.792 64.716 9.816 ;
     RECT  63.745 9.816 64.764 9.936 ;
     RECT  63.745 9.936 64.716 9.96 ;
     RECT  63.745 9.96 64.764 10.08 ;
     RECT  63.745 10.08 64.716 10.104 ;
     RECT  63.745 10.104 64.764 10.224 ;
     RECT  63.745 10.224 64.716 10.248 ;
     RECT  63.745 10.248 64.764 10.368 ;
     RECT  63.745 10.368 64.716 10.392 ;
     RECT  63.745 10.392 64.764 10.512 ;
     RECT  63.745 10.512 64.716 10.536 ;
     RECT  63.745 10.536 64.764 10.656 ;
     RECT  63.745 10.656 64.716 10.68 ;
     RECT  63.745 10.68 64.764 10.8 ;
     RECT  63.745 10.8 64.716 10.824 ;
     RECT  63.745 10.824 64.764 10.944 ;
     RECT  63.745 10.944 64.716 10.968 ;
     RECT  63.745 10.968 64.764 11.088 ;
     RECT  63.745 11.088 64.716 11.112 ;
     RECT  63.745 11.112 64.764 11.232 ;
     RECT  63.745 11.232 64.716 11.256 ;
     RECT  63.745 11.256 64.764 11.376 ;
     RECT  63.745 11.376 64.716 11.4 ;
     RECT  63.745 11.4 64.764 11.52 ;
     RECT  63.745 11.52 64.716 11.544 ;
     RECT  63.745 11.544 64.764 11.664 ;
     RECT  63.745 11.664 64.716 11.688 ;
     RECT  63.745 11.688 64.764 11.808 ;
     RECT  63.745 11.808 64.716 11.832 ;
     RECT  63.745 11.832 64.764 11.952 ;
     RECT  63.745 11.952 64.716 11.976 ;
     RECT  63.745 11.976 64.764 12.096 ;
     RECT  63.745 12.096 64.716 12.12 ;
     RECT  63.745 12.12 64.764 12.24 ;
     RECT  63.745 12.24 64.716 12.264 ;
     RECT  63.745 12.264 64.764 12.384 ;
     RECT  63.745 12.384 64.716 12.408 ;
     RECT  63.745 12.408 64.764 12.528 ;
     RECT  63.745 12.528 64.716 12.552 ;
     RECT  63.745 12.552 64.764 12.672 ;
     RECT  63.745 12.672 64.716 12.696 ;
     RECT  63.745 12.696 64.764 12.816 ;
     RECT  63.745 12.816 64.716 12.84 ;
     RECT  63.745 12.84 64.764 12.96 ;
     RECT  63.745 12.96 64.716 12.984 ;
     RECT  63.745 12.984 64.764 13.104 ;
     RECT  63.745 13.104 64.716 13.128 ;
     RECT  63.745 13.128 64.764 13.248 ;
     RECT  63.745 13.248 64.716 13.272 ;
     RECT  63.745 13.272 64.764 13.392 ;
     RECT  63.745 13.392 64.716 13.416 ;
     RECT  63.745 13.416 64.764 13.536 ;
     RECT  63.745 13.536 64.716 13.56 ;
     RECT  63.745 13.56 64.764 13.68 ;
     RECT  63.745 13.68 64.716 13.704 ;
     RECT  63.745 13.704 64.764 13.824 ;
     RECT  63.745 13.824 64.716 13.848 ;
     RECT  63.745 13.848 64.764 13.968 ;
     RECT  63.745 13.968 64.716 13.992 ;
     RECT  63.745 13.992 64.764 14.112 ;
     RECT  63.745 14.112 64.716 14.136 ;
     RECT  63.745 14.136 64.764 14.256 ;
     RECT  63.745 14.256 64.716 14.28 ;
     RECT  63.745 14.28 64.764 14.4 ;
     RECT  63.745 14.4 64.716 14.424 ;
     RECT  63.745 14.424 64.764 14.544 ;
     RECT  63.745 14.544 64.716 14.568 ;
     RECT  63.745 14.568 64.764 14.688 ;
     RECT  63.745 14.688 64.716 14.712 ;
     RECT  63.745 14.712 64.764 14.832 ;
     RECT  63.745 14.832 64.716 14.856 ;
     RECT  63.745 14.856 64.764 14.976 ;
     RECT  63.745 14.976 64.716 15 ;
     RECT  63.745 15 64.764 15.12 ;
     RECT  63.745 15.12 64.716 15.144 ;
     RECT  63.745 15.144 64.764 15.264 ;
     RECT  63.745 15.264 64.716 15.288 ;
     RECT  63.745 15.288 64.764 15.408 ;
     RECT  63.745 15.408 64.716 15.432 ;
     RECT  63.745 15.432 64.764 15.552 ;
     RECT  63.745 15.552 64.716 15.576 ;
     RECT  63.745 15.576 64.764 15.696 ;
     RECT  63.745 15.696 64.716 15.72 ;
     RECT  63.745 15.72 64.764 15.84 ;
     RECT  63.745 15.84 64.716 15.864 ;
     RECT  63.745 15.864 64.764 15.984 ;
     RECT  63.745 15.984 64.716 16.008 ;
     RECT  63.745 16.008 64.764 16.128 ;
     RECT  63.745 16.128 64.716 16.152 ;
     RECT  63.745 16.152 64.764 16.272 ;
     RECT  63.745 16.272 64.716 16.296 ;
     RECT  63.745 16.296 64.764 16.416 ;
     RECT  63.745 16.416 64.716 16.44 ;
     RECT  63.745 16.44 64.764 16.56 ;
     RECT  63.745 16.56 64.716 16.584 ;
     RECT  63.745 16.584 64.764 16.704 ;
     RECT  63.745 16.704 64.716 16.728 ;
     RECT  63.745 16.728 64.764 16.848 ;
     RECT  63.745 16.848 64.716 16.872 ;
     RECT  63.745 16.872 64.764 16.992 ;
     RECT  63.745 16.992 64.716 17.016 ;
     RECT  63.745 17.016 64.764 17.136 ;
     RECT  63.745 17.136 64.716 17.16 ;
     RECT  63.745 17.16 64.764 17.28 ;
     RECT  63.745 17.28 64.716 17.304 ;
     RECT  63.745 17.304 64.764 17.424 ;
     RECT  63.745 17.424 64.716 17.448 ;
     RECT  63.745 17.448 64.764 17.568 ;
     RECT  63.745 17.568 64.716 17.592 ;
     RECT  63.745 17.592 64.764 17.712 ;
     RECT  63.745 17.712 64.716 17.736 ;
     RECT  63.745 17.736 64.764 17.856 ;
     RECT  63.745 17.856 64.716 17.88 ;
     RECT  63.745 17.88 64.764 18 ;
     RECT  63.745 18 64.716 18.024 ;
     RECT  63.745 18.024 64.764 18.144 ;
     RECT  63.745 18.144 64.716 18.168 ;
    LAYER M5 ;
     RECT  38.76 0.016 38.88 0.084 ;
     RECT  38.904 0.016 39.024 0.084 ;
     RECT  39.048 0.016 39.168 0.084 ;
     RECT  39.192 0.016 39.312 0.084 ;
     RECT  39.336 0.016 39.456 0.084 ;
     RECT  39.48 0.016 39.6 0.084 ;
     RECT  39.624 0.016 39.744 0.084 ;
     RECT  39.768 0.016 39.888 0.084 ;
     RECT  39.912 0.016 40.032 0.084 ;
     RECT  40.056 0.016 40.176 0.084 ;
     RECT  40.2 0.016 40.32 0.084 ;
     RECT  40.344 0.016 40.464 0.084 ;
     RECT  40.488 0.016 40.608 0.084 ;
     RECT  40.632 0.016 40.752 0.084 ;
     RECT  40.776 0.016 40.896 0.084 ;
     RECT  40.92 0.016 41.04 0.084 ;
     RECT  41.064 0.016 41.184 0.084 ;
     RECT  41.208 0.016 41.328 0.084 ;
     RECT  41.352 0.016 41.472 0.084 ;
     RECT  41.496 0.016 41.616 0.084 ;
     RECT  41.64 0.016 41.76 0.084 ;
     RECT  41.784 0.016 41.904 0.084 ;
     RECT  41.928 0.016 42.048 0.084 ;
     RECT  42.072 0.016 42.192 0.084 ;
     RECT  42.216 0.016 42.336 0.084 ;
     RECT  42.36 0.016 42.48 0.084 ;
     RECT  42.504 0.016 42.624 0.084 ;
     RECT  42.648 0.016 42.768 0.084 ;
     RECT  42.792 0.016 42.912 0.084 ;
     RECT  42.936 0.016 43.056 0.084 ;
     RECT  43.08 0.016 43.2 0.084 ;
     RECT  43.224 0.016 43.344 0.084 ;
     RECT  43.368 0.016 43.488 0.084 ;
     RECT  43.512 0.016 43.632 0.084 ;
     RECT  43.656 0.016 43.776 0.084 ;
     RECT  43.8 0.016 43.92 0.084 ;
     RECT  43.944 0.016 44.064 0.084 ;
     RECT  44.088 0.016 44.208 0.084 ;
     RECT  44.232 0.016 44.352 0.084 ;
     RECT  44.376 0.016 44.496 0.084 ;
     RECT  44.52 0.016 44.64 0.084 ;
     RECT  44.664 0.016 44.784 0.084 ;
     RECT  44.808 0.016 44.928 0.084 ;
     RECT  44.952 0.016 45.072 0.084 ;
     RECT  45.096 0.016 45.216 0.084 ;
     RECT  45.24 0.016 45.36 0.084 ;
     RECT  45.384 0.016 45.504 0.084 ;
     RECT  45.528 0.016 45.648 0.084 ;
     RECT  45.672 0.016 45.792 0.084 ;
     RECT  45.816 0.016 45.936 0.084 ;
     RECT  45.96 0.016 46.08 0.084 ;
     RECT  46.104 0.016 46.224 0.084 ;
     RECT  46.248 0.016 46.368 0.084 ;
     RECT  46.392 0.016 46.512 0.084 ;
     RECT  46.536 0.016 46.656 0.084 ;
     RECT  46.68 0.016 46.8 0.084 ;
     RECT  46.824 0.016 46.944 0.084 ;
     RECT  46.968 0.016 47.088 0.084 ;
     RECT  47.112 0.016 47.232 0.084 ;
     RECT  47.256 0.016 47.376 0.084 ;
     RECT  47.4 0.016 47.52 0.084 ;
     RECT  47.544 0.016 47.664 0.084 ;
     RECT  47.688 0.016 47.808 0.084 ;
     RECT  47.832 0.016 47.952 0.084 ;
     RECT  47.976 0.016 48.096 0.084 ;
     RECT  48.12 0.016 48.24 0.084 ;
     RECT  48.264 0.016 48.384 0.084 ;
     RECT  48.408 0.016 48.528 0.084 ;
     RECT  48.552 0.016 48.672 0.084 ;
     RECT  48.696 0.016 48.816 0.084 ;
     RECT  48.84 0.016 48.96 0.084 ;
     RECT  48.984 0.016 49.104 0.084 ;
     RECT  49.128 0.016 49.248 0.084 ;
     RECT  49.272 0.016 49.392 0.084 ;
     RECT  49.416 0.016 49.536 0.084 ;
     RECT  49.56 0.016 49.68 0.084 ;
     RECT  49.704 0.016 49.824 0.084 ;
     RECT  49.848 0.016 49.968 0.084 ;
     RECT  49.992 0.016 50.112 0.084 ;
     RECT  50.136 0.016 50.256 0.084 ;
     RECT  50.28 0.016 50.4 0.084 ;
     RECT  50.424 0.016 50.544 0.084 ;
     RECT  50.568 0.016 50.688 0.084 ;
     RECT  50.712 0.016 50.832 0.084 ;
     RECT  50.856 0.016 50.976 0.084 ;
     RECT  51 0.016 51.12 0.084 ;
     RECT  51.144 0.016 51.264 0.084 ;
     RECT  51.288 0.016 51.408 0.084 ;
     RECT  51.432 0.016 51.552 0.084 ;
     RECT  51.576 0.016 51.696 0.084 ;
     RECT  51.72 0.016 51.84 0.084 ;
     RECT  51.864 0.016 51.984 0.084 ;
     RECT  52.008 0.016 52.128 0.084 ;
     RECT  52.152 0.016 52.272 0.084 ;
     RECT  52.296 0.016 52.416 0.084 ;
     RECT  52.44 0.016 52.56 0.084 ;
     RECT  52.584 0.016 52.704 0.084 ;
     RECT  52.728 0.016 52.848 0.084 ;
     RECT  52.872 0.016 52.992 0.084 ;
     RECT  53.016 0.016 53.136 0.084 ;
     RECT  53.16 0.016 53.28 0.084 ;
     RECT  53.304 0.016 53.424 0.084 ;
     RECT  53.448 0.016 53.568 0.084 ;
     RECT  53.592 0.016 53.712 0.084 ;
     RECT  53.736 0.016 53.856 0.084 ;
     RECT  53.88 0.016 54 0.084 ;
     RECT  54.024 0.016 54.144 0.084 ;
     RECT  54.168 0.016 54.288 0.084 ;
     RECT  54.312 0.016 54.432 0.084 ;
     RECT  54.456 0.016 54.576 0.084 ;
     RECT  54.6 0.016 54.72 0.084 ;
     RECT  54.744 0.016 54.864 0.084 ;
     RECT  54.888 0.016 55.008 0.084 ;
     RECT  55.032 0.016 55.152 0.084 ;
     RECT  55.176 0.016 55.296 0.084 ;
     RECT  55.32 0.016 55.44 0.084 ;
     RECT  55.464 0.016 55.584 0.084 ;
     RECT  55.608 0.016 55.728 0.084 ;
     RECT  55.752 0.016 55.872 0.084 ;
     RECT  55.896 0.016 56.016 0.084 ;
     RECT  56.04 0.016 56.16 0.084 ;
     RECT  56.184 0.016 56.304 0.084 ;
     RECT  56.328 0.016 56.448 0.084 ;
     RECT  56.472 0.016 56.592 0.084 ;
     RECT  56.616 0.016 56.736 0.084 ;
     RECT  56.76 0.016 56.88 0.084 ;
     RECT  56.904 0.016 57.024 0.084 ;
     RECT  38.736 0.084 57.048 0.179 ;
     RECT  38.736 0.179 56.904 1.763 ;
     RECT  19.176 0.016 19.296 0.084 ;
     RECT  19.32 0.016 19.44 0.084 ;
     RECT  19.464 0.016 19.584 0.084 ;
     RECT  19.608 0.016 19.728 0.084 ;
     RECT  19.752 0.016 19.872 0.084 ;
     RECT  19.896 0.016 20.016 0.084 ;
     RECT  20.04 0.016 20.16 0.084 ;
     RECT  20.184 0.016 20.304 0.084 ;
     RECT  20.328 0.016 20.448 0.084 ;
     RECT  20.472 0.016 20.592 0.084 ;
     RECT  20.616 0.016 20.736 0.084 ;
     RECT  20.76 0.016 20.88 0.084 ;
     RECT  20.904 0.016 21.024 0.084 ;
     RECT  21.048 0.016 21.168 0.084 ;
     RECT  21.192 0.016 21.312 0.084 ;
     RECT  21.336 0.016 21.456 0.084 ;
     RECT  21.48 0.016 21.6 0.084 ;
     RECT  21.624 0.016 21.744 0.084 ;
     RECT  21.768 0.016 21.888 0.084 ;
     RECT  21.912 0.016 22.032 0.084 ;
     RECT  22.056 0.016 22.176 0.084 ;
     RECT  22.2 0.016 22.32 0.084 ;
     RECT  22.344 0.016 22.464 0.084 ;
     RECT  22.488 0.016 22.608 0.084 ;
     RECT  22.632 0.016 22.752 0.084 ;
     RECT  22.776 0.016 22.896 0.084 ;
     RECT  22.92 0.016 23.04 0.084 ;
     RECT  23.064 0.016 23.184 0.084 ;
     RECT  23.208 0.016 23.328 0.084 ;
     RECT  23.352 0.016 23.472 0.084 ;
     RECT  23.496 0.016 23.616 0.084 ;
     RECT  19.152 0.084 23.64 1.811 ;
     RECT  39.024 1.763 46.104 1.811 ;
     RECT  49.68 1.763 56.904 1.811 ;
     RECT  39.312 1.811 46.104 1.859 ;
     RECT  49.824 1.811 56.904 1.907 ;
     RECT  19.152 1.811 21.912 2.137 ;
     RECT  22.896 1.811 23.64 2.137 ;
     RECT  2.4 2.137 2.52 2.151 ;
     RECT  5.1 2.137 5.22 2.151 ;
     RECT  7.8 2.137 7.92 2.151 ;
     RECT  10.5 2.137 10.62 2.151 ;
     RECT  13.2 2.137 13.32 2.151 ;
     RECT  15.9 2.137 16.02 2.151 ;
     RECT  22.896 2.137 24.12 2.151 ;
     RECT  26.7 2.137 26.82 2.151 ;
     RECT  29.4 2.137 29.52 2.151 ;
     RECT  32.1 2.137 32.22 2.151 ;
     RECT  37.5 2.137 37.62 2.151 ;
     RECT  52.656 1.907 56.904 2.197 ;
     RECT  58.344 0.016 58.464 0.084 ;
     RECT  58.488 0.016 58.608 0.084 ;
     RECT  58.632 0.016 58.752 0.084 ;
     RECT  58.776 0.016 58.896 0.084 ;
     RECT  58.92 0.016 59.04 0.084 ;
     RECT  59.064 0.016 59.184 0.084 ;
     RECT  59.208 0.016 59.328 0.084 ;
     RECT  59.352 0.016 59.472 0.084 ;
     RECT  59.496 0.016 59.616 0.084 ;
     RECT  59.64 0.016 59.76 0.084 ;
     RECT  59.784 0.016 59.904 0.084 ;
     RECT  59.928 0.016 60.048 0.084 ;
     RECT  60.072 0.016 60.192 0.084 ;
     RECT  60.216 0.016 60.336 0.084 ;
     RECT  60.36 0.016 60.48 0.084 ;
     RECT  60.504 0.016 60.624 0.084 ;
     RECT  60.648 0.016 60.768 0.084 ;
     RECT  60.792 0.016 60.912 0.084 ;
     RECT  60.936 0.016 61.056 0.084 ;
     RECT  61.08 0.016 61.2 0.084 ;
     RECT  61.224 0.016 61.344 0.084 ;
     RECT  61.368 0.016 61.488 0.084 ;
     RECT  61.512 0.016 61.632 0.084 ;
     RECT  61.656 0.016 61.776 0.084 ;
     RECT  61.8 0.016 61.92 0.084 ;
     RECT  61.944 0.016 62.064 0.084 ;
     RECT  62.088 0.016 62.208 0.084 ;
     RECT  62.232 0.016 62.352 0.084 ;
     RECT  62.376 0.016 62.496 0.084 ;
     RECT  62.52 0.016 62.64 0.084 ;
     RECT  62.664 0.016 62.784 0.084 ;
     RECT  58.32 0.084 62.808 2.197 ;
     RECT  18.6 2.137 21.912 2.291 ;
     RECT  22.896 2.151 24.312 2.291 ;
     RECT  39.456 1.859 46.104 2.291 ;
     RECT  26.7 2.151 27.012 2.293 ;
     RECT  34.152 0.016 34.272 0.084 ;
     RECT  34.296 0.016 34.416 0.084 ;
     RECT  34.44 0.016 34.56 0.084 ;
     RECT  34.584 0.016 34.704 0.084 ;
     RECT  34.728 0.016 34.848 0.084 ;
     RECT  34.872 0.016 34.992 0.084 ;
     RECT  35.016 0.016 35.136 0.084 ;
     RECT  35.16 0.016 35.28 0.084 ;
     RECT  35.304 0.016 35.424 0.084 ;
     RECT  34.128 0.084 35.448 2.339 ;
     RECT  39.984 2.291 46.104 2.339 ;
     RECT  52.656 2.197 62.808 2.339 ;
     RECT  2.4 2.151 2.712 2.341 ;
     RECT  2.304 2.341 2.712 2.531 ;
     RECT  47.088 1.763 48.612 2.725 ;
     RECT  10.5 2.151 10.812 2.821 ;
     RECT  32.1 2.151 32.412 2.821 ;
     RECT  47.088 2.725 48.744 2.821 ;
     RECT  49.824 1.907 51.672 2.821 ;
     RECT  26.7 2.293 27.336 2.915 ;
     RECT  41.616 2.339 46.104 2.915 ;
     RECT  19.92 2.291 21.912 2.963 ;
     RECT  41.712 2.915 46.104 2.963 ;
     RECT  7.8 2.151 8.112 3.013 ;
     RECT  13.2 2.151 13.512 3.301 ;
     RECT  39.984 2.339 40.632 3.349 ;
     RECT  15.9 2.151 16.212 3.397 ;
     RECT  37.5 2.151 37.812 3.397 ;
     RECT  39.072 3.349 40.632 3.397 ;
     RECT  45.6 2.963 46.104 3.397 ;
     RECT  47.088 2.821 51.672 3.397 ;
     RECT  19.92 2.963 21.612 3.443 ;
     RECT  41.712 2.963 44.52 3.443 ;
     RECT  45.6 3.397 51.672 3.443 ;
     RECT  32.1 2.821 33.048 3.587 ;
     RECT  45.6 3.443 46.008 3.635 ;
     RECT  24 2.291 24.312 3.637 ;
     RECT  52.656 2.339 62.664 3.731 ;
     RECT  37.5 3.397 40.632 3.875 ;
     RECT  11.952 3.397 11.976 3.971 ;
     RECT  41.712 3.443 44.472 4.019 ;
     RECT  23.328 3.637 24.312 4.115 ;
     RECT  25.632 3.397 25.656 4.115 ;
     RECT  40.08 3.875 40.632 4.117 ;
     RECT  41.712 4.019 44.376 4.117 ;
     RECT  15.9 3.397 16.824 4.165 ;
     RECT  15.648 4.165 16.824 4.259 ;
     RECT  24 4.115 24.312 4.501 ;
     RECT  26.7 2.915 27.288 4.595 ;
     RECT  40.08 4.117 44.376 4.595 ;
     RECT  42.336 4.595 44.184 4.643 ;
     RECT  13.2 3.301 14.04 4.693 ;
     RECT  18.6 2.291 18.912 4.693 ;
     RECT  45.6 3.635 45.912 4.693 ;
     RECT  47.04 3.443 51.672 4.693 ;
     RECT  32.1 3.587 32.412 4.885 ;
     RECT  31.968 4.885 32.412 5.027 ;
     RECT  37.5 3.875 39.096 5.077 ;
     RECT  40.08 4.595 41.016 5.077 ;
     RECT  52.656 3.731 62.424 5.077 ;
     RECT  32.1 5.027 32.412 5.125 ;
     RECT  45.6 4.693 51.672 5.125 ;
     RECT  52.656 5.077 62.52 5.125 ;
     RECT  32.1 5.125 32.568 5.267 ;
     RECT  5.1 2.151 5.412 5.317 ;
     RECT  22.608 5.125 22.632 5.557 ;
     RECT  24 4.501 24.408 5.557 ;
     RECT  22.608 5.557 24.408 5.699 ;
     RECT  45.6 5.125 62.52 5.845 ;
     RECT  15.648 4.259 16.344 5.939 ;
     RECT  37.5 5.077 41.016 5.987 ;
     RECT  45.072 5.845 62.52 6.035 ;
     RECT  42.336 4.643 44.088 6.037 ;
     RECT  37.5 5.987 40.512 6.083 ;
     RECT  10.368 2.821 10.812 6.229 ;
     RECT  45.168 6.035 62.52 6.229 ;
     RECT  40.08 6.083 40.512 6.323 ;
     RECT  42.048 6.037 44.088 6.373 ;
     RECT  23.328 5.699 24.408 6.611 ;
     RECT  17.856 4.693 18.912 6.661 ;
     RECT  24 6.611 24.408 6.805 ;
     RECT  41.568 6.373 44.088 6.805 ;
     RECT  37.5 6.083 38.808 7.091 ;
     RECT  29.4 2.151 29.712 7.141 ;
     RECT  24 6.805 25.224 7.187 ;
     RECT  38.784 7.091 38.808 7.235 ;
     RECT  10.32 6.229 10.812 7.379 ;
     RECT  29.088 7.141 29.712 7.379 ;
     RECT  45.168 6.229 62.712 7.379 ;
     RECT  13.2 4.693 14.088 7.381 ;
     RECT  24 7.187 24.408 7.475 ;
     RECT  45.168 7.379 47.064 7.475 ;
     RECT  21.3 3.443 21.612 7.621 ;
     RECT  0.144 7.429 0.168 7.667 ;
     RECT  48.3 7.379 62.712 7.667 ;
     RECT  2.4 2.531 2.712 7.669 ;
     RECT  40.2 6.323 40.512 7.717 ;
     RECT  41.568 6.805 44.184 7.717 ;
     RECT  2.16 7.669 2.712 7.811 ;
     RECT  21.3 7.621 21.72 7.907 ;
     RECT  40.2 7.717 44.184 7.907 ;
     RECT  41.616 7.907 44.184 7.909 ;
     RECT  45.168 7.475 46.536 7.909 ;
     RECT  3.984 7.381 4.008 8.003 ;
     RECT  13.2 7.381 14.424 8.003 ;
     RECT  41.616 7.909 46.536 8.003 ;
     RECT  36.144 6.181 36.168 8.437 ;
     RECT  37.5 7.091 37.812 8.437 ;
     RECT  40.2 7.907 40.512 8.437 ;
     RECT  15.648 5.939 16.212 8.485 ;
     RECT  41.952 8.003 46.536 8.627 ;
     RECT  42.144 8.627 46.296 8.675 ;
     RECT  32.1 5.267 32.412 8.677 ;
     RECT  44.976 8.675 46.296 8.723 ;
     RECT  32.1 8.677 33.048 8.867 ;
     RECT  42.144 8.675 43.848 8.867 ;
     RECT  45.072 8.723 46.296 8.867 ;
     RECT  34.8 2.339 35.112 8.917 ;
     RECT  32.1 8.867 32.952 9.059 ;
     RECT  48.3 7.667 62.112 9.107 ;
     RECT  49.632 9.107 62.112 9.155 ;
     RECT  42.384 8.867 43.848 9.251 ;
     RECT  7.8 3.013 8.904 9.347 ;
     RECT  19.968 9.205 19.992 9.491 ;
     RECT  5.1 5.317 5.688 9.637 ;
     RECT  39.888 8.437 40.512 9.683 ;
     RECT  42.384 9.251 43.8 9.731 ;
     RECT  49.632 9.155 59.736 9.731 ;
     RECT  42.384 9.731 43.752 9.779 ;
     RECT  33.984 8.917 35.112 9.827 ;
     RECT  49.632 9.731 59.544 9.875 ;
     RECT  45.6 8.867 46.296 9.925 ;
     RECT  17.328 6.661 18.912 10.069 ;
     RECT  29.4 7.379 29.712 10.069 ;
     RECT  42.768 9.779 43.752 10.115 ;
     RECT  21.3 7.907 21.612 10.117 ;
     RECT  5.1 9.637 6.264 10.213 ;
     RECT  17.328 10.069 19.08 10.213 ;
     RECT  25.392 9.109 25.416 10.307 ;
     RECT  15.552 8.485 16.212 10.645 ;
     RECT  29.232 10.069 29.712 10.693 ;
     RECT  15.216 10.645 16.212 10.787 ;
     RECT  4.464 10.213 6.264 10.789 ;
     RECT  7.8 9.347 8.112 10.789 ;
     RECT  29.04 10.693 29.712 10.883 ;
     RECT  36.144 8.437 37.812 10.883 ;
     RECT  50.256 9.875 59.544 10.883 ;
     RECT  10.368 7.379 10.812 10.885 ;
     RECT  50.256 10.883 54.216 10.931 ;
     RECT  50.256 10.931 52.008 10.979 ;
     RECT  9.744 10.885 10.812 11.027 ;
     RECT  4.464 10.789 8.112 11.125 ;
     RECT  37.104 10.883 37.812 11.171 ;
     RECT  45.6 9.925 46.584 11.171 ;
     RECT  34.8 9.827 35.112 11.221 ;
     RECT  50.256 10.979 51.864 11.267 ;
     RECT  4.464 11.125 8.232 11.459 ;
     RECT  55.2 10.883 59.544 11.459 ;
     RECT  55.824 11.459 59.544 11.555 ;
     RECT  22.8 11.509 22.824 11.699 ;
     RECT  48.3 9.107 48.612 11.749 ;
     RECT  17.28 10.213 19.08 11.987 ;
     RECT  26.7 4.595 27.012 11.989 ;
     RECT  42.9 10.115 43.752 11.989 ;
     RECT  33.84 11.221 35.112 12.035 ;
     RECT  51 11.267 51.864 12.035 ;
     RECT  53.04 10.931 54.216 12.035 ;
     RECT  42.768 11.989 43.752 12.275 ;
     RECT  53.568 12.035 54.216 12.323 ;
     RECT  51 12.035 51.72 12.371 ;
     RECT  10.368 11.027 10.812 12.517 ;
     RECT  24 7.475 24.312 12.517 ;
     RECT  40.2 9.683 40.512 12.517 ;
     RECT  42.9 12.275 43.752 12.517 ;
     RECT  45.6 11.171 46.008 12.517 ;
     RECT  26.544 11.989 27.012 12.563 ;
     RECT  51 12.371 51.624 12.563 ;
     RECT  29.232 10.883 29.712 12.613 ;
     RECT  48.3 11.749 48.744 12.709 ;
     RECT  40.2 12.517 40.872 12.899 ;
     RECT  47.424 12.709 48.744 12.899 ;
     RECT  56.4 11.555 59.544 13.139 ;
     RECT  61.056 9.155 62.112 13.139 ;
     RECT  42.9 12.517 43.896 13.285 ;
     RECT  45.216 12.517 46.008 13.285 ;
     RECT  58.128 13.139 59.544 13.331 ;
     RECT  42.9 13.285 46.008 13.427 ;
     RECT  53.7 12.323 54.216 13.573 ;
     RECT  4.464 11.459 6.264 13.619 ;
     RECT  51 12.563 51.576 13.621 ;
     RECT  48.3 12.899 48.744 13.667 ;
     RECT  15.552 10.787 16.212 13.715 ;
     RECT  29.088 12.613 29.712 13.811 ;
     RECT  56.4 13.139 57 13.813 ;
     RECT  10.032 12.517 10.812 13.859 ;
     RECT  4.464 13.619 6.216 13.907 ;
     RECT  21.168 10.117 21.612 13.909 ;
     RECT  21.072 13.909 21.612 14.197 ;
     RECT  23.712 12.517 24.312 14.197 ;
     RECT  45.216 13.427 46.008 14.243 ;
     RECT  18.048 11.987 19.08 14.245 ;
     RECT  10.368 13.859 10.812 14.291 ;
     RECT  13.2 8.003 14.088 14.291 ;
     RECT  29.232 13.811 29.712 14.291 ;
     RECT  26.7 12.563 27.012 14.293 ;
     RECT  50.064 13.621 51.576 14.387 ;
     RECT  10.5 14.291 10.812 14.773 ;
     RECT  55.872 13.813 57 14.773 ;
     RECT  58.416 13.331 59.544 14.773 ;
     RECT  15.9 13.715 16.212 14.821 ;
     RECT  21.072 14.197 22.152 14.915 ;
     RECT  40.2 12.899 40.512 14.917 ;
     RECT  55.872 14.773 59.544 14.963 ;
     RECT  15.9 14.821 16.584 15.395 ;
     RECT  7.8 11.459 8.232 15.397 ;
     RECT  10.5 14.773 11.4 15.443 ;
     RECT  18.048 14.245 19.368 15.443 ;
     RECT  23.52 14.197 24.312 15.443 ;
     RECT  29.28 14.291 29.712 15.443 ;
     RECT  55.872 14.963 59.412 15.443 ;
     RECT  40.2 14.917 40.92 15.445 ;
     RECT  5.1 13.907 6.216 15.587 ;
     RECT  21.3 14.915 22.152 15.635 ;
     RECT  39.888 15.445 40.92 15.877 ;
     RECT  26.7 14.293 27.768 15.973 ;
     RECT  32.1 9.059 32.412 15.973 ;
     RECT  55.872 15.443 56.808 16.019 ;
     RECT  31.44 15.973 32.412 16.069 ;
     RECT  45.36 14.243 46.008 16.259 ;
     RECT  53.7 13.573 54.456 16.259 ;
     RECT  5.1 15.587 5.64 16.307 ;
     RECT  26.7 15.973 27.864 16.355 ;
     RECT  13.2 14.291 13.704 16.357 ;
     RECT  48.3 13.667 48.612 16.357 ;
     RECT  31.344 16.069 32.412 16.403 ;
     RECT  24 15.443 24.312 16.501 ;
     RECT  34.8 12.035 35.112 16.501 ;
     RECT  33.6 14.101 33.624 16.547 ;
     RECT  29.4 15.443 29.712 16.597 ;
     RECT  7.344 15.397 8.232 16.835 ;
     RECT  14.784 16.645 14.808 16.837 ;
     RECT  15.9 15.395 16.212 16.837 ;
     RECT  39.888 15.877 41.016 16.931 ;
     RECT  29.28 16.597 29.712 16.979 ;
     RECT  15.9 16.837 16.584 16.981 ;
     RECT  42.9 13.427 43.752 17.029 ;
     RECT  24 16.501 24.456 17.077 ;
     RECT  37.5 11.171 37.812 17.077 ;
     RECT  15.9 16.981 17.112 17.123 ;
     RECT  57.792 15.443 59.412 17.123 ;
     RECT  14.784 16.837 14.856 17.171 ;
     RECT  24 17.077 25.128 17.219 ;
     RECT  37.056 17.077 37.812 17.219 ;
     RECT  50.112 14.387 51.576 17.219 ;
     RECT  48 16.357 48.612 17.315 ;
     RECT  50.16 17.219 51.576 17.315 ;
     RECT  45.6 16.259 46.008 17.317 ;
     RECT  13.104 16.357 13.704 17.557 ;
     RECT  50.16 17.315 51.432 17.603 ;
     RECT  7.344 16.835 8.112 17.605 ;
     RECT  26.7 16.355 27.72 17.651 ;
     RECT  53.7 16.259 54.216 17.795 ;
     RECT  58.128 17.123 59.412 17.891 ;
     RECT  21.3 15.635 21.612 17.893 ;
     RECT  58.368 17.891 59.412 17.939 ;
     RECT  13.104 17.557 13.8 18.035 ;
     RECT  48.192 17.315 48.612 18.181 ;
     RECT  34.704 16.501 35.112 18.227 ;
     RECT  42.9 17.029 43.848 18.227 ;
     RECT  14.832 17.171 14.856 18.275 ;
     RECT  10.5 15.443 10.812 18.469 ;
     RECT  36.288 18.181 36.312 18.469 ;
     RECT  37.392 17.219 37.812 18.469 ;
     RECT  40.032 16.931 41.016 18.515 ;
     RECT  50.16 17.603 51.312 18.563 ;
     RECT  18.48 15.443 19.368 18.565 ;
     RECT  13.2 18.035 13.8 18.757 ;
     RECT  22.848 16.501 22.872 18.757 ;
     RECT  22.848 18.757 22.968 18.803 ;
     RECT  53.7 17.795 54.168 18.803 ;
     RECT  7.008 17.605 8.112 18.851 ;
     RECT  15.9 17.123 16.584 18.851 ;
     RECT  22.944 18.803 22.968 18.949 ;
     RECT  24 17.219 25.08 18.949 ;
     RECT  18.48 18.565 19.752 18.995 ;
     RECT  22.944 18.949 25.08 18.995 ;
     RECT  21.168 17.893 21.612 19.333 ;
     RECT  23.76 18.995 25.08 19.379 ;
     RECT  36.288 18.469 37.812 19.427 ;
     RECT  48.192 18.181 48.888 19.427 ;
     RECT  18.48 18.995 19.368 19.571 ;
     RECT  13.2 18.757 14.04 19.909 ;
     RECT  23.76 19.379 24.312 19.957 ;
     RECT  22.8 19.957 24.312 20.099 ;
     RECT  12.768 19.909 14.04 20.147 ;
     RECT  37.2 19.427 37.812 20.677 ;
     RECT  40.032 18.515 40.512 20.677 ;
     RECT  10.368 18.469 10.812 20.869 ;
     RECT  39.552 20.677 40.728 20.915 ;
     RECT  7.68 18.851 8.112 21.061 ;
     RECT  26.7 17.651 27.012 21.061 ;
     RECT  28.368 18.709 28.392 21.061 ;
     RECT  12.768 20.147 13.704 21.109 ;
     RECT  15.9 18.851 16.212 21.109 ;
     RECT  20.688 19.333 21.612 21.155 ;
     RECT  25.68 19.909 25.704 21.155 ;
     RECT  9.696 20.869 10.812 21.157 ;
     RECT  26.7 21.061 28.392 21.251 ;
     RECT  12.768 21.109 13.8 21.349 ;
     RECT  36.48 20.677 37.812 21.395 ;
     RECT  6.816 21.061 8.112 21.397 ;
     RECT  18.6 19.571 19.368 21.397 ;
     RECT  21.168 21.155 21.612 21.683 ;
     RECT  15.9 21.109 16.488 22.117 ;
     RECT  36.576 21.395 37.812 22.211 ;
     RECT  9.696 21.157 10.92 22.259 ;
     RECT  26.7 21.251 27.576 22.259 ;
     RECT  39.552 20.915 40.512 22.259 ;
     RECT  48.3 19.427 48.888 22.259 ;
     RECT  6.816 21.397 8.232 22.307 ;
     RECT  12.672 21.349 13.8 22.307 ;
     RECT  39.936 22.259 40.512 22.307 ;
     RECT  18.144 21.397 19.368 22.501 ;
     RECT  6.816 22.307 8.112 22.835 ;
     RECT  26.7 22.259 27.288 22.835 ;
     RECT  45.6 17.317 46.68 22.835 ;
     RECT  44.208 22.165 44.232 22.883 ;
     RECT  32.1 16.403 32.412 22.981 ;
     RECT  23.76 20.099 24.312 23.125 ;
     RECT  45.6 22.835 46.104 23.267 ;
     RECT  13.2 22.307 13.8 23.269 ;
     RECT  23.76 23.125 24.408 23.317 ;
     RECT  10.5 22.259 10.92 23.363 ;
     RECT  15.744 22.117 16.488 23.363 ;
     RECT  7.68 22.835 8.112 23.411 ;
     RECT  18.144 22.501 19.944 23.411 ;
     RECT  15.9 23.363 16.488 23.701 ;
     RECT  13.2 23.269 14.616 23.893 ;
     RECT  32.1 22.981 32.52 24.131 ;
     RECT  36.96 22.211 37.812 24.131 ;
     RECT  21.3 21.683 21.612 24.277 ;
     RECT  15.9 23.701 16.728 24.325 ;
     RECT  18.6 23.411 19.368 24.469 ;
     RECT  23.472 23.317 24.792 24.469 ;
     RECT  30.72 23.797 30.744 24.515 ;
     RECT  21.168 24.277 21.612 24.757 ;
     RECT  29.4 16.979 29.712 24.997 ;
     RECT  45.6 23.267 46.056 24.997 ;
     RECT  45.216 24.997 46.056 25.043 ;
     RECT  12.384 23.893 14.616 25.045 ;
     RECT  15.9 24.325 17.592 25.045 ;
     RECT  18.6 24.469 19.8 25.045 ;
     RECT  21.12 24.757 21.612 25.187 ;
     RECT  22.992 24.469 24.792 25.381 ;
     RECT  12.384 25.045 19.8 25.475 ;
     RECT  10.5 23.363 10.812 25.669 ;
     RECT  12.384 25.475 18.912 25.669 ;
     RECT  10.5 25.669 18.912 25.715 ;
     RECT  28.8 24.997 29.712 25.715 ;
     RECT  45.216 25.043 45.912 25.715 ;
     RECT  37.2 24.131 37.812 25.859 ;
     RECT  34.8 18.227 35.112 26.149 ;
     RECT  10.5 25.715 16.536 26.243 ;
     RECT  17.616 25.715 18.912 26.243 ;
     RECT  41.568 24.469 41.592 26.627 ;
     RECT  34.8 26.149 35.832 26.675 ;
     RECT  22.992 25.381 25.08 26.773 ;
     RECT  2.4 7.811 2.712 27.009 ;
     RECT  5.1 16.307 5.412 27.009 ;
     RECT  7.8 23.411 8.112 27.009 ;
     RECT  18.6 26.243 18.912 27.009 ;
     RECT  21.3 25.187 21.612 27.009 ;
     RECT  26.7 22.835 27.012 27.009 ;
     RECT  29.4 25.715 29.712 27.009 ;
     RECT  32.1 24.131 32.412 27.009 ;
     RECT  34.8 26.675 35.112 27.009 ;
     RECT  37.5 25.859 37.812 27.009 ;
     RECT  40.2 22.307 40.512 27.009 ;
     RECT  42.9 18.227 43.212 27.009 ;
     RECT  45.6 25.715 45.912 27.009 ;
     RECT  48.3 22.259 48.612 27.009 ;
     RECT  51 18.563 51.312 27.009 ;
     RECT  53.7 18.803 54.012 27.009 ;
     RECT  56.4 16.019 56.712 27.009 ;
     RECT  59.1 17.939 59.412 27.009 ;
     RECT  61.8 13.139 62.112 27.009 ;
     RECT  2.4 27.009 2.52 27.023 ;
     RECT  5.1 27.009 5.22 27.023 ;
     RECT  7.8 27.009 7.92 27.023 ;
     RECT  10.5 26.243 16.44 27.023 ;
     RECT  18.6 27.009 18.72 27.023 ;
     RECT  21.3 27.009 21.48 27.023 ;
     RECT  26.7 27.009 26.82 27.023 ;
     RECT  29.4 27.009 29.52 27.023 ;
     RECT  32.1 27.009 32.22 27.023 ;
     RECT  34.8 27.009 34.92 27.023 ;
     RECT  37.5 27.009 37.62 27.023 ;
     RECT  40.2 27.009 40.32 27.023 ;
     RECT  42.9 27.009 43.02 27.023 ;
     RECT  45.6 27.009 45.72 27.023 ;
     RECT  48.3 27.009 48.42 27.023 ;
     RECT  51 27.009 51.12 27.023 ;
     RECT  53.7 27.009 53.82 27.023 ;
     RECT  56.4 27.009 56.52 27.023 ;
     RECT  59.1 27.009 59.22 27.023 ;
     RECT  61.8 27.009 61.92 27.023 ;
     RECT  22.992 26.773 25.512 27.061 ;
     RECT  10.656 27.023 16.44 27.253 ;
     RECT  22.992 27.061 25.8 27.301 ;
     RECT  22.464 27.301 25.8 28.981 ;
     RECT  21.456 27.023 21.48 29.029 ;
     RECT  22.464 28.981 25.944 29.029 ;
     RECT  10.656 27.253 16.728 29.076 ;
     RECT  10.68 29.076 10.8 29.136 ;
     RECT  10.824 29.076 10.944 29.136 ;
     RECT  10.968 29.076 11.088 29.136 ;
     RECT  11.112 29.076 11.232 29.136 ;
     RECT  11.256 29.076 11.376 29.136 ;
     RECT  11.4 29.076 11.52 29.136 ;
     RECT  11.544 29.076 11.664 29.136 ;
     RECT  11.688 29.076 11.808 29.136 ;
     RECT  11.832 29.076 11.952 29.136 ;
     RECT  11.976 29.076 12.096 29.136 ;
     RECT  12.12 29.076 12.24 29.136 ;
     RECT  12.264 29.076 12.384 29.136 ;
     RECT  12.408 29.076 12.528 29.136 ;
     RECT  12.552 29.076 12.672 29.136 ;
     RECT  12.696 29.076 12.816 29.136 ;
     RECT  12.84 29.076 12.96 29.136 ;
     RECT  12.984 29.076 13.104 29.136 ;
     RECT  13.128 29.076 13.248 29.136 ;
     RECT  13.272 29.076 13.392 29.136 ;
     RECT  13.416 29.076 13.536 29.136 ;
     RECT  13.56 29.076 13.68 29.136 ;
     RECT  13.704 29.076 13.824 29.136 ;
     RECT  13.848 29.076 13.968 29.136 ;
     RECT  13.992 29.076 14.112 29.136 ;
     RECT  14.136 29.076 14.256 29.136 ;
     RECT  14.28 29.076 14.4 29.136 ;
     RECT  14.424 29.076 14.544 29.136 ;
     RECT  14.568 29.076 14.688 29.136 ;
     RECT  14.712 29.076 14.832 29.136 ;
     RECT  14.856 29.076 14.976 29.136 ;
     RECT  15 29.076 15.12 29.136 ;
     RECT  15.144 29.076 15.264 29.136 ;
     RECT  15.288 29.076 15.408 29.136 ;
     RECT  15.432 29.076 15.552 29.136 ;
     RECT  15.576 29.076 15.696 29.136 ;
     RECT  15.72 29.076 15.84 29.136 ;
     RECT  15.864 29.076 15.984 29.136 ;
     RECT  16.008 29.076 16.128 29.136 ;
     RECT  16.152 29.076 16.272 29.136 ;
     RECT  16.296 29.076 16.416 29.136 ;
     RECT  16.44 29.076 16.56 29.136 ;
     RECT  16.584 29.076 16.704 29.136 ;
     RECT  21.456 29.029 25.944 29.076 ;
     RECT  21.48 29.076 21.6 29.136 ;
     RECT  21.624 29.076 21.744 29.136 ;
     RECT  21.768 29.076 21.888 29.136 ;
     RECT  21.912 29.076 22.032 29.136 ;
     RECT  22.056 29.076 22.176 29.136 ;
     RECT  22.2 29.076 22.32 29.136 ;
     RECT  22.344 29.076 22.464 29.136 ;
     RECT  22.488 29.076 22.608 29.136 ;
     RECT  22.632 29.076 22.752 29.136 ;
     RECT  22.776 29.076 22.896 29.136 ;
     RECT  22.92 29.076 23.04 29.136 ;
     RECT  23.064 29.076 23.184 29.136 ;
     RECT  23.208 29.076 23.328 29.136 ;
     RECT  23.352 29.076 23.472 29.136 ;
     RECT  23.496 29.076 23.616 29.136 ;
     RECT  23.64 29.076 23.76 29.136 ;
     RECT  23.784 29.076 23.904 29.136 ;
     RECT  23.928 29.076 24.048 29.136 ;
     RECT  24.072 29.076 24.192 29.136 ;
     RECT  24.216 29.076 24.336 29.136 ;
     RECT  24.36 29.076 24.48 29.136 ;
     RECT  24.504 29.076 24.624 29.136 ;
     RECT  24.648 29.076 24.768 29.136 ;
     RECT  24.792 29.076 24.912 29.136 ;
     RECT  24.936 29.076 25.056 29.136 ;
     RECT  25.08 29.076 25.2 29.136 ;
     RECT  25.224 29.076 25.344 29.136 ;
     RECT  25.368 29.076 25.488 29.136 ;
     RECT  25.512 29.076 25.632 29.136 ;
     RECT  25.656 29.076 25.776 29.136 ;
     RECT  25.8 29.076 25.92 29.136 ;
     RECT  57.096 0.016 58.272 0.132 ;
     RECT  57.048 0.132 58.32 0.179 ;
     RECT  56.904 0.179 58.32 2.197 ;
     RECT  38.736 1.763 39.024 1.811 ;
     RECT  46.104 1.763 47.088 3.397 ;
     RECT  48.612 1.763 49.68 1.811 ;
     RECT  21.912 1.811 22.896 2.291 ;
     RECT  38.736 1.811 39.312 1.859 ;
     RECT  48.612 1.811 49.824 2.725 ;
     RECT  38.736 1.859 39.456 2.137 ;
     RECT  51.672 1.907 52.656 5.125 ;
     RECT  37.62 2.137 39.456 2.151 ;
     RECT  37.812 2.151 39.456 2.291 ;
     RECT  18.912 2.291 19.92 3.443 ;
     RECT  21.912 2.291 24 2.963 ;
     RECT  37.812 2.291 39.984 3.349 ;
     RECT  40.632 2.339 41.616 2.915 ;
     RECT  48.744 2.725 49.824 2.821 ;
     RECT  40.632 2.915 41.712 4.117 ;
     RECT  23.328 2.963 24 3.637 ;
     RECT  44.52 2.963 45.6 3.443 ;
     RECT  8.904 3.013 10.368 6.229 ;
     RECT  37.812 3.349 39.072 3.397 ;
     RECT  10.812 3.397 11.952 3.971 ;
     RECT  11.976 3.397 13.2 3.971 ;
     RECT  24.312 3.397 25.632 4.115 ;
     RECT  25.656 3.397 26.7 4.115 ;
     RECT  44.472 3.443 45.6 4.019 ;
     RECT  46.008 3.443 47.04 3.635 ;
     RECT  45.912 3.635 47.04 4.693 ;
     RECT  62.424 3.731 62.52 5.077 ;
     RECT  39.096 3.875 40.08 5.077 ;
     RECT  44.376 4.019 45.6 4.595 ;
     RECT  23.328 4.115 24 5.125 ;
     RECT  24.312 4.115 24.408 4.501 ;
     RECT  16.344 4.259 16.824 4.693 ;
     RECT  41.016 4.595 42.336 5.987 ;
     RECT  44.184 4.595 45.6 4.643 ;
     RECT  44.088 4.643 45.6 5.845 ;
     RECT  16.344 4.693 17.856 5.939 ;
     RECT  21.612 5.125 22.608 5.699 ;
     RECT  22.632 5.125 24 5.557 ;
     RECT  44.088 5.845 45.072 6.035 ;
     RECT  16.212 5.939 17.856 6.661 ;
     RECT  40.512 5.987 42.336 6.037 ;
     RECT  44.088 6.035 45.168 6.805 ;
     RECT  40.512 6.037 42.048 6.373 ;
     RECT  38.808 6.083 40.08 6.323 ;
     RECT  35.112 6.181 36.144 10.883 ;
     RECT  36.168 6.181 37.5 8.437 ;
     RECT  8.904 6.229 10.32 7.379 ;
     RECT  38.808 6.323 40.2 7.235 ;
     RECT  40.512 6.373 41.568 7.717 ;
     RECT  16.212 6.661 17.328 10.213 ;
     RECT  25.224 6.805 26.7 7.187 ;
     RECT  44.184 6.805 45.168 7.909 ;
     RECT  37.812 7.091 38.784 7.235 ;
     RECT  39.888 7.235 40.2 8.437 ;
     RECT  8.904 7.379 10.368 9.347 ;
     RECT  47.064 7.379 48.3 7.475 ;
     RECT  2.712 7.381 3.984 8.003 ;
     RECT  4.008 7.381 5.1 8.003 ;
     RECT  14.424 7.381 15.648 8.003 ;
     RECT  40.512 7.907 41.616 8.003 ;
     RECT  14.088 8.003 15.648 8.485 ;
     RECT  40.512 8.003 41.952 8.627 ;
     RECT  14.088 8.485 15.552 10.645 ;
     RECT  46.296 8.627 46.536 9.925 ;
     RECT  43.848 8.675 44.976 8.723 ;
     RECT  43.848 8.723 45.072 8.867 ;
     RECT  32.952 8.867 33.048 8.917 ;
     RECT  32.952 8.917 33.984 9.059 ;
     RECT  48.612 9.107 49.632 9.875 ;
     RECT  24.312 9.109 25.392 10.307 ;
     RECT  25.416 9.109 26.7 10.307 ;
     RECT  59.736 9.155 61.056 9.731 ;
     RECT  18.912 9.205 19.968 9.491 ;
     RECT  19.992 9.205 21.3 9.491 ;
     RECT  18.912 9.491 19.08 10.069 ;
     RECT  21.168 9.491 21.3 10.117 ;
     RECT  59.544 9.731 61.056 13.139 ;
     RECT  33.984 9.827 34.8 11.221 ;
     RECT  16.212 10.213 17.28 11.987 ;
     RECT  14.088 10.645 15.216 10.787 ;
     RECT  14.088 10.787 15.552 13.715 ;
     RECT  54.216 10.883 55.2 11.459 ;
     RECT  52.008 10.931 53.04 10.979 ;
     RECT  51.864 10.979 53.04 12.035 ;
     RECT  10.032 11.027 10.368 12.517 ;
     RECT  32.412 11.221 33.84 12.035 ;
     RECT  21.612 11.509 22.8 11.699 ;
     RECT  22.824 11.509 24 11.699 ;
     RECT  23.712 11.699 24 12.517 ;
     RECT  43.896 12.517 45.216 13.285 ;
     RECT  46.008 12.709 47.424 12.899 ;
     RECT  57 13.139 58.128 13.331 ;
     RECT  57 13.331 58.416 14.773 ;
     RECT  43.752 13.427 45.216 14.243 ;
     RECT  48.744 13.621 50.064 13.667 ;
     RECT  48.612 13.667 50.064 14.387 ;
     RECT  29.088 13.811 29.232 14.291 ;
     RECT  54.456 13.813 55.872 16.019 ;
     RECT  32.412 14.101 33.6 16.547 ;
     RECT  33.624 14.101 34.8 16.501 ;
     RECT  22.152 14.197 23.52 15.443 ;
     RECT  29.088 14.291 29.28 14.293 ;
     RECT  27.768 14.293 29.28 15.443 ;
     RECT  48.612 14.387 50.112 17.219 ;
     RECT  16.584 14.821 18.048 15.395 ;
     RECT  16.212 15.395 18.048 15.443 ;
     RECT  6.216 15.397 7.344 15.587 ;
     RECT  16.212 15.443 16.584 16.837 ;
     RECT  22.152 15.443 24 15.635 ;
     RECT  27.768 15.443 29.4 15.973 ;
     RECT  56.808 15.443 57.792 16.019 ;
     RECT  21.612 15.635 24 16.501 ;
     RECT  27.864 15.973 29.4 16.355 ;
     RECT  56.712 16.019 57.792 17.123 ;
     RECT  29.28 16.355 29.4 16.597 ;
     RECT  21.612 16.501 22.848 18.803 ;
     RECT  22.872 16.501 24 18.757 ;
     RECT  33.624 16.501 34.704 16.547 ;
     RECT  13.704 16.645 14.784 17.171 ;
     RECT  14.808 16.645 15.9 16.837 ;
     RECT  14.856 16.837 15.9 18.275 ;
     RECT  17.112 16.981 18.48 17.123 ;
     RECT  56.712 17.123 58.128 17.891 ;
     RECT  13.704 17.171 14.832 17.557 ;
     RECT  37.056 17.219 37.392 18.181 ;
     RECT  48.612 17.219 50.16 18.181 ;
     RECT  48 17.315 48.192 17.317 ;
     RECT  46.68 17.317 48.192 19.427 ;
     RECT  13.8 17.557 14.832 18.275 ;
     RECT  27.012 17.651 27.72 18.709 ;
     RECT  35.112 18.181 36.288 19.427 ;
     RECT  36.312 18.181 37.392 18.469 ;
     RECT  48.888 18.181 50.16 18.563 ;
     RECT  13.8 18.275 14.04 18.757 ;
     RECT  19.752 18.565 21.168 18.995 ;
     RECT  27.012 18.709 28.368 21.061 ;
     RECT  28.392 18.709 29.4 21.251 ;
     RECT  22.968 18.757 24 18.949 ;
     RECT  21.612 18.803 22.944 18.995 ;
     RECT  19.368 18.995 21.168 19.333 ;
     RECT  21.612 18.995 23.76 19.957 ;
     RECT  19.368 19.333 20.688 21.155 ;
     RECT  24.312 19.379 25.08 19.909 ;
     RECT  35.112 19.427 37.2 20.677 ;
     RECT  24.312 19.909 25.68 21.155 ;
     RECT  25.704 19.909 26.7 21.155 ;
     RECT  21.612 19.957 22.8 20.099 ;
     RECT  13.704 20.147 13.8 21.109 ;
     RECT  35.112 20.677 36.48 21.395 ;
     RECT  5.412 21.061 6.816 22.835 ;
     RECT  19.368 21.155 21.168 21.683 ;
     RECT  35.112 21.395 36.576 22.211 ;
     RECT  8.232 21.397 9.696 22.259 ;
     RECT  19.368 21.683 21.3 22.501 ;
     RECT  43.212 22.165 44.208 22.883 ;
     RECT  44.232 22.165 45.6 22.883 ;
     RECT  19.944 22.501 21.3 23.411 ;
     RECT  14.616 23.269 15.744 23.363 ;
     RECT  14.616 23.363 15.9 25.045 ;
     RECT  18.144 23.411 18.6 23.701 ;
     RECT  19.368 23.411 21.3 24.277 ;
     RECT  16.728 23.701 18.6 24.325 ;
     RECT  29.712 23.797 30.72 24.515 ;
     RECT  30.744 23.797 32.1 24.515 ;
     RECT  19.368 24.277 21.168 24.469 ;
     RECT  17.592 24.325 18.6 25.045 ;
     RECT  19.8 24.469 21.168 24.757 ;
     RECT  21.612 24.469 22.992 27.009 ;
     RECT  40.512 24.469 41.568 26.627 ;
     RECT  41.592 24.469 42.9 26.627 ;
     RECT  19.8 24.757 21.12 25.187 ;
     RECT  19.8 25.187 21.3 25.475 ;
     RECT  16.536 25.715 17.616 26.243 ;
     RECT  16.44 26.243 16.728 27.253 ;
     RECT  25.512 26.773 26.7 27.023 ;
     RECT  21.48 27.009 22.992 27.301 ;
     RECT  25.512 27.023 25.8 27.061 ;
     RECT  21.48 27.301 22.464 29.028 ;
     RECT  21.528 29.028 21.552 29.029 ;
     RECT  21.672 29.028 21.696 29.029 ;
     RECT  21.816 29.028 21.84 29.029 ;
     RECT  21.96 29.028 21.984 29.029 ;
     RECT  22.104 29.028 22.128 29.029 ;
     RECT  22.248 29.028 22.272 29.029 ;
     RECT  22.392 29.028 22.416 29.029 ;
  END
END qkd_seq_core_static
END LIBRARY
